VERSION 5.8 ;
BUSBITCHARS "[]" ;
DIVIDERCHAR "/" ;
UNITS
    DATABASE MICRONS 1000 ;
END UNITS

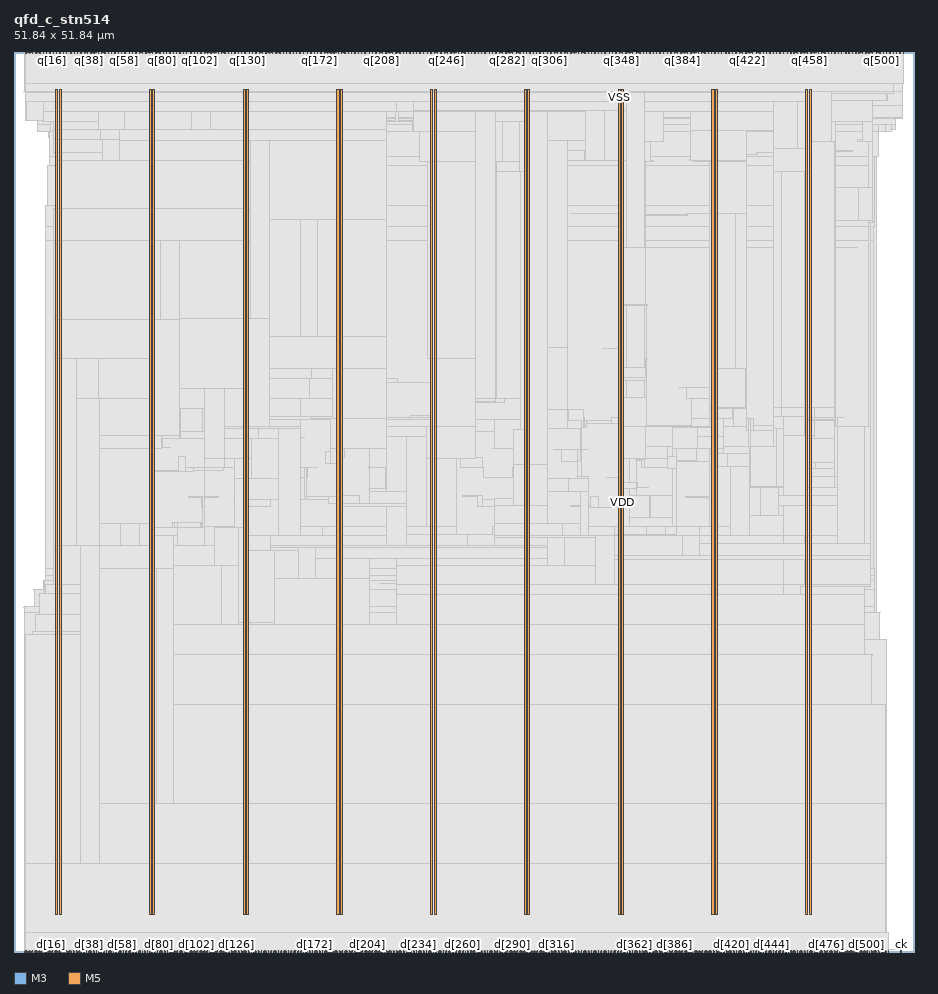
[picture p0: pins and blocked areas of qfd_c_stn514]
MACRO qfd_c_stn514
  FOREIGN qfd_c_stn514 0 0 ;
  CLASS BLOCK ;
  SIZE 51.84 BY 51.84 ;
  PIN ck
    DIRECTION INPUT ;
    USE SIGNAL ;
    PORT
      LAYER M3 ;
        RECT  51.084 0 51.102 0.038 ;
    END
    PORT
      LAYER M3 ;
        RECT  51.084 0.012 51.102 0.173 ;
    END
  END ck
  PIN d[0]
    DIRECTION INPUT ;
    USE SIGNAL ;
    PORT
      LAYER M3 ;
        RECT  0.576 0 0.594 0.038 ;
    END
  END d[0]
  PIN d[100]
    DIRECTION INPUT ;
    USE SIGNAL ;
    PORT
      LAYER M3 ;
        RECT  10.296 0 10.314 0.038 ;
    END
  END d[100]
  PIN d[101]
    DIRECTION INPUT ;
    USE SIGNAL ;
    PORT
      LAYER M5 ;
        RECT  10.368 0 10.392 0.084 ;
    END
  END d[101]
  PIN d[102]
    DIRECTION INPUT ;
    USE SIGNAL ;
    PORT
      LAYER M3 ;
        RECT  10.476 0 10.494 0.038 ;
    END
  END d[102]
  PIN d[103]
    DIRECTION INPUT ;
    USE SIGNAL ;
    PORT
      LAYER M5 ;
        RECT  10.56 0 10.584 0.084 ;
    END
  END d[103]
  PIN d[104]
    DIRECTION INPUT ;
    USE SIGNAL ;
    PORT
      LAYER M3 ;
        RECT  10.656 0 10.674 0.038 ;
    END
  END d[104]
  PIN d[105]
    DIRECTION INPUT ;
    USE SIGNAL ;
    PORT
      LAYER M5 ;
        RECT  10.752 0 10.776 0.084 ;
    END
  END d[105]
  PIN d[106]
    DIRECTION INPUT ;
    USE SIGNAL ;
    PORT
      LAYER M3 ;
        RECT  10.872 0 10.89 0.038 ;
    END
  END d[106]
  PIN d[107]
    DIRECTION INPUT ;
    USE SIGNAL ;
    PORT
      LAYER M5 ;
        RECT  10.944 0 10.968 0.084 ;
    END
  END d[107]
  PIN d[108]
    DIRECTION INPUT ;
    USE SIGNAL ;
    PORT
      LAYER M3 ;
        RECT  11.052 0 11.07 0.038 ;
    END
  END d[108]
  PIN d[109]
    DIRECTION INPUT ;
    USE SIGNAL ;
    PORT
      LAYER M5 ;
        RECT  11.136 0 11.16 0.084 ;
    END
  END d[109]
  PIN d[10]
    DIRECTION INPUT ;
    USE SIGNAL ;
    PORT
      LAYER M3 ;
        RECT  1.548 0 1.566 0.038 ;
    END
  END d[10]
  PIN d[110]
    DIRECTION INPUT ;
    USE SIGNAL ;
    PORT
      LAYER M3 ;
        RECT  11.268 0 11.286 0.038 ;
    END
  END d[110]
  PIN d[111]
    DIRECTION INPUT ;
    USE SIGNAL ;
    PORT
      LAYER M5 ;
        RECT  11.328 0 11.352 0.084 ;
    END
  END d[111]
  PIN d[112]
    DIRECTION INPUT ;
    USE SIGNAL ;
    PORT
      LAYER M3 ;
        RECT  11.448 0 11.466 0.038 ;
    END
  END d[112]
  PIN d[113]
    DIRECTION INPUT ;
    USE SIGNAL ;
    PORT
      LAYER M5 ;
        RECT  11.52 0 11.544 0.084 ;
    END
  END d[113]
  PIN d[114]
    DIRECTION INPUT ;
    USE SIGNAL ;
    PORT
      LAYER M3 ;
        RECT  11.628 0 11.646 0.038 ;
    END
  END d[114]
  PIN d[115]
    DIRECTION INPUT ;
    USE SIGNAL ;
    PORT
      LAYER M5 ;
        RECT  11.712 0 11.736 0.084 ;
    END
  END d[115]
  PIN d[116]
    DIRECTION INPUT ;
    USE SIGNAL ;
    PORT
      LAYER M3 ;
        RECT  11.844 0 11.862 0.038 ;
    END
  END d[116]
  PIN d[117]
    DIRECTION INPUT ;
    USE SIGNAL ;
    PORT
      LAYER M5 ;
        RECT  11.904 0 11.928 0.084 ;
    END
  END d[117]
  PIN d[118]
    DIRECTION INPUT ;
    USE SIGNAL ;
    PORT
      LAYER M3 ;
        RECT  12.024 0 12.042 0.038 ;
    END
  END d[118]
  PIN d[119]
    DIRECTION INPUT ;
    USE SIGNAL ;
    PORT
      LAYER M5 ;
        RECT  12.144 0 12.168 0.084 ;
    END
  END d[119]
  PIN d[11]
    DIRECTION INPUT ;
    USE SIGNAL ;
    PORT
      LAYER M5 ;
        RECT  1.632 0 1.656 0.084 ;
    END
  END d[11]
  PIN d[120]
    DIRECTION INPUT ;
    USE SIGNAL ;
    PORT
      LAYER M3 ;
        RECT  12.204 0 12.222 0.038 ;
    END
  END d[120]
  PIN d[121]
    DIRECTION INPUT ;
    USE SIGNAL ;
    PORT
      LAYER M5 ;
        RECT  12.336 0 12.36 0.084 ;
    END
  END d[121]
  PIN d[122]
    DIRECTION INPUT ;
    USE SIGNAL ;
    PORT
      LAYER M3 ;
        RECT  12.42 0 12.438 0.038 ;
    END
  END d[122]
  PIN d[123]
    DIRECTION INPUT ;
    USE SIGNAL ;
    PORT
      LAYER M5 ;
        RECT  12.528 0 12.552 0.084 ;
    END
  END d[123]
  PIN d[124]
    DIRECTION INPUT ;
    USE SIGNAL ;
    PORT
      LAYER M3 ;
        RECT  12.6 0 12.618 0.038 ;
    END
  END d[124]
  PIN d[125]
    DIRECTION INPUT ;
    USE SIGNAL ;
    PORT
      LAYER M5 ;
        RECT  12.72 0 12.744 0.084 ;
    END
  END d[125]
  PIN d[126]
    DIRECTION INPUT ;
    USE SIGNAL ;
    PORT
      LAYER M3 ;
        RECT  12.816 0 12.834 0.038 ;
    END
  END d[126]
  PIN d[127]
    DIRECTION INPUT ;
    USE SIGNAL ;
    PORT
      LAYER M5 ;
        RECT  12.912 0 12.936 0.084 ;
    END
  END d[127]
  PIN d[128]
    DIRECTION INPUT ;
    USE SIGNAL ;
    PORT
      LAYER M3 ;
        RECT  12.996 0 13.014 0.038 ;
    END
  END d[128]
  PIN d[129]
    DIRECTION INPUT ;
    USE SIGNAL ;
    PORT
      LAYER M5 ;
        RECT  13.104 0 13.128 0.084 ;
    END
  END d[129]
  PIN d[12]
    DIRECTION INPUT ;
    USE SIGNAL ;
    PORT
      LAYER M3 ;
        RECT  1.728 0 1.746 0.038 ;
    END
  END d[12]
  PIN d[130]
    DIRECTION INPUT ;
    USE SIGNAL ;
    PORT
      LAYER M3 ;
        RECT  13.176 0 13.194 0.038 ;
    END
  END d[130]
  PIN d[131]
    DIRECTION INPUT ;
    USE SIGNAL ;
    PORT
      LAYER M5 ;
        RECT  13.296 0 13.32 0.084 ;
    END
  END d[131]
  PIN d[132]
    DIRECTION INPUT ;
    USE SIGNAL ;
    PORT
      LAYER M3 ;
        RECT  13.392 0 13.41 0.038 ;
    END
  END d[132]
  PIN d[133]
    DIRECTION INPUT ;
    USE SIGNAL ;
    PORT
      LAYER M5 ;
        RECT  13.488 0 13.512 0.084 ;
    END
  END d[133]
  PIN d[134]
    DIRECTION INPUT ;
    USE SIGNAL ;
    PORT
      LAYER M3 ;
        RECT  13.572 0 13.59 0.038 ;
    END
  END d[134]
  PIN d[135]
    DIRECTION INPUT ;
    USE SIGNAL ;
    PORT
      LAYER M5 ;
        RECT  13.68 0 13.704 0.084 ;
    END
  END d[135]
  PIN d[136]
    DIRECTION INPUT ;
    USE SIGNAL ;
    PORT
      LAYER M3 ;
        RECT  13.788 0 13.806 0.038 ;
    END
  END d[136]
  PIN d[137]
    DIRECTION INPUT ;
    USE SIGNAL ;
    PORT
      LAYER M5 ;
        RECT  13.872 0 13.896 0.084 ;
    END
  END d[137]
  PIN d[138]
    DIRECTION INPUT ;
    USE SIGNAL ;
    PORT
      LAYER M3 ;
        RECT  13.968 0 13.986 0.038 ;
    END
  END d[138]
  PIN d[139]
    DIRECTION INPUT ;
    USE SIGNAL ;
    PORT
      LAYER M5 ;
        RECT  14.064 0 14.088 0.084 ;
    END
  END d[139]
  PIN d[13]
    DIRECTION INPUT ;
    USE SIGNAL ;
    PORT
      LAYER M5 ;
        RECT  1.824 0 1.848 0.084 ;
    END
  END d[13]
  PIN d[140]
    DIRECTION INPUT ;
    USE SIGNAL ;
    PORT
      LAYER M3 ;
        RECT  14.148 0 14.166 0.038 ;
    END
  END d[140]
  PIN d[141]
    DIRECTION INPUT ;
    USE SIGNAL ;
    PORT
      LAYER M5 ;
        RECT  14.256 0 14.28 0.084 ;
    END
  END d[141]
  PIN d[142]
    DIRECTION INPUT ;
    USE SIGNAL ;
    PORT
      LAYER M3 ;
        RECT  14.364 0 14.382 0.038 ;
    END
  END d[142]
  PIN d[143]
    DIRECTION INPUT ;
    USE SIGNAL ;
    PORT
      LAYER M5 ;
        RECT  14.448 0 14.472 0.084 ;
    END
  END d[143]
  PIN d[144]
    DIRECTION INPUT ;
    USE SIGNAL ;
    PORT
      LAYER M3 ;
        RECT  14.544 0 14.562 0.038 ;
    END
  END d[144]
  PIN d[145]
    DIRECTION INPUT ;
    USE SIGNAL ;
    PORT
      LAYER M5 ;
        RECT  14.64 0 14.664 0.084 ;
    END
  END d[145]
  PIN d[146]
    DIRECTION INPUT ;
    USE SIGNAL ;
    PORT
      LAYER M3 ;
        RECT  14.76 0 14.778 0.038 ;
    END
  END d[146]
  PIN d[147]
    DIRECTION INPUT ;
    USE SIGNAL ;
    PORT
      LAYER M5 ;
        RECT  14.832 0 14.856 0.084 ;
    END
  END d[147]
  PIN d[148]
    DIRECTION INPUT ;
    USE SIGNAL ;
    PORT
      LAYER M3 ;
        RECT  14.94 0 14.958 0.038 ;
    END
  END d[148]
  PIN d[149]
    DIRECTION INPUT ;
    USE SIGNAL ;
    PORT
      LAYER M5 ;
        RECT  15.024 0 15.048 0.084 ;
    END
  END d[149]
  PIN d[14]
    DIRECTION INPUT ;
    USE SIGNAL ;
    PORT
      LAYER M3 ;
        RECT  1.944 0 1.962 0.038 ;
    END
  END d[14]
  PIN d[150]
    DIRECTION INPUT ;
    USE SIGNAL ;
    PORT
      LAYER M3 ;
        RECT  15.12 0 15.138 0.038 ;
    END
  END d[150]
  PIN d[151]
    DIRECTION INPUT ;
    USE SIGNAL ;
    PORT
      LAYER M5 ;
        RECT  15.216 0 15.24 0.084 ;
    END
  END d[151]
  PIN d[152]
    DIRECTION INPUT ;
    USE SIGNAL ;
    PORT
      LAYER M3 ;
        RECT  15.336 0 15.354 0.038 ;
    END
  END d[152]
  PIN d[153]
    DIRECTION INPUT ;
    USE SIGNAL ;
    PORT
      LAYER M5 ;
        RECT  15.408 0 15.432 0.084 ;
    END
  END d[153]
  PIN d[154]
    DIRECTION INPUT ;
    USE SIGNAL ;
    PORT
      LAYER M3 ;
        RECT  15.516 0 15.534 0.038 ;
    END
  END d[154]
  PIN d[155]
    DIRECTION INPUT ;
    USE SIGNAL ;
    PORT
      LAYER M5 ;
        RECT  15.6 0 15.624 0.084 ;
    END
  END d[155]
  PIN d[156]
    DIRECTION INPUT ;
    USE SIGNAL ;
    PORT
      LAYER M3 ;
        RECT  15.696 0 15.714 0.038 ;
    END
  END d[156]
  PIN d[157]
    DIRECTION INPUT ;
    USE SIGNAL ;
    PORT
      LAYER M5 ;
        RECT  15.792 0 15.816 0.084 ;
    END
  END d[157]
  PIN d[158]
    DIRECTION INPUT ;
    USE SIGNAL ;
    PORT
      LAYER M3 ;
        RECT  15.912 0 15.93 0.038 ;
    END
  END d[158]
  PIN d[159]
    DIRECTION INPUT ;
    USE SIGNAL ;
    PORT
      LAYER M5 ;
        RECT  15.984 0 16.008 0.084 ;
    END
  END d[159]
  PIN d[15]
    DIRECTION INPUT ;
    USE SIGNAL ;
    PORT
      LAYER M5 ;
        RECT  2.016 0 2.04 0.084 ;
    END
  END d[15]
  PIN d[160]
    DIRECTION INPUT ;
    USE SIGNAL ;
    PORT
      LAYER M3 ;
        RECT  16.092 0 16.11 0.038 ;
    END
  END d[160]
  PIN d[161]
    DIRECTION INPUT ;
    USE SIGNAL ;
    PORT
      LAYER M5 ;
        RECT  16.176 0 16.2 0.084 ;
    END
  END d[161]
  PIN d[162]
    DIRECTION INPUT ;
    USE SIGNAL ;
    PORT
      LAYER M3 ;
        RECT  16.308 0 16.326 0.038 ;
    END
  END d[162]
  PIN d[163]
    DIRECTION INPUT ;
    USE SIGNAL ;
    PORT
      LAYER M5 ;
        RECT  16.368 0 16.392 0.084 ;
    END
  END d[163]
  PIN d[164]
    DIRECTION INPUT ;
    USE SIGNAL ;
    PORT
      LAYER M3 ;
        RECT  16.488 0 16.506 0.038 ;
    END
  END d[164]
  PIN d[165]
    DIRECTION INPUT ;
    USE SIGNAL ;
    PORT
      LAYER M5 ;
        RECT  16.56 0 16.584 0.084 ;
    END
  END d[165]
  PIN d[166]
    DIRECTION INPUT ;
    USE SIGNAL ;
    PORT
      LAYER M3 ;
        RECT  16.668 0 16.686 0.038 ;
    END
  END d[166]
  PIN d[167]
    DIRECTION INPUT ;
    USE SIGNAL ;
    PORT
      LAYER M5 ;
        RECT  16.8 0 16.824 0.084 ;
    END
  END d[167]
  PIN d[168]
    DIRECTION INPUT ;
    USE SIGNAL ;
    PORT
      LAYER M3 ;
        RECT  16.884 0 16.902 0.038 ;
    END
  END d[168]
  PIN d[169]
    DIRECTION INPUT ;
    USE SIGNAL ;
    PORT
      LAYER M5 ;
        RECT  16.992 0 17.016 0.084 ;
    END
  END d[169]
  PIN d[16]
    DIRECTION INPUT ;
    USE SIGNAL ;
    PORT
      LAYER M3 ;
        RECT  2.124 0 2.142 0.038 ;
    END
  END d[16]
  PIN d[170]
    DIRECTION INPUT ;
    USE SIGNAL ;
    PORT
      LAYER M3 ;
        RECT  17.064 0 17.082 0.038 ;
    END
  END d[170]
  PIN d[171]
    DIRECTION INPUT ;
    USE SIGNAL ;
    PORT
      LAYER M5 ;
        RECT  17.184 0 17.208 0.084 ;
    END
  END d[171]
  PIN d[172]
    DIRECTION INPUT ;
    USE SIGNAL ;
    PORT
      LAYER M3 ;
        RECT  17.28 0 17.298 0.038 ;
    END
  END d[172]
  PIN d[173]
    DIRECTION INPUT ;
    USE SIGNAL ;
    PORT
      LAYER M5 ;
        RECT  17.376 0 17.4 0.084 ;
    END
  END d[173]
  PIN d[174]
    DIRECTION INPUT ;
    USE SIGNAL ;
    PORT
      LAYER M3 ;
        RECT  17.46 0 17.478 0.038 ;
    END
  END d[174]
  PIN d[175]
    DIRECTION INPUT ;
    USE SIGNAL ;
    PORT
      LAYER M5 ;
        RECT  17.568 0 17.592 0.084 ;
    END
  END d[175]
  PIN d[176]
    DIRECTION INPUT ;
    USE SIGNAL ;
    PORT
      LAYER M3 ;
        RECT  17.64 0 17.658 0.038 ;
    END
  END d[176]
  PIN d[177]
    DIRECTION INPUT ;
    USE SIGNAL ;
    PORT
      LAYER M5 ;
        RECT  17.76 0 17.784 0.084 ;
    END
  END d[177]
  PIN d[178]
    DIRECTION INPUT ;
    USE SIGNAL ;
    PORT
      LAYER M3 ;
        RECT  17.856 0 17.874 0.038 ;
    END
  END d[178]
  PIN d[179]
    DIRECTION INPUT ;
    USE SIGNAL ;
    PORT
      LAYER M5 ;
        RECT  17.952 0 17.976 0.084 ;
    END
  END d[179]
  PIN d[17]
    DIRECTION INPUT ;
    USE SIGNAL ;
    PORT
      LAYER M5 ;
        RECT  2.208 0 2.232 0.084 ;
    END
  END d[17]
  PIN d[180]
    DIRECTION INPUT ;
    USE SIGNAL ;
    PORT
      LAYER M3 ;
        RECT  18.036 0 18.054 0.038 ;
    END
  END d[180]
  PIN d[181]
    DIRECTION INPUT ;
    USE SIGNAL ;
    PORT
      LAYER M5 ;
        RECT  18.144 0 18.168 0.084 ;
    END
  END d[181]
  PIN d[182]
    DIRECTION INPUT ;
    USE SIGNAL ;
    PORT
      LAYER M3 ;
        RECT  18.252 0 18.27 0.038 ;
    END
  END d[182]
  PIN d[183]
    DIRECTION INPUT ;
    USE SIGNAL ;
    PORT
      LAYER M5 ;
        RECT  18.336 0 18.36 0.084 ;
    END
  END d[183]
  PIN d[184]
    DIRECTION INPUT ;
    USE SIGNAL ;
    PORT
      LAYER M3 ;
        RECT  18.432 0 18.45 0.038 ;
    END
  END d[184]
  PIN d[185]
    DIRECTION INPUT ;
    USE SIGNAL ;
    PORT
      LAYER M5 ;
        RECT  18.528 0 18.552 0.084 ;
    END
  END d[185]
  PIN d[186]
    DIRECTION INPUT ;
    USE SIGNAL ;
    PORT
      LAYER M3 ;
        RECT  18.612 0 18.63 0.038 ;
    END
  END d[186]
  PIN d[187]
    DIRECTION INPUT ;
    USE SIGNAL ;
    PORT
      LAYER M5 ;
        RECT  18.72 0 18.744 0.084 ;
    END
  END d[187]
  PIN d[188]
    DIRECTION INPUT ;
    USE SIGNAL ;
    PORT
      LAYER M3 ;
        RECT  18.828 0 18.846 0.038 ;
    END
  END d[188]
  PIN d[189]
    DIRECTION INPUT ;
    USE SIGNAL ;
    PORT
      LAYER M5 ;
        RECT  18.912 0 18.936 0.084 ;
    END
  END d[189]
  PIN d[18]
    DIRECTION INPUT ;
    USE SIGNAL ;
    PORT
      LAYER M3 ;
        RECT  2.34 0 2.358 0.038 ;
    END
  END d[18]
  PIN d[190]
    DIRECTION INPUT ;
    USE SIGNAL ;
    PORT
      LAYER M3 ;
        RECT  19.008 0 19.026 0.038 ;
    END
  END d[190]
  PIN d[191]
    DIRECTION INPUT ;
    USE SIGNAL ;
    PORT
      LAYER M5 ;
        RECT  19.104 0 19.128 0.084 ;
    END
  END d[191]
  PIN d[192]
    DIRECTION INPUT ;
    USE SIGNAL ;
    PORT
      LAYER M3 ;
        RECT  19.188 0 19.206 0.038 ;
    END
  END d[192]
  PIN d[193]
    DIRECTION INPUT ;
    USE SIGNAL ;
    PORT
      LAYER M5 ;
        RECT  19.296 0 19.32 0.084 ;
    END
  END d[193]
  PIN d[194]
    DIRECTION INPUT ;
    USE SIGNAL ;
    PORT
      LAYER M3 ;
        RECT  19.404 0 19.422 0.038 ;
    END
  END d[194]
  PIN d[195]
    DIRECTION INPUT ;
    USE SIGNAL ;
    PORT
      LAYER M5 ;
        RECT  19.488 0 19.512 0.084 ;
    END
  END d[195]
  PIN d[196]
    DIRECTION INPUT ;
    USE SIGNAL ;
    PORT
      LAYER M3 ;
        RECT  19.584 0 19.602 0.038 ;
    END
  END d[196]
  PIN d[197]
    DIRECTION INPUT ;
    USE SIGNAL ;
    PORT
      LAYER M5 ;
        RECT  19.68 0 19.704 0.084 ;
    END
  END d[197]
  PIN d[198]
    DIRECTION INPUT ;
    USE SIGNAL ;
    PORT
      LAYER M3 ;
        RECT  19.8 0 19.818 0.038 ;
    END
  END d[198]
  PIN d[199]
    DIRECTION INPUT ;
    USE SIGNAL ;
    PORT
      LAYER M5 ;
        RECT  19.872 0 19.896 0.084 ;
    END
  END d[199]
  PIN d[19]
    DIRECTION INPUT ;
    USE SIGNAL ;
    PORT
      LAYER M5 ;
        RECT  2.4 0 2.424 0.084 ;
    END
  END d[19]
  PIN d[1]
    DIRECTION INPUT ;
    USE SIGNAL ;
    PORT
      LAYER M5 ;
        RECT  0.672 0 0.696 0.084 ;
    END
  END d[1]
  PIN d[200]
    DIRECTION INPUT ;
    USE SIGNAL ;
    PORT
      LAYER M3 ;
        RECT  19.98 0 19.998 0.038 ;
    END
  END d[200]
  PIN d[201]
    DIRECTION INPUT ;
    USE SIGNAL ;
    PORT
      LAYER M5 ;
        RECT  20.064 0 20.088 0.084 ;
    END
  END d[201]
  PIN d[202]
    DIRECTION INPUT ;
    USE SIGNAL ;
    PORT
      LAYER M3 ;
        RECT  20.16 0 20.178 0.038 ;
    END
  END d[202]
  PIN d[203]
    DIRECTION INPUT ;
    USE SIGNAL ;
    PORT
      LAYER M5 ;
        RECT  20.256 0 20.28 0.084 ;
    END
  END d[203]
  PIN d[204]
    DIRECTION INPUT ;
    USE SIGNAL ;
    PORT
      LAYER M3 ;
        RECT  20.376 0 20.394 0.038 ;
    END
  END d[204]
  PIN d[205]
    DIRECTION INPUT ;
    USE SIGNAL ;
    PORT
      LAYER M5 ;
        RECT  20.448 0 20.472 0.084 ;
    END
  END d[205]
  PIN d[206]
    DIRECTION INPUT ;
    USE SIGNAL ;
    PORT
      LAYER M3 ;
        RECT  20.556 0 20.574 0.038 ;
    END
  END d[206]
  PIN d[207]
    DIRECTION INPUT ;
    USE SIGNAL ;
    PORT
      LAYER M5 ;
        RECT  20.64 0 20.664 0.084 ;
    END
  END d[207]
  PIN d[208]
    DIRECTION INPUT ;
    USE SIGNAL ;
    PORT
      LAYER M3 ;
        RECT  20.772 0 20.79 0.038 ;
    END
  END d[208]
  PIN d[209]
    DIRECTION INPUT ;
    USE SIGNAL ;
    PORT
      LAYER M5 ;
        RECT  20.832 0 20.856 0.084 ;
    END
  END d[209]
  PIN d[20]
    DIRECTION INPUT ;
    USE SIGNAL ;
    PORT
      LAYER M3 ;
        RECT  2.52 0 2.538 0.038 ;
    END
  END d[20]
  PIN d[210]
    DIRECTION INPUT ;
    USE SIGNAL ;
    PORT
      LAYER M3 ;
        RECT  20.952 0 20.97 0.038 ;
    END
  END d[210]
  PIN d[211]
    DIRECTION INPUT ;
    USE SIGNAL ;
    PORT
      LAYER M5 ;
        RECT  21.024 0 21.048 0.084 ;
    END
  END d[211]
  PIN d[212]
    DIRECTION INPUT ;
    USE SIGNAL ;
    PORT
      LAYER M3 ;
        RECT  21.132 0 21.15 0.038 ;
    END
  END d[212]
  PIN d[213]
    DIRECTION INPUT ;
    USE SIGNAL ;
    PORT
      LAYER M5 ;
        RECT  21.216 0 21.24 0.084 ;
    END
  END d[213]
  PIN d[214]
    DIRECTION INPUT ;
    USE SIGNAL ;
    PORT
      LAYER M3 ;
        RECT  21.348 0 21.366 0.038 ;
    END
  END d[214]
  PIN d[215]
    DIRECTION INPUT ;
    USE SIGNAL ;
    PORT
      LAYER M5 ;
        RECT  21.456 0 21.48 0.084 ;
    END
  END d[215]
  PIN d[216]
    DIRECTION INPUT ;
    USE SIGNAL ;
    PORT
      LAYER M3 ;
        RECT  21.528 0 21.546 0.038 ;
    END
  END d[216]
  PIN d[217]
    DIRECTION INPUT ;
    USE SIGNAL ;
    PORT
      LAYER M5 ;
        RECT  21.648 0 21.672 0.084 ;
    END
  END d[217]
  PIN d[218]
    DIRECTION INPUT ;
    USE SIGNAL ;
    PORT
      LAYER M3 ;
        RECT  21.744 0 21.762 0.038 ;
    END
  END d[218]
  PIN d[219]
    DIRECTION INPUT ;
    USE SIGNAL ;
    PORT
      LAYER M5 ;
        RECT  21.84 0 21.864 0.084 ;
    END
  END d[219]
  PIN d[21]
    DIRECTION INPUT ;
    USE SIGNAL ;
    PORT
      LAYER M5 ;
        RECT  2.592 0 2.616 0.084 ;
    END
  END d[21]
  PIN d[220]
    DIRECTION INPUT ;
    USE SIGNAL ;
    PORT
      LAYER M3 ;
        RECT  21.924 0 21.942 0.038 ;
    END
  END d[220]
  PIN d[221]
    DIRECTION INPUT ;
    USE SIGNAL ;
    PORT
      LAYER M5 ;
        RECT  22.032 0 22.056 0.084 ;
    END
  END d[221]
  PIN d[222]
    DIRECTION INPUT ;
    USE SIGNAL ;
    PORT
      LAYER M3 ;
        RECT  22.104 0 22.122 0.038 ;
    END
  END d[222]
  PIN d[223]
    DIRECTION INPUT ;
    USE SIGNAL ;
    PORT
      LAYER M5 ;
        RECT  22.224 0 22.248 0.084 ;
    END
  END d[223]
  PIN d[224]
    DIRECTION INPUT ;
    USE SIGNAL ;
    PORT
      LAYER M3 ;
        RECT  22.32 0 22.338 0.038 ;
    END
  END d[224]
  PIN d[225]
    DIRECTION INPUT ;
    USE SIGNAL ;
    PORT
      LAYER M5 ;
        RECT  22.416 0 22.44 0.084 ;
    END
  END d[225]
  PIN d[226]
    DIRECTION INPUT ;
    USE SIGNAL ;
    PORT
      LAYER M3 ;
        RECT  22.5 0 22.518 0.038 ;
    END
  END d[226]
  PIN d[227]
    DIRECTION INPUT ;
    USE SIGNAL ;
    PORT
      LAYER M5 ;
        RECT  22.608 0 22.632 0.084 ;
    END
  END d[227]
  PIN d[228]
    DIRECTION INPUT ;
    USE SIGNAL ;
    PORT
      LAYER M3 ;
        RECT  22.68 0 22.698 0.038 ;
    END
  END d[228]
  PIN d[229]
    DIRECTION INPUT ;
    USE SIGNAL ;
    PORT
      LAYER M5 ;
        RECT  22.8 0 22.824 0.084 ;
    END
  END d[229]
  PIN d[22]
    DIRECTION INPUT ;
    USE SIGNAL ;
    PORT
      LAYER M3 ;
        RECT  2.7 0 2.718 0.038 ;
    END
  END d[22]
  PIN d[230]
    DIRECTION INPUT ;
    USE SIGNAL ;
    PORT
      LAYER M3 ;
        RECT  22.896 0 22.914 0.038 ;
    END
  END d[230]
  PIN d[231]
    DIRECTION INPUT ;
    USE SIGNAL ;
    PORT
      LAYER M5 ;
        RECT  22.992 0 23.016 0.084 ;
    END
  END d[231]
  PIN d[232]
    DIRECTION INPUT ;
    USE SIGNAL ;
    PORT
      LAYER M3 ;
        RECT  23.076 0 23.094 0.038 ;
    END
  END d[232]
  PIN d[233]
    DIRECTION INPUT ;
    USE SIGNAL ;
    PORT
      LAYER M5 ;
        RECT  23.184 0 23.208 0.084 ;
    END
  END d[233]
  PIN d[234]
    DIRECTION INPUT ;
    USE SIGNAL ;
    PORT
      LAYER M3 ;
        RECT  23.292 0 23.31 0.038 ;
    END
  END d[234]
  PIN d[235]
    DIRECTION INPUT ;
    USE SIGNAL ;
    PORT
      LAYER M5 ;
        RECT  23.376 0 23.4 0.084 ;
    END
  END d[235]
  PIN d[236]
    DIRECTION INPUT ;
    USE SIGNAL ;
    PORT
      LAYER M3 ;
        RECT  23.472 0 23.49 0.038 ;
    END
  END d[236]
  PIN d[237]
    DIRECTION INPUT ;
    USE SIGNAL ;
    PORT
      LAYER M5 ;
        RECT  23.568 0 23.592 0.084 ;
    END
  END d[237]
  PIN d[238]
    DIRECTION INPUT ;
    USE SIGNAL ;
    PORT
      LAYER M3 ;
        RECT  23.652 0 23.67 0.038 ;
    END
  END d[238]
  PIN d[239]
    DIRECTION INPUT ;
    USE SIGNAL ;
    PORT
      LAYER M5 ;
        RECT  23.76 0 23.784 0.084 ;
    END
  END d[239]
  PIN d[23]
    DIRECTION INPUT ;
    USE SIGNAL ;
    PORT
      LAYER M5 ;
        RECT  2.832 0 2.856 0.084 ;
    END
  END d[23]
  PIN d[240]
    DIRECTION INPUT ;
    USE SIGNAL ;
    PORT
      LAYER M3 ;
        RECT  23.868 0 23.886 0.038 ;
    END
  END d[240]
  PIN d[241]
    DIRECTION INPUT ;
    USE SIGNAL ;
    PORT
      LAYER M5 ;
        RECT  23.952 0 23.976 0.084 ;
    END
  END d[241]
  PIN d[242]
    DIRECTION INPUT ;
    USE SIGNAL ;
    PORT
      LAYER M3 ;
        RECT  24.048 0 24.066 0.038 ;
    END
  END d[242]
  PIN d[243]
    DIRECTION INPUT ;
    USE SIGNAL ;
    PORT
      LAYER M5 ;
        RECT  24.144 0 24.168 0.084 ;
    END
  END d[243]
  PIN d[244]
    DIRECTION INPUT ;
    USE SIGNAL ;
    PORT
      LAYER M3 ;
        RECT  24.264 0 24.282 0.038 ;
    END
  END d[244]
  PIN d[245]
    DIRECTION INPUT ;
    USE SIGNAL ;
    PORT
      LAYER M5 ;
        RECT  24.336 0 24.36 0.084 ;
    END
  END d[245]
  PIN d[246]
    DIRECTION INPUT ;
    USE SIGNAL ;
    PORT
      LAYER M3 ;
        RECT  24.444 0 24.462 0.038 ;
    END
  END d[246]
  PIN d[247]
    DIRECTION INPUT ;
    USE SIGNAL ;
    PORT
      LAYER M5 ;
        RECT  24.528 0 24.552 0.084 ;
    END
  END d[247]
  PIN d[248]
    DIRECTION INPUT ;
    USE SIGNAL ;
    PORT
      LAYER M3 ;
        RECT  24.624 0 24.642 0.038 ;
    END
  END d[248]
  PIN d[249]
    DIRECTION INPUT ;
    USE SIGNAL ;
    PORT
      LAYER M5 ;
        RECT  24.72 0 24.744 0.084 ;
    END
  END d[249]
  PIN d[24]
    DIRECTION INPUT ;
    USE SIGNAL ;
    PORT
      LAYER M3 ;
        RECT  2.916 0 2.934 0.038 ;
    END
  END d[24]
  PIN d[250]
    DIRECTION INPUT ;
    USE SIGNAL ;
    PORT
      LAYER M3 ;
        RECT  24.84 0 24.858 0.038 ;
    END
  END d[250]
  PIN d[251]
    DIRECTION INPUT ;
    USE SIGNAL ;
    PORT
      LAYER M5 ;
        RECT  24.912 0 24.936 0.084 ;
    END
  END d[251]
  PIN d[252]
    DIRECTION INPUT ;
    USE SIGNAL ;
    PORT
      LAYER M3 ;
        RECT  25.02 0 25.038 0.038 ;
    END
  END d[252]
  PIN d[253]
    DIRECTION INPUT ;
    USE SIGNAL ;
    PORT
      LAYER M5 ;
        RECT  25.104 0 25.128 0.084 ;
    END
  END d[253]
  PIN d[254]
    DIRECTION INPUT ;
    USE SIGNAL ;
    PORT
      LAYER M3 ;
        RECT  25.236 0 25.254 0.038 ;
    END
  END d[254]
  PIN d[255]
    DIRECTION INPUT ;
    USE SIGNAL ;
    PORT
      LAYER M5 ;
        RECT  25.296 0 25.32 0.084 ;
    END
  END d[255]
  PIN d[256]
    DIRECTION INPUT ;
    USE SIGNAL ;
    PORT
      LAYER M3 ;
        RECT  25.416 0 25.434 0.038 ;
    END
  END d[256]
  PIN d[257]
    DIRECTION INPUT ;
    USE SIGNAL ;
    PORT
      LAYER M5 ;
        RECT  25.488 0 25.512 0.084 ;
    END
  END d[257]
  PIN d[258]
    DIRECTION INPUT ;
    USE SIGNAL ;
    PORT
      LAYER M3 ;
        RECT  25.596 0 25.614 0.038 ;
    END
  END d[258]
  PIN d[259]
    DIRECTION INPUT ;
    USE SIGNAL ;
    PORT
      LAYER M5 ;
        RECT  25.68 0 25.704 0.084 ;
    END
  END d[259]
  PIN d[25]
    DIRECTION INPUT ;
    USE SIGNAL ;
    PORT
      LAYER M5 ;
        RECT  3.024 0 3.048 0.084 ;
    END
  END d[25]
  PIN d[260]
    DIRECTION INPUT ;
    USE SIGNAL ;
    PORT
      LAYER M3 ;
        RECT  25.812 0 25.83 0.038 ;
    END
  END d[260]
  PIN d[261]
    DIRECTION INPUT ;
    USE SIGNAL ;
    PORT
      LAYER M5 ;
        RECT  25.872 0 25.896 0.084 ;
    END
  END d[261]
  PIN d[262]
    DIRECTION INPUT ;
    USE SIGNAL ;
    PORT
      LAYER M3 ;
        RECT  25.992 0 26.01 0.038 ;
    END
  END d[262]
  PIN d[263]
    DIRECTION INPUT ;
    USE SIGNAL ;
    PORT
      LAYER M5 ;
        RECT  26.112 0 26.136 0.084 ;
    END
  END d[263]
  PIN d[264]
    DIRECTION INPUT ;
    USE SIGNAL ;
    PORT
      LAYER M3 ;
        RECT  26.172 0 26.19 0.038 ;
    END
  END d[264]
  PIN d[265]
    DIRECTION INPUT ;
    USE SIGNAL ;
    PORT
      LAYER M5 ;
        RECT  26.304 0 26.328 0.084 ;
    END
  END d[265]
  PIN d[266]
    DIRECTION INPUT ;
    USE SIGNAL ;
    PORT
      LAYER M3 ;
        RECT  26.388 0 26.406 0.038 ;
    END
  END d[266]
  PIN d[267]
    DIRECTION INPUT ;
    USE SIGNAL ;
    PORT
      LAYER M5 ;
        RECT  26.496 0 26.52 0.084 ;
    END
  END d[267]
  PIN d[268]
    DIRECTION INPUT ;
    USE SIGNAL ;
    PORT
      LAYER M3 ;
        RECT  26.568 0 26.586 0.038 ;
    END
  END d[268]
  PIN d[269]
    DIRECTION INPUT ;
    USE SIGNAL ;
    PORT
      LAYER M5 ;
        RECT  26.688 0 26.712 0.084 ;
    END
  END d[269]
  PIN d[26]
    DIRECTION INPUT ;
    USE SIGNAL ;
    PORT
      LAYER M3 ;
        RECT  3.096 0 3.114 0.038 ;
    END
  END d[26]
  PIN d[270]
    DIRECTION INPUT ;
    USE SIGNAL ;
    PORT
      LAYER M3 ;
        RECT  26.784 0 26.802 0.038 ;
    END
  END d[270]
  PIN d[271]
    DIRECTION INPUT ;
    USE SIGNAL ;
    PORT
      LAYER M5 ;
        RECT  26.88 0 26.904 0.084 ;
    END
  END d[271]
  PIN d[272]
    DIRECTION INPUT ;
    USE SIGNAL ;
    PORT
      LAYER M3 ;
        RECT  26.964 0 26.982 0.038 ;
    END
  END d[272]
  PIN d[273]
    DIRECTION INPUT ;
    USE SIGNAL ;
    PORT
      LAYER M5 ;
        RECT  27.072 0 27.096 0.084 ;
    END
  END d[273]
  PIN d[274]
    DIRECTION INPUT ;
    USE SIGNAL ;
    PORT
      LAYER M3 ;
        RECT  27.144 0 27.162 0.038 ;
    END
  END d[274]
  PIN d[275]
    DIRECTION INPUT ;
    USE SIGNAL ;
    PORT
      LAYER M5 ;
        RECT  27.264 0 27.288 0.084 ;
    END
  END d[275]
  PIN d[276]
    DIRECTION INPUT ;
    USE SIGNAL ;
    PORT
      LAYER M3 ;
        RECT  27.36 0 27.378 0.038 ;
    END
  END d[276]
  PIN d[277]
    DIRECTION INPUT ;
    USE SIGNAL ;
    PORT
      LAYER M5 ;
        RECT  27.456 0 27.48 0.084 ;
    END
  END d[277]
  PIN d[278]
    DIRECTION INPUT ;
    USE SIGNAL ;
    PORT
      LAYER M3 ;
        RECT  27.54 0 27.558 0.038 ;
    END
  END d[278]
  PIN d[279]
    DIRECTION INPUT ;
    USE SIGNAL ;
    PORT
      LAYER M5 ;
        RECT  27.648 0 27.672 0.084 ;
    END
  END d[279]
  PIN d[27]
    DIRECTION INPUT ;
    USE SIGNAL ;
    PORT
      LAYER M5 ;
        RECT  3.216 0 3.24 0.084 ;
    END
  END d[27]
  PIN d[280]
    DIRECTION INPUT ;
    USE SIGNAL ;
    PORT
      LAYER M3 ;
        RECT  27.756 0 27.774 0.038 ;
    END
  END d[280]
  PIN d[281]
    DIRECTION INPUT ;
    USE SIGNAL ;
    PORT
      LAYER M5 ;
        RECT  27.84 0 27.864 0.084 ;
    END
  END d[281]
  PIN d[282]
    DIRECTION INPUT ;
    USE SIGNAL ;
    PORT
      LAYER M3 ;
        RECT  27.936 0 27.954 0.038 ;
    END
  END d[282]
  PIN d[283]
    DIRECTION INPUT ;
    USE SIGNAL ;
    PORT
      LAYER M5 ;
        RECT  28.032 0 28.056 0.084 ;
    END
  END d[283]
  PIN d[284]
    DIRECTION INPUT ;
    USE SIGNAL ;
    PORT
      LAYER M3 ;
        RECT  28.116 0 28.134 0.038 ;
    END
  END d[284]
  PIN d[285]
    DIRECTION INPUT ;
    USE SIGNAL ;
    PORT
      LAYER M5 ;
        RECT  28.224 0 28.248 0.084 ;
    END
  END d[285]
  PIN d[286]
    DIRECTION INPUT ;
    USE SIGNAL ;
    PORT
      LAYER M3 ;
        RECT  28.332 0 28.35 0.038 ;
    END
  END d[286]
  PIN d[287]
    DIRECTION INPUT ;
    USE SIGNAL ;
    PORT
      LAYER M5 ;
        RECT  28.416 0 28.44 0.084 ;
    END
  END d[287]
  PIN d[288]
    DIRECTION INPUT ;
    USE SIGNAL ;
    PORT
      LAYER M3 ;
        RECT  28.512 0 28.53 0.038 ;
    END
  END d[288]
  PIN d[289]
    DIRECTION INPUT ;
    USE SIGNAL ;
    PORT
      LAYER M5 ;
        RECT  28.608 0 28.632 0.084 ;
    END
  END d[289]
  PIN d[28]
    DIRECTION INPUT ;
    USE SIGNAL ;
    PORT
      LAYER M3 ;
        RECT  3.312 0 3.33 0.038 ;
    END
  END d[28]
  PIN d[290]
    DIRECTION INPUT ;
    USE SIGNAL ;
    PORT
      LAYER M3 ;
        RECT  28.728 0 28.746 0.038 ;
    END
  END d[290]
  PIN d[291]
    DIRECTION INPUT ;
    USE SIGNAL ;
    PORT
      LAYER M5 ;
        RECT  28.8 0 28.824 0.084 ;
    END
  END d[291]
  PIN d[292]
    DIRECTION INPUT ;
    USE SIGNAL ;
    PORT
      LAYER M3 ;
        RECT  28.908 0 28.926 0.038 ;
    END
  END d[292]
  PIN d[293]
    DIRECTION INPUT ;
    USE SIGNAL ;
    PORT
      LAYER M5 ;
        RECT  28.992 0 29.016 0.084 ;
    END
  END d[293]
  PIN d[294]
    DIRECTION INPUT ;
    USE SIGNAL ;
    PORT
      LAYER M3 ;
        RECT  29.088 0 29.106 0.038 ;
    END
  END d[294]
  PIN d[295]
    DIRECTION INPUT ;
    USE SIGNAL ;
    PORT
      LAYER M5 ;
        RECT  29.184 0 29.208 0.084 ;
    END
  END d[295]
  PIN d[296]
    DIRECTION INPUT ;
    USE SIGNAL ;
    PORT
      LAYER M3 ;
        RECT  29.304 0 29.322 0.038 ;
    END
  END d[296]
  PIN d[297]
    DIRECTION INPUT ;
    USE SIGNAL ;
    PORT
      LAYER M5 ;
        RECT  29.376 0 29.4 0.084 ;
    END
  END d[297]
  PIN d[298]
    DIRECTION INPUT ;
    USE SIGNAL ;
    PORT
      LAYER M3 ;
        RECT  29.484 0 29.502 0.038 ;
    END
  END d[298]
  PIN d[299]
    DIRECTION INPUT ;
    USE SIGNAL ;
    PORT
      LAYER M5 ;
        RECT  29.568 0 29.592 0.084 ;
    END
  END d[299]
  PIN d[29]
    DIRECTION INPUT ;
    USE SIGNAL ;
    PORT
      LAYER M5 ;
        RECT  3.408 0 3.432 0.084 ;
    END
  END d[29]
  PIN d[2]
    DIRECTION INPUT ;
    USE SIGNAL ;
    PORT
      LAYER M3 ;
        RECT  0.792 0 0.81 0.038 ;
    END
  END d[2]
  PIN d[300]
    DIRECTION INPUT ;
    USE SIGNAL ;
    PORT
      LAYER M3 ;
        RECT  29.664 0 29.682 0.038 ;
    END
  END d[300]
  PIN d[301]
    DIRECTION INPUT ;
    USE SIGNAL ;
    PORT
      LAYER M5 ;
        RECT  29.76 0 29.784 0.084 ;
    END
  END d[301]
  PIN d[302]
    DIRECTION INPUT ;
    USE SIGNAL ;
    PORT
      LAYER M3 ;
        RECT  29.88 0 29.898 0.038 ;
    END
  END d[302]
  PIN d[303]
    DIRECTION INPUT ;
    USE SIGNAL ;
    PORT
      LAYER M5 ;
        RECT  29.952 0 29.976 0.084 ;
    END
  END d[303]
  PIN d[304]
    DIRECTION INPUT ;
    USE SIGNAL ;
    PORT
      LAYER M3 ;
        RECT  30.06 0 30.078 0.038 ;
    END
  END d[304]
  PIN d[305]
    DIRECTION INPUT ;
    USE SIGNAL ;
    PORT
      LAYER M5 ;
        RECT  30.144 0 30.168 0.084 ;
    END
  END d[305]
  PIN d[306]
    DIRECTION INPUT ;
    USE SIGNAL ;
    PORT
      LAYER M3 ;
        RECT  30.276 0 30.294 0.038 ;
    END
  END d[306]
  PIN d[307]
    DIRECTION INPUT ;
    USE SIGNAL ;
    PORT
      LAYER M5 ;
        RECT  30.336 0 30.36 0.084 ;
    END
  END d[307]
  PIN d[308]
    DIRECTION INPUT ;
    USE SIGNAL ;
    PORT
      LAYER M3 ;
        RECT  30.456 0 30.474 0.038 ;
    END
  END d[308]
  PIN d[309]
    DIRECTION INPUT ;
    USE SIGNAL ;
    PORT
      LAYER M5 ;
        RECT  30.528 0 30.552 0.084 ;
    END
  END d[309]
  PIN d[30]
    DIRECTION INPUT ;
    USE SIGNAL ;
    PORT
      LAYER M3 ;
        RECT  3.492 0 3.51 0.038 ;
    END
  END d[30]
  PIN d[310]
    DIRECTION INPUT ;
    USE SIGNAL ;
    PORT
      LAYER M3 ;
        RECT  30.636 0 30.654 0.038 ;
    END
  END d[310]
  PIN d[311]
    DIRECTION INPUT ;
    USE SIGNAL ;
    PORT
      LAYER M5 ;
        RECT  30.768 0 30.792 0.084 ;
    END
  END d[311]
  PIN d[312]
    DIRECTION INPUT ;
    USE SIGNAL ;
    PORT
      LAYER M3 ;
        RECT  30.852 0 30.87 0.038 ;
    END
  END d[312]
  PIN d[313]
    DIRECTION INPUT ;
    USE SIGNAL ;
    PORT
      LAYER M5 ;
        RECT  30.96 0 30.984 0.084 ;
    END
  END d[313]
  PIN d[314]
    DIRECTION INPUT ;
    USE SIGNAL ;
    PORT
      LAYER M3 ;
        RECT  31.032 0 31.05 0.038 ;
    END
  END d[314]
  PIN d[315]
    DIRECTION INPUT ;
    USE SIGNAL ;
    PORT
      LAYER M5 ;
        RECT  31.152 0 31.176 0.084 ;
    END
  END d[315]
  PIN d[316]
    DIRECTION INPUT ;
    USE SIGNAL ;
    PORT
      LAYER M3 ;
        RECT  31.248 0 31.266 0.038 ;
    END
  END d[316]
  PIN d[317]
    DIRECTION INPUT ;
    USE SIGNAL ;
    PORT
      LAYER M5 ;
        RECT  31.344 0 31.368 0.084 ;
    END
  END d[317]
  PIN d[318]
    DIRECTION INPUT ;
    USE SIGNAL ;
    PORT
      LAYER M3 ;
        RECT  31.428 0 31.446 0.038 ;
    END
  END d[318]
  PIN d[319]
    DIRECTION INPUT ;
    USE SIGNAL ;
    PORT
      LAYER M5 ;
        RECT  31.536 0 31.56 0.084 ;
    END
  END d[319]
  PIN d[31]
    DIRECTION INPUT ;
    USE SIGNAL ;
    PORT
      LAYER M5 ;
        RECT  3.6 0 3.624 0.084 ;
    END
  END d[31]
  PIN d[320]
    DIRECTION INPUT ;
    USE SIGNAL ;
    PORT
      LAYER M3 ;
        RECT  31.608 0 31.626 0.038 ;
    END
  END d[320]
  PIN d[321]
    DIRECTION INPUT ;
    USE SIGNAL ;
    PORT
      LAYER M5 ;
        RECT  31.728 0 31.752 0.084 ;
    END
  END d[321]
  PIN d[322]
    DIRECTION INPUT ;
    USE SIGNAL ;
    PORT
      LAYER M3 ;
        RECT  31.824 0 31.842 0.038 ;
    END
  END d[322]
  PIN d[323]
    DIRECTION INPUT ;
    USE SIGNAL ;
    PORT
      LAYER M5 ;
        RECT  31.92 0 31.944 0.084 ;
    END
  END d[323]
  PIN d[324]
    DIRECTION INPUT ;
    USE SIGNAL ;
    PORT
      LAYER M3 ;
        RECT  32.004 0 32.022 0.038 ;
    END
  END d[324]
  PIN d[325]
    DIRECTION INPUT ;
    USE SIGNAL ;
    PORT
      LAYER M5 ;
        RECT  32.112 0 32.136 0.084 ;
    END
  END d[325]
  PIN d[326]
    DIRECTION INPUT ;
    USE SIGNAL ;
    PORT
      LAYER M3 ;
        RECT  32.22 0 32.238 0.038 ;
    END
  END d[326]
  PIN d[327]
    DIRECTION INPUT ;
    USE SIGNAL ;
    PORT
      LAYER M5 ;
        RECT  32.304 0 32.328 0.084 ;
    END
  END d[327]
  PIN d[328]
    DIRECTION INPUT ;
    USE SIGNAL ;
    PORT
      LAYER M3 ;
        RECT  32.4 0 32.418 0.038 ;
    END
  END d[328]
  PIN d[329]
    DIRECTION INPUT ;
    USE SIGNAL ;
    PORT
      LAYER M5 ;
        RECT  32.496 0 32.52 0.084 ;
    END
  END d[329]
  PIN d[32]
    DIRECTION INPUT ;
    USE SIGNAL ;
    PORT
      LAYER M3 ;
        RECT  3.672 0 3.69 0.038 ;
    END
  END d[32]
  PIN d[330]
    DIRECTION INPUT ;
    USE SIGNAL ;
    PORT
      LAYER M3 ;
        RECT  32.58 0 32.598 0.038 ;
    END
  END d[330]
  PIN d[331]
    DIRECTION INPUT ;
    USE SIGNAL ;
    PORT
      LAYER M5 ;
        RECT  32.688 0 32.712 0.084 ;
    END
  END d[331]
  PIN d[332]
    DIRECTION INPUT ;
    USE SIGNAL ;
    PORT
      LAYER M3 ;
        RECT  32.796 0 32.814 0.038 ;
    END
  END d[332]
  PIN d[333]
    DIRECTION INPUT ;
    USE SIGNAL ;
    PORT
      LAYER M5 ;
        RECT  32.88 0 32.904 0.084 ;
    END
  END d[333]
  PIN d[334]
    DIRECTION INPUT ;
    USE SIGNAL ;
    PORT
      LAYER M3 ;
        RECT  32.976 0 32.994 0.038 ;
    END
  END d[334]
  PIN d[335]
    DIRECTION INPUT ;
    USE SIGNAL ;
    PORT
      LAYER M5 ;
        RECT  33.072 0 33.096 0.084 ;
    END
  END d[335]
  PIN d[336]
    DIRECTION INPUT ;
    USE SIGNAL ;
    PORT
      LAYER M3 ;
        RECT  33.156 0 33.174 0.038 ;
    END
  END d[336]
  PIN d[337]
    DIRECTION INPUT ;
    USE SIGNAL ;
    PORT
      LAYER M5 ;
        RECT  33.264 0 33.288 0.084 ;
    END
  END d[337]
  PIN d[338]
    DIRECTION INPUT ;
    USE SIGNAL ;
    PORT
      LAYER M3 ;
        RECT  33.372 0 33.39 0.038 ;
    END
  END d[338]
  PIN d[339]
    DIRECTION INPUT ;
    USE SIGNAL ;
    PORT
      LAYER M5 ;
        RECT  33.456 0 33.48 0.084 ;
    END
  END d[339]
  PIN d[33]
    DIRECTION INPUT ;
    USE SIGNAL ;
    PORT
      LAYER M5 ;
        RECT  3.792 0 3.816 0.084 ;
    END
  END d[33]
  PIN d[340]
    DIRECTION INPUT ;
    USE SIGNAL ;
    PORT
      LAYER M3 ;
        RECT  33.552 0 33.57 0.038 ;
    END
  END d[340]
  PIN d[341]
    DIRECTION INPUT ;
    USE SIGNAL ;
    PORT
      LAYER M5 ;
        RECT  33.648 0 33.672 0.084 ;
    END
  END d[341]
  PIN d[342]
    DIRECTION INPUT ;
    USE SIGNAL ;
    PORT
      LAYER M3 ;
        RECT  33.768 0 33.786 0.038 ;
    END
  END d[342]
  PIN d[343]
    DIRECTION INPUT ;
    USE SIGNAL ;
    PORT
      LAYER M5 ;
        RECT  33.84 0 33.864 0.084 ;
    END
  END d[343]
  PIN d[344]
    DIRECTION INPUT ;
    USE SIGNAL ;
    PORT
      LAYER M3 ;
        RECT  33.948 0 33.966 0.038 ;
    END
  END d[344]
  PIN d[345]
    DIRECTION INPUT ;
    USE SIGNAL ;
    PORT
      LAYER M5 ;
        RECT  34.032 0 34.056 0.084 ;
    END
  END d[345]
  PIN d[346]
    DIRECTION INPUT ;
    USE SIGNAL ;
    PORT
      LAYER M3 ;
        RECT  34.128 0 34.146 0.038 ;
    END
  END d[346]
  PIN d[347]
    DIRECTION INPUT ;
    USE SIGNAL ;
    PORT
      LAYER M5 ;
        RECT  34.224 0 34.248 0.084 ;
    END
  END d[347]
  PIN d[348]
    DIRECTION INPUT ;
    USE SIGNAL ;
    PORT
      LAYER M3 ;
        RECT  34.344 0 34.362 0.038 ;
    END
  END d[348]
  PIN d[349]
    DIRECTION INPUT ;
    USE SIGNAL ;
    PORT
      LAYER M5 ;
        RECT  34.416 0 34.44 0.084 ;
    END
  END d[349]
  PIN d[34]
    DIRECTION INPUT ;
    USE SIGNAL ;
    PORT
      LAYER M3 ;
        RECT  3.888 0 3.906 0.038 ;
    END
  END d[34]
  PIN d[350]
    DIRECTION INPUT ;
    USE SIGNAL ;
    PORT
      LAYER M3 ;
        RECT  34.524 0 34.542 0.038 ;
    END
  END d[350]
  PIN d[351]
    DIRECTION INPUT ;
    USE SIGNAL ;
    PORT
      LAYER M5 ;
        RECT  34.608 0 34.632 0.084 ;
    END
  END d[351]
  PIN d[352]
    DIRECTION INPUT ;
    USE SIGNAL ;
    PORT
      LAYER M3 ;
        RECT  34.74 0 34.758 0.038 ;
    END
  END d[352]
  PIN d[353]
    DIRECTION INPUT ;
    USE SIGNAL ;
    PORT
      LAYER M5 ;
        RECT  34.8 0 34.824 0.084 ;
    END
  END d[353]
  PIN d[354]
    DIRECTION INPUT ;
    USE SIGNAL ;
    PORT
      LAYER M3 ;
        RECT  34.92 0 34.938 0.038 ;
    END
  END d[354]
  PIN d[355]
    DIRECTION INPUT ;
    USE SIGNAL ;
    PORT
      LAYER M5 ;
        RECT  34.992 0 35.016 0.084 ;
    END
  END d[355]
  PIN d[356]
    DIRECTION INPUT ;
    USE SIGNAL ;
    PORT
      LAYER M3 ;
        RECT  35.1 0 35.118 0.038 ;
    END
  END d[356]
  PIN d[357]
    DIRECTION INPUT ;
    USE SIGNAL ;
    PORT
      LAYER M5 ;
        RECT  35.184 0 35.208 0.084 ;
    END
  END d[357]
  PIN d[358]
    DIRECTION INPUT ;
    USE SIGNAL ;
    PORT
      LAYER M3 ;
        RECT  35.316 0 35.334 0.038 ;
    END
  END d[358]
  PIN d[359]
    DIRECTION INPUT ;
    USE SIGNAL ;
    PORT
      LAYER M5 ;
        RECT  35.424 0 35.448 0.084 ;
    END
  END d[359]
  PIN d[35]
    DIRECTION INPUT ;
    USE SIGNAL ;
    PORT
      LAYER M5 ;
        RECT  3.984 0 4.008 0.084 ;
    END
  END d[35]
  PIN d[360]
    DIRECTION INPUT ;
    USE SIGNAL ;
    PORT
      LAYER M3 ;
        RECT  35.496 0 35.514 0.038 ;
    END
  END d[360]
  PIN d[361]
    DIRECTION INPUT ;
    USE SIGNAL ;
    PORT
      LAYER M5 ;
        RECT  35.616 0 35.64 0.084 ;
    END
  END d[361]
  PIN d[362]
    DIRECTION INPUT ;
    USE SIGNAL ;
    PORT
      LAYER M3 ;
        RECT  35.712 0 35.73 0.038 ;
    END
  END d[362]
  PIN d[363]
    DIRECTION INPUT ;
    USE SIGNAL ;
    PORT
      LAYER M5 ;
        RECT  35.808 0 35.832 0.084 ;
    END
  END d[363]
  PIN d[364]
    DIRECTION INPUT ;
    USE SIGNAL ;
    PORT
      LAYER M3 ;
        RECT  35.892 0 35.91 0.038 ;
    END
  END d[364]
  PIN d[365]
    DIRECTION INPUT ;
    USE SIGNAL ;
    PORT
      LAYER M5 ;
        RECT  36 0 36.024 0.084 ;
    END
  END d[365]
  PIN d[366]
    DIRECTION INPUT ;
    USE SIGNAL ;
    PORT
      LAYER M3 ;
        RECT  36.072 0 36.09 0.038 ;
    END
  END d[366]
  PIN d[367]
    DIRECTION INPUT ;
    USE SIGNAL ;
    PORT
      LAYER M5 ;
        RECT  36.192 0 36.216 0.084 ;
    END
  END d[367]
  PIN d[368]
    DIRECTION INPUT ;
    USE SIGNAL ;
    PORT
      LAYER M3 ;
        RECT  36.288 0 36.306 0.038 ;
    END
  END d[368]
  PIN d[369]
    DIRECTION INPUT ;
    USE SIGNAL ;
    PORT
      LAYER M5 ;
        RECT  36.384 0 36.408 0.084 ;
    END
  END d[369]
  PIN d[36]
    DIRECTION INPUT ;
    USE SIGNAL ;
    PORT
      LAYER M3 ;
        RECT  4.068 0 4.086 0.038 ;
    END
  END d[36]
  PIN d[370]
    DIRECTION INPUT ;
    USE SIGNAL ;
    PORT
      LAYER M3 ;
        RECT  36.468 0 36.486 0.038 ;
    END
  END d[370]
  PIN d[371]
    DIRECTION INPUT ;
    USE SIGNAL ;
    PORT
      LAYER M5 ;
        RECT  36.576 0 36.6 0.084 ;
    END
  END d[371]
  PIN d[372]
    DIRECTION INPUT ;
    USE SIGNAL ;
    PORT
      LAYER M3 ;
        RECT  36.648 0 36.666 0.038 ;
    END
  END d[372]
  PIN d[373]
    DIRECTION INPUT ;
    USE SIGNAL ;
    PORT
      LAYER M5 ;
        RECT  36.768 0 36.792 0.084 ;
    END
  END d[373]
  PIN d[374]
    DIRECTION INPUT ;
    USE SIGNAL ;
    PORT
      LAYER M3 ;
        RECT  36.864 0 36.882 0.038 ;
    END
  END d[374]
  PIN d[375]
    DIRECTION INPUT ;
    USE SIGNAL ;
    PORT
      LAYER M5 ;
        RECT  36.96 0 36.984 0.084 ;
    END
  END d[375]
  PIN d[376]
    DIRECTION INPUT ;
    USE SIGNAL ;
    PORT
      LAYER M3 ;
        RECT  37.044 0 37.062 0.038 ;
    END
  END d[376]
  PIN d[377]
    DIRECTION INPUT ;
    USE SIGNAL ;
    PORT
      LAYER M5 ;
        RECT  37.152 0 37.176 0.084 ;
    END
  END d[377]
  PIN d[378]
    DIRECTION INPUT ;
    USE SIGNAL ;
    PORT
      LAYER M3 ;
        RECT  37.26 0 37.278 0.038 ;
    END
  END d[378]
  PIN d[379]
    DIRECTION INPUT ;
    USE SIGNAL ;
    PORT
      LAYER M5 ;
        RECT  37.344 0 37.368 0.084 ;
    END
  END d[379]
  PIN d[37]
    DIRECTION INPUT ;
    USE SIGNAL ;
    PORT
      LAYER M5 ;
        RECT  4.176 0 4.2 0.084 ;
    END
  END d[37]
  PIN d[380]
    DIRECTION INPUT ;
    USE SIGNAL ;
    PORT
      LAYER M3 ;
        RECT  37.44 0 37.458 0.038 ;
    END
  END d[380]
  PIN d[381]
    DIRECTION INPUT ;
    USE SIGNAL ;
    PORT
      LAYER M5 ;
        RECT  37.536 0 37.56 0.084 ;
    END
  END d[381]
  PIN d[382]
    DIRECTION INPUT ;
    USE SIGNAL ;
    PORT
      LAYER M3 ;
        RECT  37.62 0 37.638 0.038 ;
    END
  END d[382]
  PIN d[383]
    DIRECTION INPUT ;
    USE SIGNAL ;
    PORT
      LAYER M5 ;
        RECT  37.728 0 37.752 0.084 ;
    END
  END d[383]
  PIN d[384]
    DIRECTION INPUT ;
    USE SIGNAL ;
    PORT
      LAYER M3 ;
        RECT  37.836 0 37.854 0.038 ;
    END
  END d[384]
  PIN d[385]
    DIRECTION INPUT ;
    USE SIGNAL ;
    PORT
      LAYER M5 ;
        RECT  37.92 0 37.944 0.084 ;
    END
  END d[385]
  PIN d[386]
    DIRECTION INPUT ;
    USE SIGNAL ;
    PORT
      LAYER M3 ;
        RECT  38.016 0 38.034 0.038 ;
    END
  END d[386]
  PIN d[387]
    DIRECTION INPUT ;
    USE SIGNAL ;
    PORT
      LAYER M5 ;
        RECT  38.112 0 38.136 0.084 ;
    END
  END d[387]
  PIN d[388]
    DIRECTION INPUT ;
    USE SIGNAL ;
    PORT
      LAYER M3 ;
        RECT  38.232 0 38.25 0.038 ;
    END
  END d[388]
  PIN d[389]
    DIRECTION INPUT ;
    USE SIGNAL ;
    PORT
      LAYER M5 ;
        RECT  38.304 0 38.328 0.084 ;
    END
  END d[389]
  PIN d[38]
    DIRECTION INPUT ;
    USE SIGNAL ;
    PORT
      LAYER M3 ;
        RECT  4.284 0 4.302 0.038 ;
    END
  END d[38]
  PIN d[390]
    DIRECTION INPUT ;
    USE SIGNAL ;
    PORT
      LAYER M3 ;
        RECT  38.412 0 38.43 0.038 ;
    END
  END d[390]
  PIN d[391]
    DIRECTION INPUT ;
    USE SIGNAL ;
    PORT
      LAYER M5 ;
        RECT  38.496 0 38.52 0.084 ;
    END
  END d[391]
  PIN d[392]
    DIRECTION INPUT ;
    USE SIGNAL ;
    PORT
      LAYER M3 ;
        RECT  38.592 0 38.61 0.038 ;
    END
  END d[392]
  PIN d[393]
    DIRECTION INPUT ;
    USE SIGNAL ;
    PORT
      LAYER M5 ;
        RECT  38.688 0 38.712 0.084 ;
    END
  END d[393]
  PIN d[394]
    DIRECTION INPUT ;
    USE SIGNAL ;
    PORT
      LAYER M3 ;
        RECT  38.808 0 38.826 0.038 ;
    END
  END d[394]
  PIN d[395]
    DIRECTION INPUT ;
    USE SIGNAL ;
    PORT
      LAYER M5 ;
        RECT  38.88 0 38.904 0.084 ;
    END
  END d[395]
  PIN d[396]
    DIRECTION INPUT ;
    USE SIGNAL ;
    PORT
      LAYER M3 ;
        RECT  38.988 0 39.006 0.038 ;
    END
  END d[396]
  PIN d[397]
    DIRECTION INPUT ;
    USE SIGNAL ;
    PORT
      LAYER M5 ;
        RECT  39.072 0 39.096 0.084 ;
    END
  END d[397]
  PIN d[398]
    DIRECTION INPUT ;
    USE SIGNAL ;
    PORT
      LAYER M3 ;
        RECT  39.204 0 39.222 0.038 ;
    END
  END d[398]
  PIN d[399]
    DIRECTION INPUT ;
    USE SIGNAL ;
    PORT
      LAYER M5 ;
        RECT  39.264 0 39.288 0.084 ;
    END
  END d[399]
  PIN d[39]
    DIRECTION INPUT ;
    USE SIGNAL ;
    PORT
      LAYER M5 ;
        RECT  4.368 0 4.392 0.084 ;
    END
  END d[39]
  PIN d[3]
    DIRECTION INPUT ;
    USE SIGNAL ;
    PORT
      LAYER M5 ;
        RECT  0.864 0 0.888 0.084 ;
    END
  END d[3]
  PIN d[400]
    DIRECTION INPUT ;
    USE SIGNAL ;
    PORT
      LAYER M3 ;
        RECT  39.384 0 39.402 0.038 ;
    END
  END d[400]
  PIN d[401]
    DIRECTION INPUT ;
    USE SIGNAL ;
    PORT
      LAYER M5 ;
        RECT  39.456 0 39.48 0.084 ;
    END
  END d[401]
  PIN d[402]
    DIRECTION INPUT ;
    USE SIGNAL ;
    PORT
      LAYER M3 ;
        RECT  39.564 0 39.582 0.038 ;
    END
  END d[402]
  PIN d[403]
    DIRECTION INPUT ;
    USE SIGNAL ;
    PORT
      LAYER M5 ;
        RECT  39.648 0 39.672 0.084 ;
    END
  END d[403]
  PIN d[404]
    DIRECTION INPUT ;
    USE SIGNAL ;
    PORT
      LAYER M3 ;
        RECT  39.78 0 39.798 0.038 ;
    END
  END d[404]
  PIN d[405]
    DIRECTION INPUT ;
    USE SIGNAL ;
    PORT
      LAYER M5 ;
        RECT  39.84 0 39.864 0.084 ;
    END
  END d[405]
  PIN d[406]
    DIRECTION INPUT ;
    USE SIGNAL ;
    PORT
      LAYER M3 ;
        RECT  39.96 0 39.978 0.038 ;
    END
  END d[406]
  PIN d[407]
    DIRECTION INPUT ;
    USE SIGNAL ;
    PORT
      LAYER M5 ;
        RECT  40.08 0 40.104 0.084 ;
    END
  END d[407]
  PIN d[408]
    DIRECTION INPUT ;
    USE SIGNAL ;
    PORT
      LAYER M3 ;
        RECT  40.14 0 40.158 0.038 ;
    END
  END d[408]
  PIN d[409]
    DIRECTION INPUT ;
    USE SIGNAL ;
    PORT
      LAYER M5 ;
        RECT  40.272 0 40.296 0.084 ;
    END
  END d[409]
  PIN d[40]
    DIRECTION INPUT ;
    USE SIGNAL ;
    PORT
      LAYER M3 ;
        RECT  4.464 0 4.482 0.038 ;
    END
  END d[40]
  PIN d[410]
    DIRECTION INPUT ;
    USE SIGNAL ;
    PORT
      LAYER M3 ;
        RECT  40.356 0 40.374 0.038 ;
    END
  END d[410]
  PIN d[411]
    DIRECTION INPUT ;
    USE SIGNAL ;
    PORT
      LAYER M5 ;
        RECT  40.464 0 40.488 0.084 ;
    END
  END d[411]
  PIN d[412]
    DIRECTION INPUT ;
    USE SIGNAL ;
    PORT
      LAYER M3 ;
        RECT  40.536 0 40.554 0.038 ;
    END
  END d[412]
  PIN d[413]
    DIRECTION INPUT ;
    USE SIGNAL ;
    PORT
      LAYER M5 ;
        RECT  40.656 0 40.68 0.084 ;
    END
  END d[413]
  PIN d[414]
    DIRECTION INPUT ;
    USE SIGNAL ;
    PORT
      LAYER M3 ;
        RECT  40.752 0 40.77 0.038 ;
    END
  END d[414]
  PIN d[415]
    DIRECTION INPUT ;
    USE SIGNAL ;
    PORT
      LAYER M5 ;
        RECT  40.848 0 40.872 0.084 ;
    END
  END d[415]
  PIN d[416]
    DIRECTION INPUT ;
    USE SIGNAL ;
    PORT
      LAYER M3 ;
        RECT  40.932 0 40.95 0.038 ;
    END
  END d[416]
  PIN d[417]
    DIRECTION INPUT ;
    USE SIGNAL ;
    PORT
      LAYER M5 ;
        RECT  41.04 0 41.064 0.084 ;
    END
  END d[417]
  PIN d[418]
    DIRECTION INPUT ;
    USE SIGNAL ;
    PORT
      LAYER M3 ;
        RECT  41.112 0 41.13 0.038 ;
    END
  END d[418]
  PIN d[419]
    DIRECTION INPUT ;
    USE SIGNAL ;
    PORT
      LAYER M5 ;
        RECT  41.232 0 41.256 0.084 ;
    END
  END d[419]
  PIN d[41]
    DIRECTION INPUT ;
    USE SIGNAL ;
    PORT
      LAYER M5 ;
        RECT  4.56 0 4.584 0.084 ;
    END
  END d[41]
  PIN d[420]
    DIRECTION INPUT ;
    USE SIGNAL ;
    PORT
      LAYER M3 ;
        RECT  41.328 0 41.346 0.038 ;
    END
  END d[420]
  PIN d[421]
    DIRECTION INPUT ;
    USE SIGNAL ;
    PORT
      LAYER M5 ;
        RECT  41.424 0 41.448 0.084 ;
    END
  END d[421]
  PIN d[422]
    DIRECTION INPUT ;
    USE SIGNAL ;
    PORT
      LAYER M3 ;
        RECT  41.508 0 41.526 0.038 ;
    END
  END d[422]
  PIN d[423]
    DIRECTION INPUT ;
    USE SIGNAL ;
    PORT
      LAYER M5 ;
        RECT  41.616 0 41.64 0.084 ;
    END
  END d[423]
  PIN d[424]
    DIRECTION INPUT ;
    USE SIGNAL ;
    PORT
      LAYER M3 ;
        RECT  41.724 0 41.742 0.038 ;
    END
  END d[424]
  PIN d[425]
    DIRECTION INPUT ;
    USE SIGNAL ;
    PORT
      LAYER M5 ;
        RECT  41.808 0 41.832 0.084 ;
    END
  END d[425]
  PIN d[426]
    DIRECTION INPUT ;
    USE SIGNAL ;
    PORT
      LAYER M3 ;
        RECT  41.904 0 41.922 0.038 ;
    END
  END d[426]
  PIN d[427]
    DIRECTION INPUT ;
    USE SIGNAL ;
    PORT
      LAYER M5 ;
        RECT  42 0 42.024 0.084 ;
    END
  END d[427]
  PIN d[428]
    DIRECTION INPUT ;
    USE SIGNAL ;
    PORT
      LAYER M3 ;
        RECT  42.084 0 42.102 0.038 ;
    END
  END d[428]
  PIN d[429]
    DIRECTION INPUT ;
    USE SIGNAL ;
    PORT
      LAYER M5 ;
        RECT  42.192 0 42.216 0.084 ;
    END
  END d[429]
  PIN d[42]
    DIRECTION INPUT ;
    USE SIGNAL ;
    PORT
      LAYER M3 ;
        RECT  4.644 0 4.662 0.038 ;
    END
  END d[42]
  PIN d[430]
    DIRECTION INPUT ;
    USE SIGNAL ;
    PORT
      LAYER M3 ;
        RECT  42.3 0 42.318 0.038 ;
    END
  END d[430]
  PIN d[431]
    DIRECTION INPUT ;
    USE SIGNAL ;
    PORT
      LAYER M5 ;
        RECT  42.384 0 42.408 0.084 ;
    END
  END d[431]
  PIN d[432]
    DIRECTION INPUT ;
    USE SIGNAL ;
    PORT
      LAYER M3 ;
        RECT  42.48 0 42.498 0.038 ;
    END
  END d[432]
  PIN d[433]
    DIRECTION INPUT ;
    USE SIGNAL ;
    PORT
      LAYER M5 ;
        RECT  42.576 0 42.6 0.084 ;
    END
  END d[433]
  PIN d[434]
    DIRECTION INPUT ;
    USE SIGNAL ;
    PORT
      LAYER M3 ;
        RECT  42.696 0 42.714 0.038 ;
    END
  END d[434]
  PIN d[435]
    DIRECTION INPUT ;
    USE SIGNAL ;
    PORT
      LAYER M5 ;
        RECT  42.768 0 42.792 0.084 ;
    END
  END d[435]
  PIN d[436]
    DIRECTION INPUT ;
    USE SIGNAL ;
    PORT
      LAYER M3 ;
        RECT  42.876 0 42.894 0.038 ;
    END
  END d[436]
  PIN d[437]
    DIRECTION INPUT ;
    USE SIGNAL ;
    PORT
      LAYER M5 ;
        RECT  42.96 0 42.984 0.084 ;
    END
  END d[437]
  PIN d[438]
    DIRECTION INPUT ;
    USE SIGNAL ;
    PORT
      LAYER M3 ;
        RECT  43.056 0 43.074 0.038 ;
    END
  END d[438]
  PIN d[439]
    DIRECTION INPUT ;
    USE SIGNAL ;
    PORT
      LAYER M5 ;
        RECT  43.152 0 43.176 0.084 ;
    END
  END d[439]
  PIN d[43]
    DIRECTION INPUT ;
    USE SIGNAL ;
    PORT
      LAYER M5 ;
        RECT  4.752 0 4.776 0.084 ;
    END
  END d[43]
  PIN d[440]
    DIRECTION INPUT ;
    USE SIGNAL ;
    PORT
      LAYER M3 ;
        RECT  43.272 0 43.29 0.038 ;
    END
  END d[440]
  PIN d[441]
    DIRECTION INPUT ;
    USE SIGNAL ;
    PORT
      LAYER M5 ;
        RECT  43.344 0 43.368 0.084 ;
    END
  END d[441]
  PIN d[442]
    DIRECTION INPUT ;
    USE SIGNAL ;
    PORT
      LAYER M3 ;
        RECT  43.452 0 43.47 0.038 ;
    END
  END d[442]
  PIN d[443]
    DIRECTION INPUT ;
    USE SIGNAL ;
    PORT
      LAYER M5 ;
        RECT  43.536 0 43.56 0.084 ;
    END
  END d[443]
  PIN d[444]
    DIRECTION INPUT ;
    USE SIGNAL ;
    PORT
      LAYER M3 ;
        RECT  43.632 0 43.65 0.038 ;
    END
  END d[444]
  PIN d[445]
    DIRECTION INPUT ;
    USE SIGNAL ;
    PORT
      LAYER M5 ;
        RECT  43.728 0 43.752 0.084 ;
    END
  END d[445]
  PIN d[446]
    DIRECTION INPUT ;
    USE SIGNAL ;
    PORT
      LAYER M3 ;
        RECT  43.848 0 43.866 0.038 ;
    END
  END d[446]
  PIN d[447]
    DIRECTION INPUT ;
    USE SIGNAL ;
    PORT
      LAYER M5 ;
        RECT  43.92 0 43.944 0.084 ;
    END
  END d[447]
  PIN d[448]
    DIRECTION INPUT ;
    USE SIGNAL ;
    PORT
      LAYER M3 ;
        RECT  44.028 0 44.046 0.038 ;
    END
  END d[448]
  PIN d[449]
    DIRECTION INPUT ;
    USE SIGNAL ;
    PORT
      LAYER M5 ;
        RECT  44.112 0 44.136 0.084 ;
    END
  END d[449]
  PIN d[44]
    DIRECTION INPUT ;
    USE SIGNAL ;
    PORT
      LAYER M3 ;
        RECT  4.86 0 4.878 0.038 ;
    END
  END d[44]
  PIN d[450]
    DIRECTION INPUT ;
    USE SIGNAL ;
    PORT
      LAYER M3 ;
        RECT  44.244 0 44.262 0.038 ;
    END
  END d[450]
  PIN d[451]
    DIRECTION INPUT ;
    USE SIGNAL ;
    PORT
      LAYER M5 ;
        RECT  44.304 0 44.328 0.084 ;
    END
  END d[451]
  PIN d[452]
    DIRECTION INPUT ;
    USE SIGNAL ;
    PORT
      LAYER M3 ;
        RECT  44.424 0 44.442 0.038 ;
    END
  END d[452]
  PIN d[453]
    DIRECTION INPUT ;
    USE SIGNAL ;
    PORT
      LAYER M5 ;
        RECT  44.496 0 44.52 0.084 ;
    END
  END d[453]
  PIN d[454]
    DIRECTION INPUT ;
    USE SIGNAL ;
    PORT
      LAYER M3 ;
        RECT  44.604 0 44.622 0.038 ;
    END
  END d[454]
  PIN d[455]
    DIRECTION INPUT ;
    USE SIGNAL ;
    PORT
      LAYER M5 ;
        RECT  44.736 0 44.76 0.084 ;
    END
  END d[455]
  PIN d[456]
    DIRECTION INPUT ;
    USE SIGNAL ;
    PORT
      LAYER M3 ;
        RECT  44.82 0 44.838 0.038 ;
    END
  END d[456]
  PIN d[457]
    DIRECTION INPUT ;
    USE SIGNAL ;
    PORT
      LAYER M5 ;
        RECT  44.928 0 44.952 0.084 ;
    END
  END d[457]
  PIN d[458]
    DIRECTION INPUT ;
    USE SIGNAL ;
    PORT
      LAYER M3 ;
        RECT  45 0 45.018 0.038 ;
    END
  END d[458]
  PIN d[459]
    DIRECTION INPUT ;
    USE SIGNAL ;
    PORT
      LAYER M5 ;
        RECT  45.12 0 45.144 0.084 ;
    END
  END d[459]
  PIN d[45]
    DIRECTION INPUT ;
    USE SIGNAL ;
    PORT
      LAYER M5 ;
        RECT  4.944 0 4.968 0.084 ;
    END
  END d[45]
  PIN d[460]
    DIRECTION INPUT ;
    USE SIGNAL ;
    PORT
      LAYER M3 ;
        RECT  45.216 0 45.234 0.038 ;
    END
  END d[460]
  PIN d[461]
    DIRECTION INPUT ;
    USE SIGNAL ;
    PORT
      LAYER M5 ;
        RECT  45.312 0 45.336 0.084 ;
    END
  END d[461]
  PIN d[462]
    DIRECTION INPUT ;
    USE SIGNAL ;
    PORT
      LAYER M3 ;
        RECT  45.396 0 45.414 0.038 ;
    END
  END d[462]
  PIN d[463]
    DIRECTION INPUT ;
    USE SIGNAL ;
    PORT
      LAYER M5 ;
        RECT  45.504 0 45.528 0.084 ;
    END
  END d[463]
  PIN d[464]
    DIRECTION INPUT ;
    USE SIGNAL ;
    PORT
      LAYER M3 ;
        RECT  45.576 0 45.594 0.038 ;
    END
  END d[464]
  PIN d[465]
    DIRECTION INPUT ;
    USE SIGNAL ;
    PORT
      LAYER M5 ;
        RECT  45.696 0 45.72 0.084 ;
    END
  END d[465]
  PIN d[466]
    DIRECTION INPUT ;
    USE SIGNAL ;
    PORT
      LAYER M3 ;
        RECT  45.792 0 45.81 0.038 ;
    END
  END d[466]
  PIN d[467]
    DIRECTION INPUT ;
    USE SIGNAL ;
    PORT
      LAYER M5 ;
        RECT  45.888 0 45.912 0.084 ;
    END
  END d[467]
  PIN d[468]
    DIRECTION INPUT ;
    USE SIGNAL ;
    PORT
      LAYER M3 ;
        RECT  45.972 0 45.99 0.038 ;
    END
  END d[468]
  PIN d[469]
    DIRECTION INPUT ;
    USE SIGNAL ;
    PORT
      LAYER M5 ;
        RECT  46.08 0 46.104 0.084 ;
    END
  END d[469]
  PIN d[46]
    DIRECTION INPUT ;
    USE SIGNAL ;
    PORT
      LAYER M3 ;
        RECT  5.04 0 5.058 0.038 ;
    END
  END d[46]
  PIN d[470]
    DIRECTION INPUT ;
    USE SIGNAL ;
    PORT
      LAYER M3 ;
        RECT  46.188 0 46.206 0.038 ;
    END
  END d[470]
  PIN d[471]
    DIRECTION INPUT ;
    USE SIGNAL ;
    PORT
      LAYER M5 ;
        RECT  46.272 0 46.296 0.084 ;
    END
  END d[471]
  PIN d[472]
    DIRECTION INPUT ;
    USE SIGNAL ;
    PORT
      LAYER M3 ;
        RECT  46.368 0 46.386 0.038 ;
    END
  END d[472]
  PIN d[473]
    DIRECTION INPUT ;
    USE SIGNAL ;
    PORT
      LAYER M5 ;
        RECT  46.464 0 46.488 0.084 ;
    END
  END d[473]
  PIN d[474]
    DIRECTION INPUT ;
    USE SIGNAL ;
    PORT
      LAYER M3 ;
        RECT  46.548 0 46.566 0.038 ;
    END
  END d[474]
  PIN d[475]
    DIRECTION INPUT ;
    USE SIGNAL ;
    PORT
      LAYER M5 ;
        RECT  46.656 0 46.68 0.084 ;
    END
  END d[475]
  PIN d[476]
    DIRECTION INPUT ;
    USE SIGNAL ;
    PORT
      LAYER M3 ;
        RECT  46.764 0 46.782 0.038 ;
    END
  END d[476]
  PIN d[477]
    DIRECTION INPUT ;
    USE SIGNAL ;
    PORT
      LAYER M5 ;
        RECT  46.848 0 46.872 0.084 ;
    END
  END d[477]
  PIN d[478]
    DIRECTION INPUT ;
    USE SIGNAL ;
    PORT
      LAYER M3 ;
        RECT  46.944 0 46.962 0.038 ;
    END
  END d[478]
  PIN d[479]
    DIRECTION INPUT ;
    USE SIGNAL ;
    PORT
      LAYER M5 ;
        RECT  47.04 0 47.064 0.084 ;
    END
  END d[479]
  PIN d[47]
    DIRECTION INPUT ;
    USE SIGNAL ;
    PORT
      LAYER M5 ;
        RECT  5.136 0 5.16 0.084 ;
    END
  END d[47]
  PIN d[480]
    DIRECTION INPUT ;
    USE SIGNAL ;
    PORT
      LAYER M3 ;
        RECT  47.124 0 47.142 0.038 ;
    END
  END d[480]
  PIN d[481]
    DIRECTION INPUT ;
    USE SIGNAL ;
    PORT
      LAYER M5 ;
        RECT  47.232 0 47.256 0.084 ;
    END
  END d[481]
  PIN d[482]
    DIRECTION INPUT ;
    USE SIGNAL ;
    PORT
      LAYER M3 ;
        RECT  47.34 0 47.358 0.038 ;
    END
  END d[482]
  PIN d[483]
    DIRECTION INPUT ;
    USE SIGNAL ;
    PORT
      LAYER M5 ;
        RECT  47.424 0 47.448 0.084 ;
    END
  END d[483]
  PIN d[484]
    DIRECTION INPUT ;
    USE SIGNAL ;
    PORT
      LAYER M3 ;
        RECT  47.52 0 47.538 0.038 ;
    END
  END d[484]
  PIN d[485]
    DIRECTION INPUT ;
    USE SIGNAL ;
    PORT
      LAYER M5 ;
        RECT  47.616 0 47.64 0.084 ;
    END
  END d[485]
  PIN d[486]
    DIRECTION INPUT ;
    USE SIGNAL ;
    PORT
      LAYER M3 ;
        RECT  47.736 0 47.754 0.038 ;
    END
  END d[486]
  PIN d[487]
    DIRECTION INPUT ;
    USE SIGNAL ;
    PORT
      LAYER M5 ;
        RECT  47.808 0 47.832 0.084 ;
    END
  END d[487]
  PIN d[488]
    DIRECTION INPUT ;
    USE SIGNAL ;
    PORT
      LAYER M3 ;
        RECT  47.916 0 47.934 0.038 ;
    END
  END d[488]
  PIN d[489]
    DIRECTION INPUT ;
    USE SIGNAL ;
    PORT
      LAYER M5 ;
        RECT  48 0 48.024 0.084 ;
    END
  END d[489]
  PIN d[48]
    DIRECTION INPUT ;
    USE SIGNAL ;
    PORT
      LAYER M3 ;
        RECT  5.22 0 5.238 0.038 ;
    END
  END d[48]
  PIN d[490]
    DIRECTION INPUT ;
    USE SIGNAL ;
    PORT
      LAYER M3 ;
        RECT  48.096 0 48.114 0.038 ;
    END
  END d[490]
  PIN d[491]
    DIRECTION INPUT ;
    USE SIGNAL ;
    PORT
      LAYER M5 ;
        RECT  48.192 0 48.216 0.084 ;
    END
  END d[491]
  PIN d[492]
    DIRECTION INPUT ;
    USE SIGNAL ;
    PORT
      LAYER M3 ;
        RECT  48.312 0 48.33 0.038 ;
    END
  END d[492]
  PIN d[493]
    DIRECTION INPUT ;
    USE SIGNAL ;
    PORT
      LAYER M5 ;
        RECT  48.384 0 48.408 0.084 ;
    END
  END d[493]
  PIN d[494]
    DIRECTION INPUT ;
    USE SIGNAL ;
    PORT
      LAYER M3 ;
        RECT  48.492 0 48.51 0.038 ;
    END
  END d[494]
  PIN d[495]
    DIRECTION INPUT ;
    USE SIGNAL ;
    PORT
      LAYER M5 ;
        RECT  48.576 0 48.6 0.084 ;
    END
  END d[495]
  PIN d[496]
    DIRECTION INPUT ;
    USE SIGNAL ;
    PORT
      LAYER M3 ;
        RECT  48.708 0 48.726 0.038 ;
    END
  END d[496]
  PIN d[497]
    DIRECTION INPUT ;
    USE SIGNAL ;
    PORT
      LAYER M5 ;
        RECT  48.768 0 48.792 0.084 ;
    END
  END d[497]
  PIN d[498]
    DIRECTION INPUT ;
    USE SIGNAL ;
    PORT
      LAYER M3 ;
        RECT  48.888 0 48.906 0.038 ;
    END
  END d[498]
  PIN d[499]
    DIRECTION INPUT ;
    USE SIGNAL ;
    PORT
      LAYER M5 ;
        RECT  48.96 0 48.984 0.084 ;
    END
  END d[499]
  PIN d[49]
    DIRECTION INPUT ;
    USE SIGNAL ;
    PORT
      LAYER M5 ;
        RECT  5.328 0 5.352 0.084 ;
    END
  END d[49]
  PIN d[4]
    DIRECTION INPUT ;
    USE SIGNAL ;
    PORT
      LAYER M3 ;
        RECT  0.972 0 0.99 0.038 ;
    END
  END d[4]
  PIN d[500]
    DIRECTION INPUT ;
    USE SIGNAL ;
    PORT
      LAYER M3 ;
        RECT  49.068 0 49.086 0.038 ;
    END
  END d[500]
  PIN d[501]
    DIRECTION INPUT ;
    USE SIGNAL ;
    PORT
      LAYER M5 ;
        RECT  49.152 0 49.176 0.084 ;
    END
  END d[501]
  PIN d[502]
    DIRECTION INPUT ;
    USE SIGNAL ;
    PORT
      LAYER M3 ;
        RECT  49.284 0 49.302 0.038 ;
    END
  END d[502]
  PIN d[503]
    DIRECTION INPUT ;
    USE SIGNAL ;
    PORT
      LAYER M5 ;
        RECT  49.392 0 49.416 0.084 ;
    END
  END d[503]
  PIN d[504]
    DIRECTION INPUT ;
    USE SIGNAL ;
    PORT
      LAYER M3 ;
        RECT  49.464 0 49.482 0.038 ;
    END
  END d[504]
  PIN d[505]
    DIRECTION INPUT ;
    USE SIGNAL ;
    PORT
      LAYER M5 ;
        RECT  49.584 0 49.608 0.084 ;
    END
  END d[505]
  PIN d[506]
    DIRECTION INPUT ;
    USE SIGNAL ;
    PORT
      LAYER M3 ;
        RECT  49.68 0 49.698 0.038 ;
    END
  END d[506]
  PIN d[507]
    DIRECTION INPUT ;
    USE SIGNAL ;
    PORT
      LAYER M5 ;
        RECT  49.776 0 49.8 0.084 ;
    END
  END d[507]
  PIN d[508]
    DIRECTION INPUT ;
    USE SIGNAL ;
    PORT
      LAYER M3 ;
        RECT  49.86 0 49.878 0.038 ;
    END
  END d[508]
  PIN d[509]
    DIRECTION INPUT ;
    USE SIGNAL ;
    PORT
      LAYER M5 ;
        RECT  49.968 0 49.992 0.084 ;
    END
  END d[509]
  PIN d[50]
    DIRECTION INPUT ;
    USE SIGNAL ;
    PORT
      LAYER M3 ;
        RECT  5.436 0 5.454 0.038 ;
    END
  END d[50]
  PIN d[510]
    DIRECTION INPUT ;
    USE SIGNAL ;
    PORT
      LAYER M3 ;
        RECT  50.04 0 50.058 0.038 ;
    END
  END d[510]
  PIN d[511]
    DIRECTION INPUT ;
    USE SIGNAL ;
    PORT
      LAYER M5 ;
        RECT  50.16 0 50.184 0.084 ;
    END
  END d[511]
  PIN d[512]
    DIRECTION INPUT ;
    USE SIGNAL ;
    PORT
      LAYER M3 ;
        RECT  50.256 0 50.274 0.038 ;
    END
  END d[512]
  PIN d[513]
    DIRECTION INPUT ;
    USE SIGNAL ;
    PORT
      LAYER M5 ;
        RECT  50.352 0 50.376 0.084 ;
    END
  END d[513]
  PIN d[51]
    DIRECTION INPUT ;
    USE SIGNAL ;
    PORT
      LAYER M5 ;
        RECT  5.52 0 5.544 0.084 ;
    END
  END d[51]
  PIN d[52]
    DIRECTION INPUT ;
    USE SIGNAL ;
    PORT
      LAYER M3 ;
        RECT  5.616 0 5.634 0.038 ;
    END
  END d[52]
  PIN d[53]
    DIRECTION INPUT ;
    USE SIGNAL ;
    PORT
      LAYER M5 ;
        RECT  5.712 0 5.736 0.084 ;
    END
  END d[53]
  PIN d[54]
    DIRECTION INPUT ;
    USE SIGNAL ;
    PORT
      LAYER M3 ;
        RECT  5.832 0 5.85 0.038 ;
    END
  END d[54]
  PIN d[55]
    DIRECTION INPUT ;
    USE SIGNAL ;
    PORT
      LAYER M5 ;
        RECT  5.904 0 5.928 0.084 ;
    END
  END d[55]
  PIN d[56]
    DIRECTION INPUT ;
    USE SIGNAL ;
    PORT
      LAYER M3 ;
        RECT  6.012 0 6.03 0.038 ;
    END
  END d[56]
  PIN d[57]
    DIRECTION INPUT ;
    USE SIGNAL ;
    PORT
      LAYER M5 ;
        RECT  6.096 0 6.12 0.084 ;
    END
  END d[57]
  PIN d[58]
    DIRECTION INPUT ;
    USE SIGNAL ;
    PORT
      LAYER M3 ;
        RECT  6.192 0 6.21 0.038 ;
    END
  END d[58]
  PIN d[59]
    DIRECTION INPUT ;
    USE SIGNAL ;
    PORT
      LAYER M5 ;
        RECT  6.288 0 6.312 0.084 ;
    END
  END d[59]
  PIN d[5]
    DIRECTION INPUT ;
    USE SIGNAL ;
    PORT
      LAYER M5 ;
        RECT  1.056 0 1.08 0.084 ;
    END
  END d[5]
  PIN d[60]
    DIRECTION INPUT ;
    USE SIGNAL ;
    PORT
      LAYER M3 ;
        RECT  6.408 0 6.426 0.038 ;
    END
  END d[60]
  PIN d[61]
    DIRECTION INPUT ;
    USE SIGNAL ;
    PORT
      LAYER M5 ;
        RECT  6.48 0 6.504 0.084 ;
    END
  END d[61]
  PIN d[62]
    DIRECTION INPUT ;
    USE SIGNAL ;
    PORT
      LAYER M3 ;
        RECT  6.588 0 6.606 0.038 ;
    END
  END d[62]
  PIN d[63]
    DIRECTION INPUT ;
    USE SIGNAL ;
    PORT
      LAYER M5 ;
        RECT  6.672 0 6.696 0.084 ;
    END
  END d[63]
  PIN d[64]
    DIRECTION INPUT ;
    USE SIGNAL ;
    PORT
      LAYER M3 ;
        RECT  6.804 0 6.822 0.038 ;
    END
  END d[64]
  PIN d[65]
    DIRECTION INPUT ;
    USE SIGNAL ;
    PORT
      LAYER M5 ;
        RECT  6.864 0 6.888 0.084 ;
    END
  END d[65]
  PIN d[66]
    DIRECTION INPUT ;
    USE SIGNAL ;
    PORT
      LAYER M3 ;
        RECT  6.984 0 7.002 0.038 ;
    END
  END d[66]
  PIN d[67]
    DIRECTION INPUT ;
    USE SIGNAL ;
    PORT
      LAYER M5 ;
        RECT  7.056 0 7.08 0.084 ;
    END
  END d[67]
  PIN d[68]
    DIRECTION INPUT ;
    USE SIGNAL ;
    PORT
      LAYER M3 ;
        RECT  7.164 0 7.182 0.038 ;
    END
  END d[68]
  PIN d[69]
    DIRECTION INPUT ;
    USE SIGNAL ;
    PORT
      LAYER M5 ;
        RECT  7.248 0 7.272 0.084 ;
    END
  END d[69]
  PIN d[6]
    DIRECTION INPUT ;
    USE SIGNAL ;
    PORT
      LAYER M3 ;
        RECT  1.152 0 1.17 0.038 ;
    END
  END d[6]
  PIN d[70]
    DIRECTION INPUT ;
    USE SIGNAL ;
    PORT
      LAYER M3 ;
        RECT  7.38 0 7.398 0.038 ;
    END
  END d[70]
  PIN d[71]
    DIRECTION INPUT ;
    USE SIGNAL ;
    PORT
      LAYER M5 ;
        RECT  7.488 0 7.512 0.084 ;
    END
  END d[71]
  PIN d[72]
    DIRECTION INPUT ;
    USE SIGNAL ;
    PORT
      LAYER M3 ;
        RECT  7.56 0 7.578 0.038 ;
    END
  END d[72]
  PIN d[73]
    DIRECTION INPUT ;
    USE SIGNAL ;
    PORT
      LAYER M5 ;
        RECT  7.68 0 7.704 0.084 ;
    END
  END d[73]
  PIN d[74]
    DIRECTION INPUT ;
    USE SIGNAL ;
    PORT
      LAYER M3 ;
        RECT  7.776 0 7.794 0.038 ;
    END
  END d[74]
  PIN d[75]
    DIRECTION INPUT ;
    USE SIGNAL ;
    PORT
      LAYER M5 ;
        RECT  7.872 0 7.896 0.084 ;
    END
  END d[75]
  PIN d[76]
    DIRECTION INPUT ;
    USE SIGNAL ;
    PORT
      LAYER M3 ;
        RECT  7.956 0 7.974 0.038 ;
    END
  END d[76]
  PIN d[77]
    DIRECTION INPUT ;
    USE SIGNAL ;
    PORT
      LAYER M5 ;
        RECT  8.064 0 8.088 0.084 ;
    END
  END d[77]
  PIN d[78]
    DIRECTION INPUT ;
    USE SIGNAL ;
    PORT
      LAYER M3 ;
        RECT  8.136 0 8.154 0.038 ;
    END
  END d[78]
  PIN d[79]
    DIRECTION INPUT ;
    USE SIGNAL ;
    PORT
      LAYER M5 ;
        RECT  8.256 0 8.28 0.084 ;
    END
  END d[79]
  PIN d[7]
    DIRECTION INPUT ;
    USE SIGNAL ;
    PORT
      LAYER M5 ;
        RECT  1.248 0 1.272 0.084 ;
    END
  END d[7]
  PIN d[80]
    DIRECTION INPUT ;
    USE SIGNAL ;
    PORT
      LAYER M3 ;
        RECT  8.352 0 8.37 0.038 ;
    END
  END d[80]
  PIN d[81]
    DIRECTION INPUT ;
    USE SIGNAL ;
    PORT
      LAYER M5 ;
        RECT  8.448 0 8.472 0.084 ;
    END
  END d[81]
  PIN d[82]
    DIRECTION INPUT ;
    USE SIGNAL ;
    PORT
      LAYER M3 ;
        RECT  8.532 0 8.55 0.038 ;
    END
  END d[82]
  PIN d[83]
    DIRECTION INPUT ;
    USE SIGNAL ;
    PORT
      LAYER M5 ;
        RECT  8.64 0 8.664 0.084 ;
    END
  END d[83]
  PIN d[84]
    DIRECTION INPUT ;
    USE SIGNAL ;
    PORT
      LAYER M3 ;
        RECT  8.712 0 8.73 0.038 ;
    END
  END d[84]
  PIN d[85]
    DIRECTION INPUT ;
    USE SIGNAL ;
    PORT
      LAYER M5 ;
        RECT  8.832 0 8.856 0.084 ;
    END
  END d[85]
  PIN d[86]
    DIRECTION INPUT ;
    USE SIGNAL ;
    PORT
      LAYER M3 ;
        RECT  8.928 0 8.946 0.038 ;
    END
  END d[86]
  PIN d[87]
    DIRECTION INPUT ;
    USE SIGNAL ;
    PORT
      LAYER M5 ;
        RECT  9.024 0 9.048 0.084 ;
    END
  END d[87]
  PIN d[88]
    DIRECTION INPUT ;
    USE SIGNAL ;
    PORT
      LAYER M3 ;
        RECT  9.108 0 9.126 0.038 ;
    END
  END d[88]
  PIN d[89]
    DIRECTION INPUT ;
    USE SIGNAL ;
    PORT
      LAYER M5 ;
        RECT  9.216 0 9.24 0.084 ;
    END
  END d[89]
  PIN d[8]
    DIRECTION INPUT ;
    USE SIGNAL ;
    PORT
      LAYER M3 ;
        RECT  1.368 0 1.386 0.038 ;
    END
  END d[8]
  PIN d[90]
    DIRECTION INPUT ;
    USE SIGNAL ;
    PORT
      LAYER M3 ;
        RECT  9.324 0 9.342 0.038 ;
    END
  END d[90]
  PIN d[91]
    DIRECTION INPUT ;
    USE SIGNAL ;
    PORT
      LAYER M5 ;
        RECT  9.408 0 9.432 0.084 ;
    END
  END d[91]
  PIN d[92]
    DIRECTION INPUT ;
    USE SIGNAL ;
    PORT
      LAYER M3 ;
        RECT  9.504 0 9.522 0.038 ;
    END
  END d[92]
  PIN d[93]
    DIRECTION INPUT ;
    USE SIGNAL ;
    PORT
      LAYER M5 ;
        RECT  9.6 0 9.624 0.084 ;
    END
  END d[93]
  PIN d[94]
    DIRECTION INPUT ;
    USE SIGNAL ;
    PORT
      LAYER M3 ;
        RECT  9.684 0 9.702 0.038 ;
    END
  END d[94]
  PIN d[95]
    DIRECTION INPUT ;
    USE SIGNAL ;
    PORT
      LAYER M5 ;
        RECT  9.792 0 9.816 0.084 ;
    END
  END d[95]
  PIN d[96]
    DIRECTION INPUT ;
    USE SIGNAL ;
    PORT
      LAYER M3 ;
        RECT  9.9 0 9.918 0.038 ;
    END
  END d[96]
  PIN d[97]
    DIRECTION INPUT ;
    USE SIGNAL ;
    PORT
      LAYER M5 ;
        RECT  9.984 0 10.008 0.084 ;
    END
  END d[97]
  PIN d[98]
    DIRECTION INPUT ;
    USE SIGNAL ;
    PORT
      LAYER M3 ;
        RECT  10.08 0 10.098 0.038 ;
    END
  END d[98]
  PIN d[99]
    DIRECTION INPUT ;
    USE SIGNAL ;
    PORT
      LAYER M5 ;
        RECT  10.176 0 10.2 0.084 ;
    END
  END d[99]
  PIN d[9]
    DIRECTION INPUT ;
    USE SIGNAL ;
    PORT
      LAYER M5 ;
        RECT  1.44 0 1.464 0.084 ;
    END
  END d[9]
  PIN q[0]
    DIRECTION OUTPUT ;
    USE SIGNAL ;
    PORT
      LAYER M3 ;
        RECT  0.576 51.802 0.594 51.84 ;
    END
  END q[0]
  PIN q[100]
    DIRECTION OUTPUT ;
    USE SIGNAL ;
    PORT
      LAYER M3 ;
        RECT  10.44 51.802 10.458 51.84 ;
    END
  END q[100]
  PIN q[101]
    DIRECTION OUTPUT ;
    USE SIGNAL ;
    PORT
      LAYER M5 ;
        RECT  10.56 51.756 10.584 51.84 ;
    END
  END q[101]
  PIN q[102]
    DIRECTION OUTPUT ;
    USE SIGNAL ;
    PORT
      LAYER M3 ;
        RECT  10.656 51.802 10.674 51.84 ;
    END
  END q[102]
  PIN q[103]
    DIRECTION OUTPUT ;
    USE SIGNAL ;
    PORT
      LAYER M5 ;
        RECT  10.752 51.756 10.776 51.84 ;
    END
  END q[103]
  PIN q[104]
    DIRECTION OUTPUT ;
    USE SIGNAL ;
    PORT
      LAYER M3 ;
        RECT  10.836 51.802 10.854 51.84 ;
    END
  END q[104]
  PIN q[105]
    DIRECTION OUTPUT ;
    USE SIGNAL ;
    PORT
      LAYER M5 ;
        RECT  10.944 51.756 10.968 51.84 ;
    END
  END q[105]
  PIN q[106]
    DIRECTION OUTPUT ;
    USE SIGNAL ;
    PORT
      LAYER M3 ;
        RECT  11.052 51.802 11.07 51.84 ;
    END
  END q[106]
  PIN q[107]
    DIRECTION OUTPUT ;
    USE SIGNAL ;
    PORT
      LAYER M5 ;
        RECT  11.136 51.756 11.16 51.84 ;
    END
  END q[107]
  PIN q[108]
    DIRECTION OUTPUT ;
    USE SIGNAL ;
    PORT
      LAYER M3 ;
        RECT  11.232 51.802 11.25 51.84 ;
    END
  END q[108]
  PIN q[109]
    DIRECTION OUTPUT ;
    USE SIGNAL ;
    PORT
      LAYER M5 ;
        RECT  11.328 51.756 11.352 51.84 ;
    END
  END q[109]
  PIN q[10]
    DIRECTION OUTPUT ;
    USE SIGNAL ;
    PORT
      LAYER M3 ;
        RECT  1.584 51.802 1.602 51.84 ;
    END
  END q[10]
  PIN q[110]
    DIRECTION OUTPUT ;
    USE SIGNAL ;
    PORT
      LAYER M3 ;
        RECT  11.448 51.802 11.466 51.84 ;
    END
  END q[110]
  PIN q[111]
    DIRECTION OUTPUT ;
    USE SIGNAL ;
    PORT
      LAYER M5 ;
        RECT  11.52 51.756 11.544 51.84 ;
    END
  END q[111]
  PIN q[112]
    DIRECTION OUTPUT ;
    USE SIGNAL ;
    PORT
      LAYER M3 ;
        RECT  11.628 51.802 11.646 51.84 ;
    END
  END q[112]
  PIN q[113]
    DIRECTION OUTPUT ;
    USE SIGNAL ;
    PORT
      LAYER M5 ;
        RECT  11.76 51.756 11.784 51.84 ;
    END
  END q[113]
  PIN q[114]
    DIRECTION OUTPUT ;
    USE SIGNAL ;
    PORT
      LAYER M3 ;
        RECT  11.844 51.802 11.862 51.84 ;
    END
  END q[114]
  PIN q[115]
    DIRECTION OUTPUT ;
    USE SIGNAL ;
    PORT
      LAYER M5 ;
        RECT  11.952 51.756 11.976 51.84 ;
    END
  END q[115]
  PIN q[116]
    DIRECTION OUTPUT ;
    USE SIGNAL ;
    PORT
      LAYER M3 ;
        RECT  12.024 51.802 12.042 51.84 ;
    END
  END q[116]
  PIN q[117]
    DIRECTION OUTPUT ;
    USE SIGNAL ;
    PORT
      LAYER M5 ;
        RECT  12.144 51.756 12.168 51.84 ;
    END
  END q[117]
  PIN q[118]
    DIRECTION OUTPUT ;
    USE SIGNAL ;
    PORT
      LAYER M3 ;
        RECT  12.24 51.802 12.258 51.84 ;
    END
  END q[118]
  PIN q[119]
    DIRECTION OUTPUT ;
    USE SIGNAL ;
    PORT
      LAYER M5 ;
        RECT  12.336 51.756 12.36 51.84 ;
    END
  END q[119]
  PIN q[11]
    DIRECTION OUTPUT ;
    USE SIGNAL ;
    PORT
      LAYER M5 ;
        RECT  1.68 51.756 1.704 51.84 ;
    END
  END q[11]
  PIN q[120]
    DIRECTION OUTPUT ;
    USE SIGNAL ;
    PORT
      LAYER M3 ;
        RECT  12.42 51.802 12.438 51.84 ;
    END
  END q[120]
  PIN q[121]
    DIRECTION OUTPUT ;
    USE SIGNAL ;
    PORT
      LAYER M5 ;
        RECT  12.528 51.756 12.552 51.84 ;
    END
  END q[121]
  PIN q[122]
    DIRECTION OUTPUT ;
    USE SIGNAL ;
    PORT
      LAYER M3 ;
        RECT  12.636 51.802 12.654 51.84 ;
    END
  END q[122]
  PIN q[123]
    DIRECTION OUTPUT ;
    USE SIGNAL ;
    PORT
      LAYER M5 ;
        RECT  12.72 51.756 12.744 51.84 ;
    END
  END q[123]
  PIN q[124]
    DIRECTION OUTPUT ;
    USE SIGNAL ;
    PORT
      LAYER M3 ;
        RECT  12.816 51.802 12.834 51.84 ;
    END
  END q[124]
  PIN q[125]
    DIRECTION OUTPUT ;
    USE SIGNAL ;
    PORT
      LAYER M5 ;
        RECT  12.912 51.756 12.936 51.84 ;
    END
  END q[125]
  PIN q[126]
    DIRECTION OUTPUT ;
    USE SIGNAL ;
    PORT
      LAYER M3 ;
        RECT  13.032 51.802 13.05 51.84 ;
    END
  END q[126]
  PIN q[127]
    DIRECTION OUTPUT ;
    USE SIGNAL ;
    PORT
      LAYER M5 ;
        RECT  13.104 51.756 13.128 51.84 ;
    END
  END q[127]
  PIN q[128]
    DIRECTION OUTPUT ;
    USE SIGNAL ;
    PORT
      LAYER M3 ;
        RECT  13.212 51.802 13.23 51.84 ;
    END
  END q[128]
  PIN q[129]
    DIRECTION OUTPUT ;
    USE SIGNAL ;
    PORT
      LAYER M5 ;
        RECT  13.296 51.756 13.32 51.84 ;
    END
  END q[129]
  PIN q[12]
    DIRECTION OUTPUT ;
    USE SIGNAL ;
    PORT
      LAYER M3 ;
        RECT  1.764 51.802 1.782 51.84 ;
    END
  END q[12]
  PIN q[130]
    DIRECTION OUTPUT ;
    USE SIGNAL ;
    PORT
      LAYER M3 ;
        RECT  13.428 51.802 13.446 51.84 ;
    END
  END q[130]
  PIN q[131]
    DIRECTION OUTPUT ;
    USE SIGNAL ;
    PORT
      LAYER M5 ;
        RECT  13.536 51.756 13.56 51.84 ;
    END
  END q[131]
  PIN q[132]
    DIRECTION OUTPUT ;
    USE SIGNAL ;
    PORT
      LAYER M3 ;
        RECT  13.608 51.802 13.626 51.84 ;
    END
  END q[132]
  PIN q[133]
    DIRECTION OUTPUT ;
    USE SIGNAL ;
    PORT
      LAYER M5 ;
        RECT  13.728 51.756 13.752 51.84 ;
    END
  END q[133]
  PIN q[134]
    DIRECTION OUTPUT ;
    USE SIGNAL ;
    PORT
      LAYER M3 ;
        RECT  13.824 51.802 13.842 51.84 ;
    END
  END q[134]
  PIN q[135]
    DIRECTION OUTPUT ;
    USE SIGNAL ;
    PORT
      LAYER M5 ;
        RECT  13.92 51.756 13.944 51.84 ;
    END
  END q[135]
  PIN q[136]
    DIRECTION OUTPUT ;
    USE SIGNAL ;
    PORT
      LAYER M3 ;
        RECT  14.004 51.802 14.022 51.84 ;
    END
  END q[136]
  PIN q[137]
    DIRECTION OUTPUT ;
    USE SIGNAL ;
    PORT
      LAYER M5 ;
        RECT  14.112 51.756 14.136 51.84 ;
    END
  END q[137]
  PIN q[138]
    DIRECTION OUTPUT ;
    USE SIGNAL ;
    PORT
      LAYER M3 ;
        RECT  14.22 51.802 14.238 51.84 ;
    END
  END q[138]
  PIN q[139]
    DIRECTION OUTPUT ;
    USE SIGNAL ;
    PORT
      LAYER M5 ;
        RECT  14.304 51.756 14.328 51.84 ;
    END
  END q[139]
  PIN q[13]
    DIRECTION OUTPUT ;
    USE SIGNAL ;
    PORT
      LAYER M5 ;
        RECT  1.872 51.756 1.896 51.84 ;
    END
  END q[13]
  PIN q[140]
    DIRECTION OUTPUT ;
    USE SIGNAL ;
    PORT
      LAYER M3 ;
        RECT  14.4 51.802 14.418 51.84 ;
    END
  END q[140]
  PIN q[141]
    DIRECTION OUTPUT ;
    USE SIGNAL ;
    PORT
      LAYER M5 ;
        RECT  14.496 51.756 14.52 51.84 ;
    END
  END q[141]
  PIN q[142]
    DIRECTION OUTPUT ;
    USE SIGNAL ;
    PORT
      LAYER M3 ;
        RECT  14.616 51.802 14.634 51.84 ;
    END
  END q[142]
  PIN q[143]
    DIRECTION OUTPUT ;
    USE SIGNAL ;
    PORT
      LAYER M5 ;
        RECT  14.688 51.756 14.712 51.84 ;
    END
  END q[143]
  PIN q[144]
    DIRECTION OUTPUT ;
    USE SIGNAL ;
    PORT
      LAYER M3 ;
        RECT  14.796 51.802 14.814 51.84 ;
    END
  END q[144]
  PIN q[145]
    DIRECTION OUTPUT ;
    USE SIGNAL ;
    PORT
      LAYER M5 ;
        RECT  14.88 51.756 14.904 51.84 ;
    END
  END q[145]
  PIN q[146]
    DIRECTION OUTPUT ;
    USE SIGNAL ;
    PORT
      LAYER M3 ;
        RECT  15.012 51.802 15.03 51.84 ;
    END
  END q[146]
  PIN q[147]
    DIRECTION OUTPUT ;
    USE SIGNAL ;
    PORT
      LAYER M5 ;
        RECT  15.072 51.756 15.096 51.84 ;
    END
  END q[147]
  PIN q[148]
    DIRECTION OUTPUT ;
    USE SIGNAL ;
    PORT
      LAYER M3 ;
        RECT  15.192 51.802 15.21 51.84 ;
    END
  END q[148]
  PIN q[149]
    DIRECTION OUTPUT ;
    USE SIGNAL ;
    PORT
      LAYER M5 ;
        RECT  15.312 51.756 15.336 51.84 ;
    END
  END q[149]
  PIN q[14]
    DIRECTION OUTPUT ;
    USE SIGNAL ;
    PORT
      LAYER M3 ;
        RECT  1.98 51.802 1.998 51.84 ;
    END
  END q[14]
  PIN q[150]
    DIRECTION OUTPUT ;
    USE SIGNAL ;
    PORT
      LAYER M3 ;
        RECT  15.408 51.802 15.426 51.84 ;
    END
  END q[150]
  PIN q[151]
    DIRECTION OUTPUT ;
    USE SIGNAL ;
    PORT
      LAYER M5 ;
        RECT  15.504 51.756 15.528 51.84 ;
    END
  END q[151]
  PIN q[152]
    DIRECTION OUTPUT ;
    USE SIGNAL ;
    PORT
      LAYER M3 ;
        RECT  15.588 51.802 15.606 51.84 ;
    END
  END q[152]
  PIN q[153]
    DIRECTION OUTPUT ;
    USE SIGNAL ;
    PORT
      LAYER M5 ;
        RECT  15.696 51.756 15.72 51.84 ;
    END
  END q[153]
  PIN q[154]
    DIRECTION OUTPUT ;
    USE SIGNAL ;
    PORT
      LAYER M3 ;
        RECT  15.804 51.802 15.822 51.84 ;
    END
  END q[154]
  PIN q[155]
    DIRECTION OUTPUT ;
    USE SIGNAL ;
    PORT
      LAYER M5 ;
        RECT  15.888 51.756 15.912 51.84 ;
    END
  END q[155]
  PIN q[156]
    DIRECTION OUTPUT ;
    USE SIGNAL ;
    PORT
      LAYER M3 ;
        RECT  15.984 51.802 16.002 51.84 ;
    END
  END q[156]
  PIN q[157]
    DIRECTION OUTPUT ;
    USE SIGNAL ;
    PORT
      LAYER M5 ;
        RECT  16.08 51.756 16.104 51.84 ;
    END
  END q[157]
  PIN q[158]
    DIRECTION OUTPUT ;
    USE SIGNAL ;
    PORT
      LAYER M3 ;
        RECT  16.2 51.802 16.218 51.84 ;
    END
  END q[158]
  PIN q[159]
    DIRECTION OUTPUT ;
    USE SIGNAL ;
    PORT
      LAYER M5 ;
        RECT  16.272 51.756 16.296 51.84 ;
    END
  END q[159]
  PIN q[15]
    DIRECTION OUTPUT ;
    USE SIGNAL ;
    PORT
      LAYER M5 ;
        RECT  2.064 51.756 2.088 51.84 ;
    END
  END q[15]
  PIN q[160]
    DIRECTION OUTPUT ;
    USE SIGNAL ;
    PORT
      LAYER M3 ;
        RECT  16.38 51.802 16.398 51.84 ;
    END
  END q[160]
  PIN q[161]
    DIRECTION OUTPUT ;
    USE SIGNAL ;
    PORT
      LAYER M5 ;
        RECT  16.464 51.756 16.488 51.84 ;
    END
  END q[161]
  PIN q[162]
    DIRECTION OUTPUT ;
    USE SIGNAL ;
    PORT
      LAYER M3 ;
        RECT  16.596 51.802 16.614 51.84 ;
    END
  END q[162]
  PIN q[163]
    DIRECTION OUTPUT ;
    USE SIGNAL ;
    PORT
      LAYER M5 ;
        RECT  16.656 51.756 16.68 51.84 ;
    END
  END q[163]
  PIN q[164]
    DIRECTION OUTPUT ;
    USE SIGNAL ;
    PORT
      LAYER M3 ;
        RECT  16.776 51.802 16.794 51.84 ;
    END
  END q[164]
  PIN q[165]
    DIRECTION OUTPUT ;
    USE SIGNAL ;
    PORT
      LAYER M5 ;
        RECT  16.896 51.756 16.92 51.84 ;
    END
  END q[165]
  PIN q[166]
    DIRECTION OUTPUT ;
    USE SIGNAL ;
    PORT
      LAYER M3 ;
        RECT  16.992 51.802 17.01 51.84 ;
    END
  END q[166]
  PIN q[167]
    DIRECTION OUTPUT ;
    USE SIGNAL ;
    PORT
      LAYER M5 ;
        RECT  17.088 51.756 17.112 51.84 ;
    END
  END q[167]
  PIN q[168]
    DIRECTION OUTPUT ;
    USE SIGNAL ;
    PORT
      LAYER M3 ;
        RECT  17.172 51.802 17.19 51.84 ;
    END
  END q[168]
  PIN q[169]
    DIRECTION OUTPUT ;
    USE SIGNAL ;
    PORT
      LAYER M5 ;
        RECT  17.28 51.756 17.304 51.84 ;
    END
  END q[169]
  PIN q[16]
    DIRECTION OUTPUT ;
    USE SIGNAL ;
    PORT
      LAYER M3 ;
        RECT  2.16 51.802 2.178 51.84 ;
    END
  END q[16]
  PIN q[170]
    DIRECTION OUTPUT ;
    USE SIGNAL ;
    PORT
      LAYER M3 ;
        RECT  17.352 51.802 17.37 51.84 ;
    END
  END q[170]
  PIN q[171]
    DIRECTION OUTPUT ;
    USE SIGNAL ;
    PORT
      LAYER M5 ;
        RECT  17.472 51.756 17.496 51.84 ;
    END
  END q[171]
  PIN q[172]
    DIRECTION OUTPUT ;
    USE SIGNAL ;
    PORT
      LAYER M3 ;
        RECT  17.568 51.802 17.586 51.84 ;
    END
  END q[172]
  PIN q[173]
    DIRECTION OUTPUT ;
    USE SIGNAL ;
    PORT
      LAYER M5 ;
        RECT  17.664 51.756 17.688 51.84 ;
    END
  END q[173]
  PIN q[174]
    DIRECTION OUTPUT ;
    USE SIGNAL ;
    PORT
      LAYER M3 ;
        RECT  17.748 51.802 17.766 51.84 ;
    END
  END q[174]
  PIN q[175]
    DIRECTION OUTPUT ;
    USE SIGNAL ;
    PORT
      LAYER M5 ;
        RECT  17.856 51.756 17.88 51.84 ;
    END
  END q[175]
  PIN q[176]
    DIRECTION OUTPUT ;
    USE SIGNAL ;
    PORT
      LAYER M3 ;
        RECT  17.964 51.802 17.982 51.84 ;
    END
  END q[176]
  PIN q[177]
    DIRECTION OUTPUT ;
    USE SIGNAL ;
    PORT
      LAYER M5 ;
        RECT  18.048 51.756 18.072 51.84 ;
    END
  END q[177]
  PIN q[178]
    DIRECTION OUTPUT ;
    USE SIGNAL ;
    PORT
      LAYER M3 ;
        RECT  18.144 51.802 18.162 51.84 ;
    END
  END q[178]
  PIN q[179]
    DIRECTION OUTPUT ;
    USE SIGNAL ;
    PORT
      LAYER M5 ;
        RECT  18.24 51.756 18.264 51.84 ;
    END
  END q[179]
  PIN q[17]
    DIRECTION OUTPUT ;
    USE SIGNAL ;
    PORT
      LAYER M5 ;
        RECT  2.256 51.756 2.28 51.84 ;
    END
  END q[17]
  PIN q[180]
    DIRECTION OUTPUT ;
    USE SIGNAL ;
    PORT
      LAYER M3 ;
        RECT  18.36 51.802 18.378 51.84 ;
    END
  END q[180]
  PIN q[181]
    DIRECTION OUTPUT ;
    USE SIGNAL ;
    PORT
      LAYER M5 ;
        RECT  18.432 51.756 18.456 51.84 ;
    END
  END q[181]
  PIN q[182]
    DIRECTION OUTPUT ;
    USE SIGNAL ;
    PORT
      LAYER M3 ;
        RECT  18.54 51.802 18.558 51.84 ;
    END
  END q[182]
  PIN q[183]
    DIRECTION OUTPUT ;
    USE SIGNAL ;
    PORT
      LAYER M5 ;
        RECT  18.672 51.756 18.696 51.84 ;
    END
  END q[183]
  PIN q[184]
    DIRECTION OUTPUT ;
    USE SIGNAL ;
    PORT
      LAYER M3 ;
        RECT  18.756 51.802 18.774 51.84 ;
    END
  END q[184]
  PIN q[185]
    DIRECTION OUTPUT ;
    USE SIGNAL ;
    PORT
      LAYER M5 ;
        RECT  18.864 51.756 18.888 51.84 ;
    END
  END q[185]
  PIN q[186]
    DIRECTION OUTPUT ;
    USE SIGNAL ;
    PORT
      LAYER M3 ;
        RECT  18.936 51.802 18.954 51.84 ;
    END
  END q[186]
  PIN q[187]
    DIRECTION OUTPUT ;
    USE SIGNAL ;
    PORT
      LAYER M5 ;
        RECT  19.056 51.756 19.08 51.84 ;
    END
  END q[187]
  PIN q[188]
    DIRECTION OUTPUT ;
    USE SIGNAL ;
    PORT
      LAYER M3 ;
        RECT  19.152 51.802 19.17 51.84 ;
    END
  END q[188]
  PIN q[189]
    DIRECTION OUTPUT ;
    USE SIGNAL ;
    PORT
      LAYER M5 ;
        RECT  19.248 51.756 19.272 51.84 ;
    END
  END q[189]
  PIN q[18]
    DIRECTION OUTPUT ;
    USE SIGNAL ;
    PORT
      LAYER M3 ;
        RECT  2.376 51.802 2.394 51.84 ;
    END
  END q[18]
  PIN q[190]
    DIRECTION OUTPUT ;
    USE SIGNAL ;
    PORT
      LAYER M3 ;
        RECT  19.332 51.802 19.35 51.84 ;
    END
  END q[190]
  PIN q[191]
    DIRECTION OUTPUT ;
    USE SIGNAL ;
    PORT
      LAYER M5 ;
        RECT  19.44 51.756 19.464 51.84 ;
    END
  END q[191]
  PIN q[192]
    DIRECTION OUTPUT ;
    USE SIGNAL ;
    PORT
      LAYER M3 ;
        RECT  19.548 51.802 19.566 51.84 ;
    END
  END q[192]
  PIN q[193]
    DIRECTION OUTPUT ;
    USE SIGNAL ;
    PORT
      LAYER M5 ;
        RECT  19.632 51.756 19.656 51.84 ;
    END
  END q[193]
  PIN q[194]
    DIRECTION OUTPUT ;
    USE SIGNAL ;
    PORT
      LAYER M3 ;
        RECT  19.728 51.802 19.746 51.84 ;
    END
  END q[194]
  PIN q[195]
    DIRECTION OUTPUT ;
    USE SIGNAL ;
    PORT
      LAYER M5 ;
        RECT  19.824 51.756 19.848 51.84 ;
    END
  END q[195]
  PIN q[196]
    DIRECTION OUTPUT ;
    USE SIGNAL ;
    PORT
      LAYER M3 ;
        RECT  19.944 51.802 19.962 51.84 ;
    END
  END q[196]
  PIN q[197]
    DIRECTION OUTPUT ;
    USE SIGNAL ;
    PORT
      LAYER M5 ;
        RECT  20.016 51.756 20.04 51.84 ;
    END
  END q[197]
  PIN q[198]
    DIRECTION OUTPUT ;
    USE SIGNAL ;
    PORT
      LAYER M3 ;
        RECT  20.124 51.802 20.142 51.84 ;
    END
  END q[198]
  PIN q[199]
    DIRECTION OUTPUT ;
    USE SIGNAL ;
    PORT
      LAYER M5 ;
        RECT  20.208 51.756 20.232 51.84 ;
    END
  END q[199]
  PIN q[19]
    DIRECTION OUTPUT ;
    USE SIGNAL ;
    PORT
      LAYER M5 ;
        RECT  2.448 51.756 2.472 51.84 ;
    END
  END q[19]
  PIN q[1]
    DIRECTION OUTPUT ;
    USE SIGNAL ;
    PORT
      LAYER M5 ;
        RECT  0.672 51.756 0.696 51.84 ;
    END
  END q[1]
  PIN q[200]
    DIRECTION OUTPUT ;
    USE SIGNAL ;
    PORT
      LAYER M3 ;
        RECT  20.34 51.802 20.358 51.84 ;
    END
  END q[200]
  PIN q[201]
    DIRECTION OUTPUT ;
    USE SIGNAL ;
    PORT
      LAYER M5 ;
        RECT  20.448 51.756 20.472 51.84 ;
    END
  END q[201]
  PIN q[202]
    DIRECTION OUTPUT ;
    USE SIGNAL ;
    PORT
      LAYER M3 ;
        RECT  20.52 51.802 20.538 51.84 ;
    END
  END q[202]
  PIN q[203]
    DIRECTION OUTPUT ;
    USE SIGNAL ;
    PORT
      LAYER M5 ;
        RECT  20.64 51.756 20.664 51.84 ;
    END
  END q[203]
  PIN q[204]
    DIRECTION OUTPUT ;
    USE SIGNAL ;
    PORT
      LAYER M3 ;
        RECT  20.736 51.802 20.754 51.84 ;
    END
  END q[204]
  PIN q[205]
    DIRECTION OUTPUT ;
    USE SIGNAL ;
    PORT
      LAYER M5 ;
        RECT  20.832 51.756 20.856 51.84 ;
    END
  END q[205]
  PIN q[206]
    DIRECTION OUTPUT ;
    USE SIGNAL ;
    PORT
      LAYER M3 ;
        RECT  20.916 51.802 20.934 51.84 ;
    END
  END q[206]
  PIN q[207]
    DIRECTION OUTPUT ;
    USE SIGNAL ;
    PORT
      LAYER M5 ;
        RECT  21.024 51.756 21.048 51.84 ;
    END
  END q[207]
  PIN q[208]
    DIRECTION OUTPUT ;
    USE SIGNAL ;
    PORT
      LAYER M3 ;
        RECT  21.132 51.802 21.15 51.84 ;
    END
  END q[208]
  PIN q[209]
    DIRECTION OUTPUT ;
    USE SIGNAL ;
    PORT
      LAYER M5 ;
        RECT  21.216 51.756 21.24 51.84 ;
    END
  END q[209]
  PIN q[20]
    DIRECTION OUTPUT ;
    USE SIGNAL ;
    PORT
      LAYER M3 ;
        RECT  2.556 51.802 2.574 51.84 ;
    END
  END q[20]
  PIN q[210]
    DIRECTION OUTPUT ;
    USE SIGNAL ;
    PORT
      LAYER M3 ;
        RECT  21.312 51.802 21.33 51.84 ;
    END
  END q[210]
  PIN q[211]
    DIRECTION OUTPUT ;
    USE SIGNAL ;
    PORT
      LAYER M5 ;
        RECT  21.408 51.756 21.432 51.84 ;
    END
  END q[211]
  PIN q[212]
    DIRECTION OUTPUT ;
    USE SIGNAL ;
    PORT
      LAYER M3 ;
        RECT  21.528 51.802 21.546 51.84 ;
    END
  END q[212]
  PIN q[213]
    DIRECTION OUTPUT ;
    USE SIGNAL ;
    PORT
      LAYER M5 ;
        RECT  21.6 51.756 21.624 51.84 ;
    END
  END q[213]
  PIN q[214]
    DIRECTION OUTPUT ;
    USE SIGNAL ;
    PORT
      LAYER M3 ;
        RECT  21.708 51.802 21.726 51.84 ;
    END
  END q[214]
  PIN q[215]
    DIRECTION OUTPUT ;
    USE SIGNAL ;
    PORT
      LAYER M5 ;
        RECT  21.792 51.756 21.816 51.84 ;
    END
  END q[215]
  PIN q[216]
    DIRECTION OUTPUT ;
    USE SIGNAL ;
    PORT
      LAYER M3 ;
        RECT  21.924 51.802 21.942 51.84 ;
    END
  END q[216]
  PIN q[217]
    DIRECTION OUTPUT ;
    USE SIGNAL ;
    PORT
      LAYER M5 ;
        RECT  21.984 51.756 22.008 51.84 ;
    END
  END q[217]
  PIN q[218]
    DIRECTION OUTPUT ;
    USE SIGNAL ;
    PORT
      LAYER M3 ;
        RECT  22.104 51.802 22.122 51.84 ;
    END
  END q[218]
  PIN q[219]
    DIRECTION OUTPUT ;
    USE SIGNAL ;
    PORT
      LAYER M5 ;
        RECT  22.224 51.756 22.248 51.84 ;
    END
  END q[219]
  PIN q[21]
    DIRECTION OUTPUT ;
    USE SIGNAL ;
    PORT
      LAYER M5 ;
        RECT  2.64 51.756 2.664 51.84 ;
    END
  END q[21]
  PIN q[220]
    DIRECTION OUTPUT ;
    USE SIGNAL ;
    PORT
      LAYER M3 ;
        RECT  22.32 51.802 22.338 51.84 ;
    END
  END q[220]
  PIN q[221]
    DIRECTION OUTPUT ;
    USE SIGNAL ;
    PORT
      LAYER M5 ;
        RECT  22.416 51.756 22.44 51.84 ;
    END
  END q[221]
  PIN q[222]
    DIRECTION OUTPUT ;
    USE SIGNAL ;
    PORT
      LAYER M3 ;
        RECT  22.5 51.802 22.518 51.84 ;
    END
  END q[222]
  PIN q[223]
    DIRECTION OUTPUT ;
    USE SIGNAL ;
    PORT
      LAYER M5 ;
        RECT  22.608 51.756 22.632 51.84 ;
    END
  END q[223]
  PIN q[224]
    DIRECTION OUTPUT ;
    USE SIGNAL ;
    PORT
      LAYER M3 ;
        RECT  22.716 51.802 22.734 51.84 ;
    END
  END q[224]
  PIN q[225]
    DIRECTION OUTPUT ;
    USE SIGNAL ;
    PORT
      LAYER M5 ;
        RECT  22.8 51.756 22.824 51.84 ;
    END
  END q[225]
  PIN q[226]
    DIRECTION OUTPUT ;
    USE SIGNAL ;
    PORT
      LAYER M3 ;
        RECT  22.896 51.802 22.914 51.84 ;
    END
  END q[226]
  PIN q[227]
    DIRECTION OUTPUT ;
    USE SIGNAL ;
    PORT
      LAYER M5 ;
        RECT  22.992 51.756 23.016 51.84 ;
    END
  END q[227]
  PIN q[228]
    DIRECTION OUTPUT ;
    USE SIGNAL ;
    PORT
      LAYER M3 ;
        RECT  23.112 51.802 23.13 51.84 ;
    END
  END q[228]
  PIN q[229]
    DIRECTION OUTPUT ;
    USE SIGNAL ;
    PORT
      LAYER M5 ;
        RECT  23.184 51.756 23.208 51.84 ;
    END
  END q[229]
  PIN q[22]
    DIRECTION OUTPUT ;
    USE SIGNAL ;
    PORT
      LAYER M3 ;
        RECT  2.736 51.802 2.754 51.84 ;
    END
  END q[22]
  PIN q[230]
    DIRECTION OUTPUT ;
    USE SIGNAL ;
    PORT
      LAYER M3 ;
        RECT  23.292 51.802 23.31 51.84 ;
    END
  END q[230]
  PIN q[231]
    DIRECTION OUTPUT ;
    USE SIGNAL ;
    PORT
      LAYER M5 ;
        RECT  23.376 51.756 23.4 51.84 ;
    END
  END q[231]
  PIN q[232]
    DIRECTION OUTPUT ;
    USE SIGNAL ;
    PORT
      LAYER M3 ;
        RECT  23.508 51.802 23.526 51.84 ;
    END
  END q[232]
  PIN q[233]
    DIRECTION OUTPUT ;
    USE SIGNAL ;
    PORT
      LAYER M5 ;
        RECT  23.568 51.756 23.592 51.84 ;
    END
  END q[233]
  PIN q[234]
    DIRECTION OUTPUT ;
    USE SIGNAL ;
    PORT
      LAYER M3 ;
        RECT  23.688 51.802 23.706 51.84 ;
    END
  END q[234]
  PIN q[235]
    DIRECTION OUTPUT ;
    USE SIGNAL ;
    PORT
      LAYER M5 ;
        RECT  23.808 51.756 23.832 51.84 ;
    END
  END q[235]
  PIN q[236]
    DIRECTION OUTPUT ;
    USE SIGNAL ;
    PORT
      LAYER M3 ;
        RECT  23.904 51.802 23.922 51.84 ;
    END
  END q[236]
  PIN q[237]
    DIRECTION OUTPUT ;
    USE SIGNAL ;
    PORT
      LAYER M5 ;
        RECT  24 51.756 24.024 51.84 ;
    END
  END q[237]
  PIN q[238]
    DIRECTION OUTPUT ;
    USE SIGNAL ;
    PORT
      LAYER M3 ;
        RECT  24.084 51.802 24.102 51.84 ;
    END
  END q[238]
  PIN q[239]
    DIRECTION OUTPUT ;
    USE SIGNAL ;
    PORT
      LAYER M5 ;
        RECT  24.192 51.756 24.216 51.84 ;
    END
  END q[239]
  PIN q[23]
    DIRECTION OUTPUT ;
    USE SIGNAL ;
    PORT
      LAYER M5 ;
        RECT  2.832 51.756 2.856 51.84 ;
    END
  END q[23]
  PIN q[240]
    DIRECTION OUTPUT ;
    USE SIGNAL ;
    PORT
      LAYER M3 ;
        RECT  24.3 51.802 24.318 51.84 ;
    END
  END q[240]
  PIN q[241]
    DIRECTION OUTPUT ;
    USE SIGNAL ;
    PORT
      LAYER M5 ;
        RECT  24.384 51.756 24.408 51.84 ;
    END
  END q[241]
  PIN q[242]
    DIRECTION OUTPUT ;
    USE SIGNAL ;
    PORT
      LAYER M3 ;
        RECT  24.48 51.802 24.498 51.84 ;
    END
  END q[242]
  PIN q[243]
    DIRECTION OUTPUT ;
    USE SIGNAL ;
    PORT
      LAYER M5 ;
        RECT  24.576 51.756 24.6 51.84 ;
    END
  END q[243]
  PIN q[244]
    DIRECTION OUTPUT ;
    USE SIGNAL ;
    PORT
      LAYER M3 ;
        RECT  24.66 51.802 24.678 51.84 ;
    END
  END q[244]
  PIN q[245]
    DIRECTION OUTPUT ;
    USE SIGNAL ;
    PORT
      LAYER M5 ;
        RECT  24.768 51.756 24.792 51.84 ;
    END
  END q[245]
  PIN q[246]
    DIRECTION OUTPUT ;
    USE SIGNAL ;
    PORT
      LAYER M3 ;
        RECT  24.876 51.802 24.894 51.84 ;
    END
  END q[246]
  PIN q[247]
    DIRECTION OUTPUT ;
    USE SIGNAL ;
    PORT
      LAYER M5 ;
        RECT  24.96 51.756 24.984 51.84 ;
    END
  END q[247]
  PIN q[248]
    DIRECTION OUTPUT ;
    USE SIGNAL ;
    PORT
      LAYER M3 ;
        RECT  25.056 51.802 25.074 51.84 ;
    END
  END q[248]
  PIN q[249]
    DIRECTION OUTPUT ;
    USE SIGNAL ;
    PORT
      LAYER M5 ;
        RECT  25.152 51.756 25.176 51.84 ;
    END
  END q[249]
  PIN q[24]
    DIRECTION OUTPUT ;
    USE SIGNAL ;
    PORT
      LAYER M3 ;
        RECT  2.952 51.802 2.97 51.84 ;
    END
  END q[24]
  PIN q[250]
    DIRECTION OUTPUT ;
    USE SIGNAL ;
    PORT
      LAYER M3 ;
        RECT  25.272 51.802 25.29 51.84 ;
    END
  END q[250]
  PIN q[251]
    DIRECTION OUTPUT ;
    USE SIGNAL ;
    PORT
      LAYER M5 ;
        RECT  25.344 51.756 25.368 51.84 ;
    END
  END q[251]
  PIN q[252]
    DIRECTION OUTPUT ;
    USE SIGNAL ;
    PORT
      LAYER M3 ;
        RECT  25.452 51.802 25.47 51.84 ;
    END
  END q[252]
  PIN q[253]
    DIRECTION OUTPUT ;
    USE SIGNAL ;
    PORT
      LAYER M5 ;
        RECT  25.584 51.756 25.608 51.84 ;
    END
  END q[253]
  PIN q[254]
    DIRECTION OUTPUT ;
    USE SIGNAL ;
    PORT
      LAYER M3 ;
        RECT  25.668 51.802 25.686 51.84 ;
    END
  END q[254]
  PIN q[255]
    DIRECTION OUTPUT ;
    USE SIGNAL ;
    PORT
      LAYER M5 ;
        RECT  25.776 51.756 25.8 51.84 ;
    END
  END q[255]
  PIN q[256]
    DIRECTION OUTPUT ;
    USE SIGNAL ;
    PORT
      LAYER M3 ;
        RECT  25.848 51.802 25.866 51.84 ;
    END
  END q[256]
  PIN q[257]
    DIRECTION OUTPUT ;
    USE SIGNAL ;
    PORT
      LAYER M5 ;
        RECT  25.968 51.756 25.992 51.84 ;
    END
  END q[257]
  PIN q[258]
    DIRECTION OUTPUT ;
    USE SIGNAL ;
    PORT
      LAYER M3 ;
        RECT  26.064 51.802 26.082 51.84 ;
    END
  END q[258]
  PIN q[259]
    DIRECTION OUTPUT ;
    USE SIGNAL ;
    PORT
      LAYER M5 ;
        RECT  26.16 51.756 26.184 51.84 ;
    END
  END q[259]
  PIN q[25]
    DIRECTION OUTPUT ;
    USE SIGNAL ;
    PORT
      LAYER M5 ;
        RECT  3.024 51.756 3.048 51.84 ;
    END
  END q[25]
  PIN q[260]
    DIRECTION OUTPUT ;
    USE SIGNAL ;
    PORT
      LAYER M3 ;
        RECT  26.244 51.802 26.262 51.84 ;
    END
  END q[260]
  PIN q[261]
    DIRECTION OUTPUT ;
    USE SIGNAL ;
    PORT
      LAYER M5 ;
        RECT  26.352 51.756 26.376 51.84 ;
    END
  END q[261]
  PIN q[262]
    DIRECTION OUTPUT ;
    USE SIGNAL ;
    PORT
      LAYER M3 ;
        RECT  26.46 51.802 26.478 51.84 ;
    END
  END q[262]
  PIN q[263]
    DIRECTION OUTPUT ;
    USE SIGNAL ;
    PORT
      LAYER M5 ;
        RECT  26.544 51.756 26.568 51.84 ;
    END
  END q[263]
  PIN q[264]
    DIRECTION OUTPUT ;
    USE SIGNAL ;
    PORT
      LAYER M3 ;
        RECT  26.64 51.802 26.658 51.84 ;
    END
  END q[264]
  PIN q[265]
    DIRECTION OUTPUT ;
    USE SIGNAL ;
    PORT
      LAYER M5 ;
        RECT  26.736 51.756 26.76 51.84 ;
    END
  END q[265]
  PIN q[266]
    DIRECTION OUTPUT ;
    USE SIGNAL ;
    PORT
      LAYER M3 ;
        RECT  26.856 51.802 26.874 51.84 ;
    END
  END q[266]
  PIN q[267]
    DIRECTION OUTPUT ;
    USE SIGNAL ;
    PORT
      LAYER M5 ;
        RECT  26.928 51.756 26.952 51.84 ;
    END
  END q[267]
  PIN q[268]
    DIRECTION OUTPUT ;
    USE SIGNAL ;
    PORT
      LAYER M3 ;
        RECT  27.036 51.802 27.054 51.84 ;
    END
  END q[268]
  PIN q[269]
    DIRECTION OUTPUT ;
    USE SIGNAL ;
    PORT
      LAYER M5 ;
        RECT  27.12 51.756 27.144 51.84 ;
    END
  END q[269]
  PIN q[26]
    DIRECTION OUTPUT ;
    USE SIGNAL ;
    PORT
      LAYER M3 ;
        RECT  3.132 51.802 3.15 51.84 ;
    END
  END q[26]
  PIN q[270]
    DIRECTION OUTPUT ;
    USE SIGNAL ;
    PORT
      LAYER M3 ;
        RECT  27.252 51.802 27.27 51.84 ;
    END
  END q[270]
  PIN q[271]
    DIRECTION OUTPUT ;
    USE SIGNAL ;
    PORT
      LAYER M5 ;
        RECT  27.36 51.756 27.384 51.84 ;
    END
  END q[271]
  PIN q[272]
    DIRECTION OUTPUT ;
    USE SIGNAL ;
    PORT
      LAYER M3 ;
        RECT  27.432 51.802 27.45 51.84 ;
    END
  END q[272]
  PIN q[273]
    DIRECTION OUTPUT ;
    USE SIGNAL ;
    PORT
      LAYER M5 ;
        RECT  27.552 51.756 27.576 51.84 ;
    END
  END q[273]
  PIN q[274]
    DIRECTION OUTPUT ;
    USE SIGNAL ;
    PORT
      LAYER M3 ;
        RECT  27.648 51.802 27.666 51.84 ;
    END
  END q[274]
  PIN q[275]
    DIRECTION OUTPUT ;
    USE SIGNAL ;
    PORT
      LAYER M5 ;
        RECT  27.744 51.756 27.768 51.84 ;
    END
  END q[275]
  PIN q[276]
    DIRECTION OUTPUT ;
    USE SIGNAL ;
    PORT
      LAYER M3 ;
        RECT  27.828 51.802 27.846 51.84 ;
    END
  END q[276]
  PIN q[277]
    DIRECTION OUTPUT ;
    USE SIGNAL ;
    PORT
      LAYER M5 ;
        RECT  27.936 51.756 27.96 51.84 ;
    END
  END q[277]
  PIN q[278]
    DIRECTION OUTPUT ;
    USE SIGNAL ;
    PORT
      LAYER M3 ;
        RECT  28.044 51.802 28.062 51.84 ;
    END
  END q[278]
  PIN q[279]
    DIRECTION OUTPUT ;
    USE SIGNAL ;
    PORT
      LAYER M5 ;
        RECT  28.128 51.756 28.152 51.84 ;
    END
  END q[279]
  PIN q[27]
    DIRECTION OUTPUT ;
    USE SIGNAL ;
    PORT
      LAYER M5 ;
        RECT  3.264 51.756 3.288 51.84 ;
    END
  END q[27]
  PIN q[280]
    DIRECTION OUTPUT ;
    USE SIGNAL ;
    PORT
      LAYER M3 ;
        RECT  28.224 51.802 28.242 51.84 ;
    END
  END q[280]
  PIN q[281]
    DIRECTION OUTPUT ;
    USE SIGNAL ;
    PORT
      LAYER M5 ;
        RECT  28.32 51.756 28.344 51.84 ;
    END
  END q[281]
  PIN q[282]
    DIRECTION OUTPUT ;
    USE SIGNAL ;
    PORT
      LAYER M3 ;
        RECT  28.44 51.802 28.458 51.84 ;
    END
  END q[282]
  PIN q[283]
    DIRECTION OUTPUT ;
    USE SIGNAL ;
    PORT
      LAYER M5 ;
        RECT  28.512 51.756 28.536 51.84 ;
    END
  END q[283]
  PIN q[284]
    DIRECTION OUTPUT ;
    USE SIGNAL ;
    PORT
      LAYER M3 ;
        RECT  28.62 51.802 28.638 51.84 ;
    END
  END q[284]
  PIN q[285]
    DIRECTION OUTPUT ;
    USE SIGNAL ;
    PORT
      LAYER M5 ;
        RECT  28.704 51.756 28.728 51.84 ;
    END
  END q[285]
  PIN q[286]
    DIRECTION OUTPUT ;
    USE SIGNAL ;
    PORT
      LAYER M3 ;
        RECT  28.836 51.802 28.854 51.84 ;
    END
  END q[286]
  PIN q[287]
    DIRECTION OUTPUT ;
    USE SIGNAL ;
    PORT
      LAYER M5 ;
        RECT  28.944 51.756 28.968 51.84 ;
    END
  END q[287]
  PIN q[288]
    DIRECTION OUTPUT ;
    USE SIGNAL ;
    PORT
      LAYER M3 ;
        RECT  29.016 51.802 29.034 51.84 ;
    END
  END q[288]
  PIN q[289]
    DIRECTION OUTPUT ;
    USE SIGNAL ;
    PORT
      LAYER M5 ;
        RECT  29.136 51.756 29.16 51.84 ;
    END
  END q[289]
  PIN q[28]
    DIRECTION OUTPUT ;
    USE SIGNAL ;
    PORT
      LAYER M3 ;
        RECT  3.348 51.802 3.366 51.84 ;
    END
  END q[28]
  PIN q[290]
    DIRECTION OUTPUT ;
    USE SIGNAL ;
    PORT
      LAYER M3 ;
        RECT  29.232 51.802 29.25 51.84 ;
    END
  END q[290]
  PIN q[291]
    DIRECTION OUTPUT ;
    USE SIGNAL ;
    PORT
      LAYER M5 ;
        RECT  29.328 51.756 29.352 51.84 ;
    END
  END q[291]
  PIN q[292]
    DIRECTION OUTPUT ;
    USE SIGNAL ;
    PORT
      LAYER M3 ;
        RECT  29.412 51.802 29.43 51.84 ;
    END
  END q[292]
  PIN q[293]
    DIRECTION OUTPUT ;
    USE SIGNAL ;
    PORT
      LAYER M5 ;
        RECT  29.52 51.756 29.544 51.84 ;
    END
  END q[293]
  PIN q[294]
    DIRECTION OUTPUT ;
    USE SIGNAL ;
    PORT
      LAYER M3 ;
        RECT  29.628 51.802 29.646 51.84 ;
    END
  END q[294]
  PIN q[295]
    DIRECTION OUTPUT ;
    USE SIGNAL ;
    PORT
      LAYER M5 ;
        RECT  29.712 51.756 29.736 51.84 ;
    END
  END q[295]
  PIN q[296]
    DIRECTION OUTPUT ;
    USE SIGNAL ;
    PORT
      LAYER M3 ;
        RECT  29.808 51.802 29.826 51.84 ;
    END
  END q[296]
  PIN q[297]
    DIRECTION OUTPUT ;
    USE SIGNAL ;
    PORT
      LAYER M5 ;
        RECT  29.904 51.756 29.928 51.84 ;
    END
  END q[297]
  PIN q[298]
    DIRECTION OUTPUT ;
    USE SIGNAL ;
    PORT
      LAYER M3 ;
        RECT  30.024 51.802 30.042 51.84 ;
    END
  END q[298]
  PIN q[299]
    DIRECTION OUTPUT ;
    USE SIGNAL ;
    PORT
      LAYER M5 ;
        RECT  30.096 51.756 30.12 51.84 ;
    END
  END q[299]
  PIN q[29]
    DIRECTION OUTPUT ;
    USE SIGNAL ;
    PORT
      LAYER M5 ;
        RECT  3.456 51.756 3.48 51.84 ;
    END
  END q[29]
  PIN q[2]
    DIRECTION OUTPUT ;
    USE SIGNAL ;
    PORT
      LAYER M3 ;
        RECT  0.792 51.802 0.81 51.84 ;
    END
  END q[2]
  PIN q[300]
    DIRECTION OUTPUT ;
    USE SIGNAL ;
    PORT
      LAYER M3 ;
        RECT  30.204 51.802 30.222 51.84 ;
    END
  END q[300]
  PIN q[301]
    DIRECTION OUTPUT ;
    USE SIGNAL ;
    PORT
      LAYER M5 ;
        RECT  30.288 51.756 30.312 51.84 ;
    END
  END q[301]
  PIN q[302]
    DIRECTION OUTPUT ;
    USE SIGNAL ;
    PORT
      LAYER M3 ;
        RECT  30.42 51.802 30.438 51.84 ;
    END
  END q[302]
  PIN q[303]
    DIRECTION OUTPUT ;
    USE SIGNAL ;
    PORT
      LAYER M5 ;
        RECT  30.48 51.756 30.504 51.84 ;
    END
  END q[303]
  PIN q[304]
    DIRECTION OUTPUT ;
    USE SIGNAL ;
    PORT
      LAYER M3 ;
        RECT  30.6 51.802 30.618 51.84 ;
    END
  END q[304]
  PIN q[305]
    DIRECTION OUTPUT ;
    USE SIGNAL ;
    PORT
      LAYER M5 ;
        RECT  30.72 51.756 30.744 51.84 ;
    END
  END q[305]
  PIN q[306]
    DIRECTION OUTPUT ;
    USE SIGNAL ;
    PORT
      LAYER M3 ;
        RECT  30.816 51.802 30.834 51.84 ;
    END
  END q[306]
  PIN q[307]
    DIRECTION OUTPUT ;
    USE SIGNAL ;
    PORT
      LAYER M5 ;
        RECT  30.912 51.756 30.936 51.84 ;
    END
  END q[307]
  PIN q[308]
    DIRECTION OUTPUT ;
    USE SIGNAL ;
    PORT
      LAYER M3 ;
        RECT  30.996 51.802 31.014 51.84 ;
    END
  END q[308]
  PIN q[309]
    DIRECTION OUTPUT ;
    USE SIGNAL ;
    PORT
      LAYER M5 ;
        RECT  31.104 51.756 31.128 51.84 ;
    END
  END q[309]
  PIN q[30]
    DIRECTION OUTPUT ;
    USE SIGNAL ;
    PORT
      LAYER M3 ;
        RECT  3.528 51.802 3.546 51.84 ;
    END
  END q[30]
  PIN q[310]
    DIRECTION OUTPUT ;
    USE SIGNAL ;
    PORT
      LAYER M3 ;
        RECT  31.212 51.802 31.23 51.84 ;
    END
  END q[310]
  PIN q[311]
    DIRECTION OUTPUT ;
    USE SIGNAL ;
    PORT
      LAYER M5 ;
        RECT  31.296 51.756 31.32 51.84 ;
    END
  END q[311]
  PIN q[312]
    DIRECTION OUTPUT ;
    USE SIGNAL ;
    PORT
      LAYER M3 ;
        RECT  31.392 51.802 31.41 51.84 ;
    END
  END q[312]
  PIN q[313]
    DIRECTION OUTPUT ;
    USE SIGNAL ;
    PORT
      LAYER M5 ;
        RECT  31.488 51.756 31.512 51.84 ;
    END
  END q[313]
  PIN q[314]
    DIRECTION OUTPUT ;
    USE SIGNAL ;
    PORT
      LAYER M3 ;
        RECT  31.572 51.802 31.59 51.84 ;
    END
  END q[314]
  PIN q[315]
    DIRECTION OUTPUT ;
    USE SIGNAL ;
    PORT
      LAYER M5 ;
        RECT  31.68 51.756 31.704 51.84 ;
    END
  END q[315]
  PIN q[316]
    DIRECTION OUTPUT ;
    USE SIGNAL ;
    PORT
      LAYER M3 ;
        RECT  31.788 51.802 31.806 51.84 ;
    END
  END q[316]
  PIN q[317]
    DIRECTION OUTPUT ;
    USE SIGNAL ;
    PORT
      LAYER M5 ;
        RECT  31.872 51.756 31.896 51.84 ;
    END
  END q[317]
  PIN q[318]
    DIRECTION OUTPUT ;
    USE SIGNAL ;
    PORT
      LAYER M3 ;
        RECT  31.968 51.802 31.986 51.84 ;
    END
  END q[318]
  PIN q[319]
    DIRECTION OUTPUT ;
    USE SIGNAL ;
    PORT
      LAYER M5 ;
        RECT  32.064 51.756 32.088 51.84 ;
    END
  END q[319]
  PIN q[31]
    DIRECTION OUTPUT ;
    USE SIGNAL ;
    PORT
      LAYER M5 ;
        RECT  3.648 51.756 3.672 51.84 ;
    END
  END q[31]
  PIN q[320]
    DIRECTION OUTPUT ;
    USE SIGNAL ;
    PORT
      LAYER M3 ;
        RECT  32.184 51.802 32.202 51.84 ;
    END
  END q[320]
  PIN q[321]
    DIRECTION OUTPUT ;
    USE SIGNAL ;
    PORT
      LAYER M5 ;
        RECT  32.256 51.756 32.28 51.84 ;
    END
  END q[321]
  PIN q[322]
    DIRECTION OUTPUT ;
    USE SIGNAL ;
    PORT
      LAYER M3 ;
        RECT  32.364 51.802 32.382 51.84 ;
    END
  END q[322]
  PIN q[323]
    DIRECTION OUTPUT ;
    USE SIGNAL ;
    PORT
      LAYER M5 ;
        RECT  32.496 51.756 32.52 51.84 ;
    END
  END q[323]
  PIN q[324]
    DIRECTION OUTPUT ;
    USE SIGNAL ;
    PORT
      LAYER M3 ;
        RECT  32.58 51.802 32.598 51.84 ;
    END
  END q[324]
  PIN q[325]
    DIRECTION OUTPUT ;
    USE SIGNAL ;
    PORT
      LAYER M5 ;
        RECT  32.688 51.756 32.712 51.84 ;
    END
  END q[325]
  PIN q[326]
    DIRECTION OUTPUT ;
    USE SIGNAL ;
    PORT
      LAYER M3 ;
        RECT  32.76 51.802 32.778 51.84 ;
    END
  END q[326]
  PIN q[327]
    DIRECTION OUTPUT ;
    USE SIGNAL ;
    PORT
      LAYER M5 ;
        RECT  32.88 51.756 32.904 51.84 ;
    END
  END q[327]
  PIN q[328]
    DIRECTION OUTPUT ;
    USE SIGNAL ;
    PORT
      LAYER M3 ;
        RECT  32.976 51.802 32.994 51.84 ;
    END
  END q[328]
  PIN q[329]
    DIRECTION OUTPUT ;
    USE SIGNAL ;
    PORT
      LAYER M5 ;
        RECT  33.072 51.756 33.096 51.84 ;
    END
  END q[329]
  PIN q[32]
    DIRECTION OUTPUT ;
    USE SIGNAL ;
    PORT
      LAYER M3 ;
        RECT  3.744 51.802 3.762 51.84 ;
    END
  END q[32]
  PIN q[330]
    DIRECTION OUTPUT ;
    USE SIGNAL ;
    PORT
      LAYER M3 ;
        RECT  33.156 51.802 33.174 51.84 ;
    END
  END q[330]
  PIN q[331]
    DIRECTION OUTPUT ;
    USE SIGNAL ;
    PORT
      LAYER M5 ;
        RECT  33.264 51.756 33.288 51.84 ;
    END
  END q[331]
  PIN q[332]
    DIRECTION OUTPUT ;
    USE SIGNAL ;
    PORT
      LAYER M3 ;
        RECT  33.372 51.802 33.39 51.84 ;
    END
  END q[332]
  PIN q[333]
    DIRECTION OUTPUT ;
    USE SIGNAL ;
    PORT
      LAYER M5 ;
        RECT  33.456 51.756 33.48 51.84 ;
    END
  END q[333]
  PIN q[334]
    DIRECTION OUTPUT ;
    USE SIGNAL ;
    PORT
      LAYER M3 ;
        RECT  33.552 51.802 33.57 51.84 ;
    END
  END q[334]
  PIN q[335]
    DIRECTION OUTPUT ;
    USE SIGNAL ;
    PORT
      LAYER M5 ;
        RECT  33.648 51.756 33.672 51.84 ;
    END
  END q[335]
  PIN q[336]
    DIRECTION OUTPUT ;
    USE SIGNAL ;
    PORT
      LAYER M3 ;
        RECT  33.768 51.802 33.786 51.84 ;
    END
  END q[336]
  PIN q[337]
    DIRECTION OUTPUT ;
    USE SIGNAL ;
    PORT
      LAYER M5 ;
        RECT  33.84 51.756 33.864 51.84 ;
    END
  END q[337]
  PIN q[338]
    DIRECTION OUTPUT ;
    USE SIGNAL ;
    PORT
      LAYER M3 ;
        RECT  33.948 51.802 33.966 51.84 ;
    END
  END q[338]
  PIN q[339]
    DIRECTION OUTPUT ;
    USE SIGNAL ;
    PORT
      LAYER M5 ;
        RECT  34.032 51.756 34.056 51.84 ;
    END
  END q[339]
  PIN q[33]
    DIRECTION OUTPUT ;
    USE SIGNAL ;
    PORT
      LAYER M5 ;
        RECT  3.84 51.756 3.864 51.84 ;
    END
  END q[33]
  PIN q[340]
    DIRECTION OUTPUT ;
    USE SIGNAL ;
    PORT
      LAYER M3 ;
        RECT  34.164 51.802 34.182 51.84 ;
    END
  END q[340]
  PIN q[341]
    DIRECTION OUTPUT ;
    USE SIGNAL ;
    PORT
      LAYER M5 ;
        RECT  34.272 51.756 34.296 51.84 ;
    END
  END q[341]
  PIN q[342]
    DIRECTION OUTPUT ;
    USE SIGNAL ;
    PORT
      LAYER M3 ;
        RECT  34.344 51.802 34.362 51.84 ;
    END
  END q[342]
  PIN q[343]
    DIRECTION OUTPUT ;
    USE SIGNAL ;
    PORT
      LAYER M5 ;
        RECT  34.464 51.756 34.488 51.84 ;
    END
  END q[343]
  PIN q[344]
    DIRECTION OUTPUT ;
    USE SIGNAL ;
    PORT
      LAYER M3 ;
        RECT  34.56 51.802 34.578 51.84 ;
    END
  END q[344]
  PIN q[345]
    DIRECTION OUTPUT ;
    USE SIGNAL ;
    PORT
      LAYER M5 ;
        RECT  34.656 51.756 34.68 51.84 ;
    END
  END q[345]
  PIN q[346]
    DIRECTION OUTPUT ;
    USE SIGNAL ;
    PORT
      LAYER M3 ;
        RECT  34.74 51.802 34.758 51.84 ;
    END
  END q[346]
  PIN q[347]
    DIRECTION OUTPUT ;
    USE SIGNAL ;
    PORT
      LAYER M5 ;
        RECT  34.848 51.756 34.872 51.84 ;
    END
  END q[347]
  PIN q[348]
    DIRECTION OUTPUT ;
    USE SIGNAL ;
    PORT
      LAYER M3 ;
        RECT  34.956 51.802 34.974 51.84 ;
    END
  END q[348]
  PIN q[349]
    DIRECTION OUTPUT ;
    USE SIGNAL ;
    PORT
      LAYER M5 ;
        RECT  35.04 51.756 35.064 51.84 ;
    END
  END q[349]
  PIN q[34]
    DIRECTION OUTPUT ;
    USE SIGNAL ;
    PORT
      LAYER M3 ;
        RECT  3.924 51.802 3.942 51.84 ;
    END
  END q[34]
  PIN q[350]
    DIRECTION OUTPUT ;
    USE SIGNAL ;
    PORT
      LAYER M3 ;
        RECT  35.136 51.802 35.154 51.84 ;
    END
  END q[350]
  PIN q[351]
    DIRECTION OUTPUT ;
    USE SIGNAL ;
    PORT
      LAYER M5 ;
        RECT  35.232 51.756 35.256 51.84 ;
    END
  END q[351]
  PIN q[352]
    DIRECTION OUTPUT ;
    USE SIGNAL ;
    PORT
      LAYER M3 ;
        RECT  35.352 51.802 35.37 51.84 ;
    END
  END q[352]
  PIN q[353]
    DIRECTION OUTPUT ;
    USE SIGNAL ;
    PORT
      LAYER M5 ;
        RECT  35.424 51.756 35.448 51.84 ;
    END
  END q[353]
  PIN q[354]
    DIRECTION OUTPUT ;
    USE SIGNAL ;
    PORT
      LAYER M3 ;
        RECT  35.532 51.802 35.55 51.84 ;
    END
  END q[354]
  PIN q[355]
    DIRECTION OUTPUT ;
    USE SIGNAL ;
    PORT
      LAYER M5 ;
        RECT  35.616 51.756 35.64 51.84 ;
    END
  END q[355]
  PIN q[356]
    DIRECTION OUTPUT ;
    USE SIGNAL ;
    PORT
      LAYER M3 ;
        RECT  35.748 51.802 35.766 51.84 ;
    END
  END q[356]
  PIN q[357]
    DIRECTION OUTPUT ;
    USE SIGNAL ;
    PORT
      LAYER M5 ;
        RECT  35.856 51.756 35.88 51.84 ;
    END
  END q[357]
  PIN q[358]
    DIRECTION OUTPUT ;
    USE SIGNAL ;
    PORT
      LAYER M3 ;
        RECT  35.928 51.802 35.946 51.84 ;
    END
  END q[358]
  PIN q[359]
    DIRECTION OUTPUT ;
    USE SIGNAL ;
    PORT
      LAYER M5 ;
        RECT  36.048 51.756 36.072 51.84 ;
    END
  END q[359]
  PIN q[35]
    DIRECTION OUTPUT ;
    USE SIGNAL ;
    PORT
      LAYER M5 ;
        RECT  4.032 51.756 4.056 51.84 ;
    END
  END q[35]
  PIN q[360]
    DIRECTION OUTPUT ;
    USE SIGNAL ;
    PORT
      LAYER M3 ;
        RECT  36.144 51.802 36.162 51.84 ;
    END
  END q[360]
  PIN q[361]
    DIRECTION OUTPUT ;
    USE SIGNAL ;
    PORT
      LAYER M5 ;
        RECT  36.24 51.756 36.264 51.84 ;
    END
  END q[361]
  PIN q[362]
    DIRECTION OUTPUT ;
    USE SIGNAL ;
    PORT
      LAYER M3 ;
        RECT  36.324 51.802 36.342 51.84 ;
    END
  END q[362]
  PIN q[363]
    DIRECTION OUTPUT ;
    USE SIGNAL ;
    PORT
      LAYER M5 ;
        RECT  36.432 51.756 36.456 51.84 ;
    END
  END q[363]
  PIN q[364]
    DIRECTION OUTPUT ;
    USE SIGNAL ;
    PORT
      LAYER M3 ;
        RECT  36.54 51.802 36.558 51.84 ;
    END
  END q[364]
  PIN q[365]
    DIRECTION OUTPUT ;
    USE SIGNAL ;
    PORT
      LAYER M5 ;
        RECT  36.624 51.756 36.648 51.84 ;
    END
  END q[365]
  PIN q[366]
    DIRECTION OUTPUT ;
    USE SIGNAL ;
    PORT
      LAYER M3 ;
        RECT  36.72 51.802 36.738 51.84 ;
    END
  END q[366]
  PIN q[367]
    DIRECTION OUTPUT ;
    USE SIGNAL ;
    PORT
      LAYER M5 ;
        RECT  36.816 51.756 36.84 51.84 ;
    END
  END q[367]
  PIN q[368]
    DIRECTION OUTPUT ;
    USE SIGNAL ;
    PORT
      LAYER M3 ;
        RECT  36.936 51.802 36.954 51.84 ;
    END
  END q[368]
  PIN q[369]
    DIRECTION OUTPUT ;
    USE SIGNAL ;
    PORT
      LAYER M5 ;
        RECT  37.008 51.756 37.032 51.84 ;
    END
  END q[369]
  PIN q[36]
    DIRECTION OUTPUT ;
    USE SIGNAL ;
    PORT
      LAYER M3 ;
        RECT  4.14 51.802 4.158 51.84 ;
    END
  END q[36]
  PIN q[370]
    DIRECTION OUTPUT ;
    USE SIGNAL ;
    PORT
      LAYER M3 ;
        RECT  37.116 51.802 37.134 51.84 ;
    END
  END q[370]
  PIN q[371]
    DIRECTION OUTPUT ;
    USE SIGNAL ;
    PORT
      LAYER M5 ;
        RECT  37.2 51.756 37.224 51.84 ;
    END
  END q[371]
  PIN q[372]
    DIRECTION OUTPUT ;
    USE SIGNAL ;
    PORT
      LAYER M3 ;
        RECT  37.332 51.802 37.35 51.84 ;
    END
  END q[372]
  PIN q[373]
    DIRECTION OUTPUT ;
    USE SIGNAL ;
    PORT
      LAYER M5 ;
        RECT  37.392 51.756 37.416 51.84 ;
    END
  END q[373]
  PIN q[374]
    DIRECTION OUTPUT ;
    USE SIGNAL ;
    PORT
      LAYER M3 ;
        RECT  37.512 51.802 37.53 51.84 ;
    END
  END q[374]
  PIN q[375]
    DIRECTION OUTPUT ;
    USE SIGNAL ;
    PORT
      LAYER M5 ;
        RECT  37.632 51.756 37.656 51.84 ;
    END
  END q[375]
  PIN q[376]
    DIRECTION OUTPUT ;
    USE SIGNAL ;
    PORT
      LAYER M3 ;
        RECT  37.728 51.802 37.746 51.84 ;
    END
  END q[376]
  PIN q[377]
    DIRECTION OUTPUT ;
    USE SIGNAL ;
    PORT
      LAYER M5 ;
        RECT  37.824 51.756 37.848 51.84 ;
    END
  END q[377]
  PIN q[378]
    DIRECTION OUTPUT ;
    USE SIGNAL ;
    PORT
      LAYER M3 ;
        RECT  37.908 51.802 37.926 51.84 ;
    END
  END q[378]
  PIN q[379]
    DIRECTION OUTPUT ;
    USE SIGNAL ;
    PORT
      LAYER M5 ;
        RECT  38.016 51.756 38.04 51.84 ;
    END
  END q[379]
  PIN q[37]
    DIRECTION OUTPUT ;
    USE SIGNAL ;
    PORT
      LAYER M5 ;
        RECT  4.224 51.756 4.248 51.84 ;
    END
  END q[37]
  PIN q[380]
    DIRECTION OUTPUT ;
    USE SIGNAL ;
    PORT
      LAYER M3 ;
        RECT  38.124 51.802 38.142 51.84 ;
    END
  END q[380]
  PIN q[381]
    DIRECTION OUTPUT ;
    USE SIGNAL ;
    PORT
      LAYER M5 ;
        RECT  38.208 51.756 38.232 51.84 ;
    END
  END q[381]
  PIN q[382]
    DIRECTION OUTPUT ;
    USE SIGNAL ;
    PORT
      LAYER M3 ;
        RECT  38.304 51.802 38.322 51.84 ;
    END
  END q[382]
  PIN q[383]
    DIRECTION OUTPUT ;
    USE SIGNAL ;
    PORT
      LAYER M5 ;
        RECT  38.4 51.756 38.424 51.84 ;
    END
  END q[383]
  PIN q[384]
    DIRECTION OUTPUT ;
    USE SIGNAL ;
    PORT
      LAYER M3 ;
        RECT  38.52 51.802 38.538 51.84 ;
    END
  END q[384]
  PIN q[385]
    DIRECTION OUTPUT ;
    USE SIGNAL ;
    PORT
      LAYER M5 ;
        RECT  38.592 51.756 38.616 51.84 ;
    END
  END q[385]
  PIN q[386]
    DIRECTION OUTPUT ;
    USE SIGNAL ;
    PORT
      LAYER M3 ;
        RECT  38.7 51.802 38.718 51.84 ;
    END
  END q[386]
  PIN q[387]
    DIRECTION OUTPUT ;
    USE SIGNAL ;
    PORT
      LAYER M5 ;
        RECT  38.784 51.756 38.808 51.84 ;
    END
  END q[387]
  PIN q[388]
    DIRECTION OUTPUT ;
    USE SIGNAL ;
    PORT
      LAYER M3 ;
        RECT  38.88 51.802 38.898 51.84 ;
    END
  END q[388]
  PIN q[389]
    DIRECTION OUTPUT ;
    USE SIGNAL ;
    PORT
      LAYER M5 ;
        RECT  38.976 51.756 39 51.84 ;
    END
  END q[389]
  PIN q[38]
    DIRECTION OUTPUT ;
    USE SIGNAL ;
    PORT
      LAYER M3 ;
        RECT  4.32 51.802 4.338 51.84 ;
    END
  END q[38]
  PIN q[390]
    DIRECTION OUTPUT ;
    USE SIGNAL ;
    PORT
      LAYER M3 ;
        RECT  39.096 51.802 39.114 51.84 ;
    END
  END q[390]
  PIN q[391]
    DIRECTION OUTPUT ;
    USE SIGNAL ;
    PORT
      LAYER M5 ;
        RECT  39.168 51.756 39.192 51.84 ;
    END
  END q[391]
  PIN q[392]
    DIRECTION OUTPUT ;
    USE SIGNAL ;
    PORT
      LAYER M3 ;
        RECT  39.276 51.802 39.294 51.84 ;
    END
  END q[392]
  PIN q[393]
    DIRECTION OUTPUT ;
    USE SIGNAL ;
    PORT
      LAYER M5 ;
        RECT  39.408 51.756 39.432 51.84 ;
    END
  END q[393]
  PIN q[394]
    DIRECTION OUTPUT ;
    USE SIGNAL ;
    PORT
      LAYER M3 ;
        RECT  39.492 51.802 39.51 51.84 ;
    END
  END q[394]
  PIN q[395]
    DIRECTION OUTPUT ;
    USE SIGNAL ;
    PORT
      LAYER M5 ;
        RECT  39.6 51.756 39.624 51.84 ;
    END
  END q[395]
  PIN q[396]
    DIRECTION OUTPUT ;
    USE SIGNAL ;
    PORT
      LAYER M3 ;
        RECT  39.672 51.802 39.69 51.84 ;
    END
  END q[396]
  PIN q[397]
    DIRECTION OUTPUT ;
    USE SIGNAL ;
    PORT
      LAYER M5 ;
        RECT  39.792 51.756 39.816 51.84 ;
    END
  END q[397]
  PIN q[398]
    DIRECTION OUTPUT ;
    USE SIGNAL ;
    PORT
      LAYER M3 ;
        RECT  39.888 51.802 39.906 51.84 ;
    END
  END q[398]
  PIN q[399]
    DIRECTION OUTPUT ;
    USE SIGNAL ;
    PORT
      LAYER M5 ;
        RECT  39.984 51.756 40.008 51.84 ;
    END
  END q[399]
  PIN q[39]
    DIRECTION OUTPUT ;
    USE SIGNAL ;
    PORT
      LAYER M5 ;
        RECT  4.416 51.756 4.44 51.84 ;
    END
  END q[39]
  PIN q[3]
    DIRECTION OUTPUT ;
    USE SIGNAL ;
    PORT
      LAYER M5 ;
        RECT  0.864 51.756 0.888 51.84 ;
    END
  END q[3]
  PIN q[400]
    DIRECTION OUTPUT ;
    USE SIGNAL ;
    PORT
      LAYER M3 ;
        RECT  40.068 51.802 40.086 51.84 ;
    END
  END q[400]
  PIN q[401]
    DIRECTION OUTPUT ;
    USE SIGNAL ;
    PORT
      LAYER M5 ;
        RECT  40.176 51.756 40.2 51.84 ;
    END
  END q[401]
  PIN q[402]
    DIRECTION OUTPUT ;
    USE SIGNAL ;
    PORT
      LAYER M3 ;
        RECT  40.284 51.802 40.302 51.84 ;
    END
  END q[402]
  PIN q[403]
    DIRECTION OUTPUT ;
    USE SIGNAL ;
    PORT
      LAYER M5 ;
        RECT  40.368 51.756 40.392 51.84 ;
    END
  END q[403]
  PIN q[404]
    DIRECTION OUTPUT ;
    USE SIGNAL ;
    PORT
      LAYER M3 ;
        RECT  40.464 51.802 40.482 51.84 ;
    END
  END q[404]
  PIN q[405]
    DIRECTION OUTPUT ;
    USE SIGNAL ;
    PORT
      LAYER M5 ;
        RECT  40.56 51.756 40.584 51.84 ;
    END
  END q[405]
  PIN q[406]
    DIRECTION OUTPUT ;
    USE SIGNAL ;
    PORT
      LAYER M3 ;
        RECT  40.68 51.802 40.698 51.84 ;
    END
  END q[406]
  PIN q[407]
    DIRECTION OUTPUT ;
    USE SIGNAL ;
    PORT
      LAYER M5 ;
        RECT  40.752 51.756 40.776 51.84 ;
    END
  END q[407]
  PIN q[408]
    DIRECTION OUTPUT ;
    USE SIGNAL ;
    PORT
      LAYER M3 ;
        RECT  40.86 51.802 40.878 51.84 ;
    END
  END q[408]
  PIN q[409]
    DIRECTION OUTPUT ;
    USE SIGNAL ;
    PORT
      LAYER M5 ;
        RECT  40.992 51.756 41.016 51.84 ;
    END
  END q[409]
  PIN q[40]
    DIRECTION OUTPUT ;
    USE SIGNAL ;
    PORT
      LAYER M3 ;
        RECT  4.536 51.802 4.554 51.84 ;
    END
  END q[40]
  PIN q[410]
    DIRECTION OUTPUT ;
    USE SIGNAL ;
    PORT
      LAYER M3 ;
        RECT  41.076 51.802 41.094 51.84 ;
    END
  END q[410]
  PIN q[411]
    DIRECTION OUTPUT ;
    USE SIGNAL ;
    PORT
      LAYER M5 ;
        RECT  41.184 51.756 41.208 51.84 ;
    END
  END q[411]
  PIN q[412]
    DIRECTION OUTPUT ;
    USE SIGNAL ;
    PORT
      LAYER M3 ;
        RECT  41.256 51.802 41.274 51.84 ;
    END
  END q[412]
  PIN q[413]
    DIRECTION OUTPUT ;
    USE SIGNAL ;
    PORT
      LAYER M5 ;
        RECT  41.376 51.756 41.4 51.84 ;
    END
  END q[413]
  PIN q[414]
    DIRECTION OUTPUT ;
    USE SIGNAL ;
    PORT
      LAYER M3 ;
        RECT  41.472 51.802 41.49 51.84 ;
    END
  END q[414]
  PIN q[415]
    DIRECTION OUTPUT ;
    USE SIGNAL ;
    PORT
      LAYER M5 ;
        RECT  41.568 51.756 41.592 51.84 ;
    END
  END q[415]
  PIN q[416]
    DIRECTION OUTPUT ;
    USE SIGNAL ;
    PORT
      LAYER M3 ;
        RECT  41.652 51.802 41.67 51.84 ;
    END
  END q[416]
  PIN q[417]
    DIRECTION OUTPUT ;
    USE SIGNAL ;
    PORT
      LAYER M5 ;
        RECT  41.76 51.756 41.784 51.84 ;
    END
  END q[417]
  PIN q[418]
    DIRECTION OUTPUT ;
    USE SIGNAL ;
    PORT
      LAYER M3 ;
        RECT  41.868 51.802 41.886 51.84 ;
    END
  END q[418]
  PIN q[419]
    DIRECTION OUTPUT ;
    USE SIGNAL ;
    PORT
      LAYER M5 ;
        RECT  41.952 51.756 41.976 51.84 ;
    END
  END q[419]
  PIN q[41]
    DIRECTION OUTPUT ;
    USE SIGNAL ;
    PORT
      LAYER M5 ;
        RECT  4.608 51.756 4.632 51.84 ;
    END
  END q[41]
  PIN q[420]
    DIRECTION OUTPUT ;
    USE SIGNAL ;
    PORT
      LAYER M3 ;
        RECT  42.048 51.802 42.066 51.84 ;
    END
  END q[420]
  PIN q[421]
    DIRECTION OUTPUT ;
    USE SIGNAL ;
    PORT
      LAYER M5 ;
        RECT  42.144 51.756 42.168 51.84 ;
    END
  END q[421]
  PIN q[422]
    DIRECTION OUTPUT ;
    USE SIGNAL ;
    PORT
      LAYER M3 ;
        RECT  42.264 51.802 42.282 51.84 ;
    END
  END q[422]
  PIN q[423]
    DIRECTION OUTPUT ;
    USE SIGNAL ;
    PORT
      LAYER M5 ;
        RECT  42.336 51.756 42.36 51.84 ;
    END
  END q[423]
  PIN q[424]
    DIRECTION OUTPUT ;
    USE SIGNAL ;
    PORT
      LAYER M3 ;
        RECT  42.444 51.802 42.462 51.84 ;
    END
  END q[424]
  PIN q[425]
    DIRECTION OUTPUT ;
    USE SIGNAL ;
    PORT
      LAYER M5 ;
        RECT  42.528 51.756 42.552 51.84 ;
    END
  END q[425]
  PIN q[426]
    DIRECTION OUTPUT ;
    USE SIGNAL ;
    PORT
      LAYER M3 ;
        RECT  42.66 51.802 42.678 51.84 ;
    END
  END q[426]
  PIN q[427]
    DIRECTION OUTPUT ;
    USE SIGNAL ;
    PORT
      LAYER M5 ;
        RECT  42.768 51.756 42.792 51.84 ;
    END
  END q[427]
  PIN q[428]
    DIRECTION OUTPUT ;
    USE SIGNAL ;
    PORT
      LAYER M3 ;
        RECT  42.84 51.802 42.858 51.84 ;
    END
  END q[428]
  PIN q[429]
    DIRECTION OUTPUT ;
    USE SIGNAL ;
    PORT
      LAYER M5 ;
        RECT  42.96 51.756 42.984 51.84 ;
    END
  END q[429]
  PIN q[42]
    DIRECTION OUTPUT ;
    USE SIGNAL ;
    PORT
      LAYER M3 ;
        RECT  4.716 51.802 4.734 51.84 ;
    END
  END q[42]
  PIN q[430]
    DIRECTION OUTPUT ;
    USE SIGNAL ;
    PORT
      LAYER M3 ;
        RECT  43.056 51.802 43.074 51.84 ;
    END
  END q[430]
  PIN q[431]
    DIRECTION OUTPUT ;
    USE SIGNAL ;
    PORT
      LAYER M5 ;
        RECT  43.152 51.756 43.176 51.84 ;
    END
  END q[431]
  PIN q[432]
    DIRECTION OUTPUT ;
    USE SIGNAL ;
    PORT
      LAYER M3 ;
        RECT  43.236 51.802 43.254 51.84 ;
    END
  END q[432]
  PIN q[433]
    DIRECTION OUTPUT ;
    USE SIGNAL ;
    PORT
      LAYER M5 ;
        RECT  43.344 51.756 43.368 51.84 ;
    END
  END q[433]
  PIN q[434]
    DIRECTION OUTPUT ;
    USE SIGNAL ;
    PORT
      LAYER M3 ;
        RECT  43.452 51.802 43.47 51.84 ;
    END
  END q[434]
  PIN q[435]
    DIRECTION OUTPUT ;
    USE SIGNAL ;
    PORT
      LAYER M5 ;
        RECT  43.536 51.756 43.56 51.84 ;
    END
  END q[435]
  PIN q[436]
    DIRECTION OUTPUT ;
    USE SIGNAL ;
    PORT
      LAYER M3 ;
        RECT  43.632 51.802 43.65 51.84 ;
    END
  END q[436]
  PIN q[437]
    DIRECTION OUTPUT ;
    USE SIGNAL ;
    PORT
      LAYER M5 ;
        RECT  43.728 51.756 43.752 51.84 ;
    END
  END q[437]
  PIN q[438]
    DIRECTION OUTPUT ;
    USE SIGNAL ;
    PORT
      LAYER M3 ;
        RECT  43.848 51.802 43.866 51.84 ;
    END
  END q[438]
  PIN q[439]
    DIRECTION OUTPUT ;
    USE SIGNAL ;
    PORT
      LAYER M5 ;
        RECT  43.92 51.756 43.944 51.84 ;
    END
  END q[439]
  PIN q[43]
    DIRECTION OUTPUT ;
    USE SIGNAL ;
    PORT
      LAYER M5 ;
        RECT  4.848 51.756 4.872 51.84 ;
    END
  END q[43]
  PIN q[440]
    DIRECTION OUTPUT ;
    USE SIGNAL ;
    PORT
      LAYER M3 ;
        RECT  44.028 51.802 44.046 51.84 ;
    END
  END q[440]
  PIN q[441]
    DIRECTION OUTPUT ;
    USE SIGNAL ;
    PORT
      LAYER M5 ;
        RECT  44.112 51.756 44.136 51.84 ;
    END
  END q[441]
  PIN q[442]
    DIRECTION OUTPUT ;
    USE SIGNAL ;
    PORT
      LAYER M3 ;
        RECT  44.244 51.802 44.262 51.84 ;
    END
  END q[442]
  PIN q[443]
    DIRECTION OUTPUT ;
    USE SIGNAL ;
    PORT
      LAYER M5 ;
        RECT  44.304 51.756 44.328 51.84 ;
    END
  END q[443]
  PIN q[444]
    DIRECTION OUTPUT ;
    USE SIGNAL ;
    PORT
      LAYER M3 ;
        RECT  44.424 51.802 44.442 51.84 ;
    END
  END q[444]
  PIN q[445]
    DIRECTION OUTPUT ;
    USE SIGNAL ;
    PORT
      LAYER M5 ;
        RECT  44.544 51.756 44.568 51.84 ;
    END
  END q[445]
  PIN q[446]
    DIRECTION OUTPUT ;
    USE SIGNAL ;
    PORT
      LAYER M3 ;
        RECT  44.64 51.802 44.658 51.84 ;
    END
  END q[446]
  PIN q[447]
    DIRECTION OUTPUT ;
    USE SIGNAL ;
    PORT
      LAYER M5 ;
        RECT  44.736 51.756 44.76 51.84 ;
    END
  END q[447]
  PIN q[448]
    DIRECTION OUTPUT ;
    USE SIGNAL ;
    PORT
      LAYER M3 ;
        RECT  44.82 51.802 44.838 51.84 ;
    END
  END q[448]
  PIN q[449]
    DIRECTION OUTPUT ;
    USE SIGNAL ;
    PORT
      LAYER M5 ;
        RECT  44.928 51.756 44.952 51.84 ;
    END
  END q[449]
  PIN q[44]
    DIRECTION OUTPUT ;
    USE SIGNAL ;
    PORT
      LAYER M3 ;
        RECT  4.932 51.802 4.95 51.84 ;
    END
  END q[44]
  PIN q[450]
    DIRECTION OUTPUT ;
    USE SIGNAL ;
    PORT
      LAYER M3 ;
        RECT  45.036 51.802 45.054 51.84 ;
    END
  END q[450]
  PIN q[451]
    DIRECTION OUTPUT ;
    USE SIGNAL ;
    PORT
      LAYER M5 ;
        RECT  45.12 51.756 45.144 51.84 ;
    END
  END q[451]
  PIN q[452]
    DIRECTION OUTPUT ;
    USE SIGNAL ;
    PORT
      LAYER M3 ;
        RECT  45.216 51.802 45.234 51.84 ;
    END
  END q[452]
  PIN q[453]
    DIRECTION OUTPUT ;
    USE SIGNAL ;
    PORT
      LAYER M5 ;
        RECT  45.312 51.756 45.336 51.84 ;
    END
  END q[453]
  PIN q[454]
    DIRECTION OUTPUT ;
    USE SIGNAL ;
    PORT
      LAYER M3 ;
        RECT  45.432 51.802 45.45 51.84 ;
    END
  END q[454]
  PIN q[455]
    DIRECTION OUTPUT ;
    USE SIGNAL ;
    PORT
      LAYER M5 ;
        RECT  45.504 51.756 45.528 51.84 ;
    END
  END q[455]
  PIN q[456]
    DIRECTION OUTPUT ;
    USE SIGNAL ;
    PORT
      LAYER M3 ;
        RECT  45.612 51.802 45.63 51.84 ;
    END
  END q[456]
  PIN q[457]
    DIRECTION OUTPUT ;
    USE SIGNAL ;
    PORT
      LAYER M5 ;
        RECT  45.696 51.756 45.72 51.84 ;
    END
  END q[457]
  PIN q[458]
    DIRECTION OUTPUT ;
    USE SIGNAL ;
    PORT
      LAYER M3 ;
        RECT  45.828 51.802 45.846 51.84 ;
    END
  END q[458]
  PIN q[459]
    DIRECTION OUTPUT ;
    USE SIGNAL ;
    PORT
      LAYER M5 ;
        RECT  45.888 51.756 45.912 51.84 ;
    END
  END q[459]
  PIN q[45]
    DIRECTION OUTPUT ;
    USE SIGNAL ;
    PORT
      LAYER M5 ;
        RECT  5.04 51.756 5.064 51.84 ;
    END
  END q[45]
  PIN q[460]
    DIRECTION OUTPUT ;
    USE SIGNAL ;
    PORT
      LAYER M3 ;
        RECT  46.008 51.802 46.026 51.84 ;
    END
  END q[460]
  PIN q[461]
    DIRECTION OUTPUT ;
    USE SIGNAL ;
    PORT
      LAYER M5 ;
        RECT  46.08 51.756 46.104 51.84 ;
    END
  END q[461]
  PIN q[462]
    DIRECTION OUTPUT ;
    USE SIGNAL ;
    PORT
      LAYER M3 ;
        RECT  46.188 51.802 46.206 51.84 ;
    END
  END q[462]
  PIN q[463]
    DIRECTION OUTPUT ;
    USE SIGNAL ;
    PORT
      LAYER M5 ;
        RECT  46.32 51.756 46.344 51.84 ;
    END
  END q[463]
  PIN q[464]
    DIRECTION OUTPUT ;
    USE SIGNAL ;
    PORT
      LAYER M3 ;
        RECT  46.404 51.802 46.422 51.84 ;
    END
  END q[464]
  PIN q[465]
    DIRECTION OUTPUT ;
    USE SIGNAL ;
    PORT
      LAYER M5 ;
        RECT  46.512 51.756 46.536 51.84 ;
    END
  END q[465]
  PIN q[466]
    DIRECTION OUTPUT ;
    USE SIGNAL ;
    PORT
      LAYER M3 ;
        RECT  46.584 51.802 46.602 51.84 ;
    END
  END q[466]
  PIN q[467]
    DIRECTION OUTPUT ;
    USE SIGNAL ;
    PORT
      LAYER M5 ;
        RECT  46.704 51.756 46.728 51.84 ;
    END
  END q[467]
  PIN q[468]
    DIRECTION OUTPUT ;
    USE SIGNAL ;
    PORT
      LAYER M3 ;
        RECT  46.8 51.802 46.818 51.84 ;
    END
  END q[468]
  PIN q[469]
    DIRECTION OUTPUT ;
    USE SIGNAL ;
    PORT
      LAYER M5 ;
        RECT  46.896 51.756 46.92 51.84 ;
    END
  END q[469]
  PIN q[46]
    DIRECTION OUTPUT ;
    USE SIGNAL ;
    PORT
      LAYER M3 ;
        RECT  5.112 51.802 5.13 51.84 ;
    END
  END q[46]
  PIN q[470]
    DIRECTION OUTPUT ;
    USE SIGNAL ;
    PORT
      LAYER M3 ;
        RECT  46.98 51.802 46.998 51.84 ;
    END
  END q[470]
  PIN q[471]
    DIRECTION OUTPUT ;
    USE SIGNAL ;
    PORT
      LAYER M5 ;
        RECT  47.088 51.756 47.112 51.84 ;
    END
  END q[471]
  PIN q[472]
    DIRECTION OUTPUT ;
    USE SIGNAL ;
    PORT
      LAYER M3 ;
        RECT  47.196 51.802 47.214 51.84 ;
    END
  END q[472]
  PIN q[473]
    DIRECTION OUTPUT ;
    USE SIGNAL ;
    PORT
      LAYER M5 ;
        RECT  47.28 51.756 47.304 51.84 ;
    END
  END q[473]
  PIN q[474]
    DIRECTION OUTPUT ;
    USE SIGNAL ;
    PORT
      LAYER M3 ;
        RECT  47.376 51.802 47.394 51.84 ;
    END
  END q[474]
  PIN q[475]
    DIRECTION OUTPUT ;
    USE SIGNAL ;
    PORT
      LAYER M5 ;
        RECT  47.472 51.756 47.496 51.84 ;
    END
  END q[475]
  PIN q[476]
    DIRECTION OUTPUT ;
    USE SIGNAL ;
    PORT
      LAYER M3 ;
        RECT  47.592 51.802 47.61 51.84 ;
    END
  END q[476]
  PIN q[477]
    DIRECTION OUTPUT ;
    USE SIGNAL ;
    PORT
      LAYER M5 ;
        RECT  47.664 51.756 47.688 51.84 ;
    END
  END q[477]
  PIN q[478]
    DIRECTION OUTPUT ;
    USE SIGNAL ;
    PORT
      LAYER M3 ;
        RECT  47.772 51.802 47.79 51.84 ;
    END
  END q[478]
  PIN q[479]
    DIRECTION OUTPUT ;
    USE SIGNAL ;
    PORT
      LAYER M5 ;
        RECT  47.904 51.756 47.928 51.84 ;
    END
  END q[479]
  PIN q[47]
    DIRECTION OUTPUT ;
    USE SIGNAL ;
    PORT
      LAYER M5 ;
        RECT  5.232 51.756 5.256 51.84 ;
    END
  END q[47]
  PIN q[480]
    DIRECTION OUTPUT ;
    USE SIGNAL ;
    PORT
      LAYER M3 ;
        RECT  47.988 51.802 48.006 51.84 ;
    END
  END q[480]
  PIN q[481]
    DIRECTION OUTPUT ;
    USE SIGNAL ;
    PORT
      LAYER M5 ;
        RECT  48.096 51.756 48.12 51.84 ;
    END
  END q[481]
  PIN q[482]
    DIRECTION OUTPUT ;
    USE SIGNAL ;
    PORT
      LAYER M3 ;
        RECT  48.168 51.802 48.186 51.84 ;
    END
  END q[482]
  PIN q[483]
    DIRECTION OUTPUT ;
    USE SIGNAL ;
    PORT
      LAYER M5 ;
        RECT  48.288 51.756 48.312 51.84 ;
    END
  END q[483]
  PIN q[484]
    DIRECTION OUTPUT ;
    USE SIGNAL ;
    PORT
      LAYER M3 ;
        RECT  48.384 51.802 48.402 51.84 ;
    END
  END q[484]
  PIN q[485]
    DIRECTION OUTPUT ;
    USE SIGNAL ;
    PORT
      LAYER M5 ;
        RECT  48.48 51.756 48.504 51.84 ;
    END
  END q[485]
  PIN q[486]
    DIRECTION OUTPUT ;
    USE SIGNAL ;
    PORT
      LAYER M3 ;
        RECT  48.564 51.802 48.582 51.84 ;
    END
  END q[486]
  PIN q[487]
    DIRECTION OUTPUT ;
    USE SIGNAL ;
    PORT
      LAYER M5 ;
        RECT  48.672 51.756 48.696 51.84 ;
    END
  END q[487]
  PIN q[488]
    DIRECTION OUTPUT ;
    USE SIGNAL ;
    PORT
      LAYER M3 ;
        RECT  48.78 51.802 48.798 51.84 ;
    END
  END q[488]
  PIN q[489]
    DIRECTION OUTPUT ;
    USE SIGNAL ;
    PORT
      LAYER M5 ;
        RECT  48.864 51.756 48.888 51.84 ;
    END
  END q[489]
  PIN q[48]
    DIRECTION OUTPUT ;
    USE SIGNAL ;
    PORT
      LAYER M3 ;
        RECT  5.328 51.802 5.346 51.84 ;
    END
  END q[48]
  PIN q[490]
    DIRECTION OUTPUT ;
    USE SIGNAL ;
    PORT
      LAYER M3 ;
        RECT  48.96 51.802 48.978 51.84 ;
    END
  END q[490]
  PIN q[491]
    DIRECTION OUTPUT ;
    USE SIGNAL ;
    PORT
      LAYER M5 ;
        RECT  49.056 51.756 49.08 51.84 ;
    END
  END q[491]
  PIN q[492]
    DIRECTION OUTPUT ;
    USE SIGNAL ;
    PORT
      LAYER M3 ;
        RECT  49.176 51.802 49.194 51.84 ;
    END
  END q[492]
  PIN q[493]
    DIRECTION OUTPUT ;
    USE SIGNAL ;
    PORT
      LAYER M5 ;
        RECT  49.248 51.756 49.272 51.84 ;
    END
  END q[493]
  PIN q[494]
    DIRECTION OUTPUT ;
    USE SIGNAL ;
    PORT
      LAYER M3 ;
        RECT  49.356 51.802 49.374 51.84 ;
    END
  END q[494]
  PIN q[495]
    DIRECTION OUTPUT ;
    USE SIGNAL ;
    PORT
      LAYER M5 ;
        RECT  49.44 51.756 49.464 51.84 ;
    END
  END q[495]
  PIN q[496]
    DIRECTION OUTPUT ;
    USE SIGNAL ;
    PORT
      LAYER M3 ;
        RECT  49.572 51.802 49.59 51.84 ;
    END
  END q[496]
  PIN q[497]
    DIRECTION OUTPUT ;
    USE SIGNAL ;
    PORT
      LAYER M5 ;
        RECT  49.68 51.756 49.704 51.84 ;
    END
  END q[497]
  PIN q[498]
    DIRECTION OUTPUT ;
    USE SIGNAL ;
    PORT
      LAYER M3 ;
        RECT  49.752 51.802 49.77 51.84 ;
    END
  END q[498]
  PIN q[499]
    DIRECTION OUTPUT ;
    USE SIGNAL ;
    PORT
      LAYER M5 ;
        RECT  49.872 51.756 49.896 51.84 ;
    END
  END q[499]
  PIN q[49]
    DIRECTION OUTPUT ;
    USE SIGNAL ;
    PORT
      LAYER M5 ;
        RECT  5.424 51.756 5.448 51.84 ;
    END
  END q[49]
  PIN q[4]
    DIRECTION OUTPUT ;
    USE SIGNAL ;
    PORT
      LAYER M3 ;
        RECT  0.972 51.802 0.99 51.84 ;
    END
  END q[4]
  PIN q[500]
    DIRECTION OUTPUT ;
    USE SIGNAL ;
    PORT
      LAYER M3 ;
        RECT  49.968 51.802 49.986 51.84 ;
    END
  END q[500]
  PIN q[501]
    DIRECTION OUTPUT ;
    USE SIGNAL ;
    PORT
      LAYER M5 ;
        RECT  50.064 51.756 50.088 51.84 ;
    END
  END q[501]
  PIN q[502]
    DIRECTION OUTPUT ;
    USE SIGNAL ;
    PORT
      LAYER M3 ;
        RECT  50.148 51.802 50.166 51.84 ;
    END
  END q[502]
  PIN q[503]
    DIRECTION OUTPUT ;
    USE SIGNAL ;
    PORT
      LAYER M5 ;
        RECT  50.256 51.756 50.28 51.84 ;
    END
  END q[503]
  PIN q[504]
    DIRECTION OUTPUT ;
    USE SIGNAL ;
    PORT
      LAYER M3 ;
        RECT  50.364 51.802 50.382 51.84 ;
    END
  END q[504]
  PIN q[505]
    DIRECTION OUTPUT ;
    USE SIGNAL ;
    PORT
      LAYER M5 ;
        RECT  50.448 51.756 50.472 51.84 ;
    END
  END q[505]
  PIN q[506]
    DIRECTION OUTPUT ;
    USE SIGNAL ;
    PORT
      LAYER M3 ;
        RECT  50.544 51.802 50.562 51.84 ;
    END
  END q[506]
  PIN q[507]
    DIRECTION OUTPUT ;
    USE SIGNAL ;
    PORT
      LAYER M5 ;
        RECT  50.64 51.756 50.664 51.84 ;
    END
  END q[507]
  PIN q[508]
    DIRECTION OUTPUT ;
    USE SIGNAL ;
    PORT
      LAYER M3 ;
        RECT  50.76 51.802 50.778 51.84 ;
    END
  END q[508]
  PIN q[509]
    DIRECTION OUTPUT ;
    USE SIGNAL ;
    PORT
      LAYER M5 ;
        RECT  50.832 51.756 50.856 51.84 ;
    END
  END q[509]
  PIN q[50]
    DIRECTION OUTPUT ;
    USE SIGNAL ;
    PORT
      LAYER M3 ;
        RECT  5.508 51.802 5.526 51.84 ;
    END
  END q[50]
  PIN q[510]
    DIRECTION OUTPUT ;
    USE SIGNAL ;
    PORT
      LAYER M3 ;
        RECT  50.94 51.802 50.958 51.84 ;
    END
  END q[510]
  PIN q[511]
    DIRECTION OUTPUT ;
    USE SIGNAL ;
    PORT
      LAYER M5 ;
        RECT  51.024 51.756 51.048 51.84 ;
    END
  END q[511]
  PIN q[512]
    DIRECTION OUTPUT ;
    USE SIGNAL ;
    PORT
      LAYER M3 ;
        RECT  51.156 51.802 51.174 51.84 ;
    END
  END q[512]
  PIN q[513]
    DIRECTION OUTPUT ;
    USE SIGNAL ;
    PORT
      LAYER M5 ;
        RECT  51.216 51.756 51.24 51.84 ;
    END
  END q[513]
  PIN q[51]
    DIRECTION OUTPUT ;
    USE SIGNAL ;
    PORT
      LAYER M5 ;
        RECT  5.616 51.756 5.64 51.84 ;
    END
  END q[51]
  PIN q[52]
    DIRECTION OUTPUT ;
    USE SIGNAL ;
    PORT
      LAYER M3 ;
        RECT  5.724 51.802 5.742 51.84 ;
    END
  END q[52]
  PIN q[53]
    DIRECTION OUTPUT ;
    USE SIGNAL ;
    PORT
      LAYER M5 ;
        RECT  5.808 51.756 5.832 51.84 ;
    END
  END q[53]
  PIN q[54]
    DIRECTION OUTPUT ;
    USE SIGNAL ;
    PORT
      LAYER M3 ;
        RECT  5.904 51.802 5.922 51.84 ;
    END
  END q[54]
  PIN q[55]
    DIRECTION OUTPUT ;
    USE SIGNAL ;
    PORT
      LAYER M5 ;
        RECT  6 51.756 6.024 51.84 ;
    END
  END q[55]
  PIN q[56]
    DIRECTION OUTPUT ;
    USE SIGNAL ;
    PORT
      LAYER M3 ;
        RECT  6.12 51.802 6.138 51.84 ;
    END
  END q[56]
  PIN q[57]
    DIRECTION OUTPUT ;
    USE SIGNAL ;
    PORT
      LAYER M5 ;
        RECT  6.192 51.756 6.216 51.84 ;
    END
  END q[57]
  PIN q[58]
    DIRECTION OUTPUT ;
    USE SIGNAL ;
    PORT
      LAYER M3 ;
        RECT  6.3 51.802 6.318 51.84 ;
    END
  END q[58]
  PIN q[59]
    DIRECTION OUTPUT ;
    USE SIGNAL ;
    PORT
      LAYER M5 ;
        RECT  6.384 51.756 6.408 51.84 ;
    END
  END q[59]
  PIN q[5]
    DIRECTION OUTPUT ;
    USE SIGNAL ;
    PORT
      LAYER M5 ;
        RECT  1.056 51.756 1.08 51.84 ;
    END
  END q[5]
  PIN q[60]
    DIRECTION OUTPUT ;
    USE SIGNAL ;
    PORT
      LAYER M3 ;
        RECT  6.516 51.802 6.534 51.84 ;
    END
  END q[60]
  PIN q[61]
    DIRECTION OUTPUT ;
    USE SIGNAL ;
    PORT
      LAYER M5 ;
        RECT  6.624 51.756 6.648 51.84 ;
    END
  END q[61]
  PIN q[62]
    DIRECTION OUTPUT ;
    USE SIGNAL ;
    PORT
      LAYER M3 ;
        RECT  6.696 51.802 6.714 51.84 ;
    END
  END q[62]
  PIN q[63]
    DIRECTION OUTPUT ;
    USE SIGNAL ;
    PORT
      LAYER M5 ;
        RECT  6.816 51.756 6.84 51.84 ;
    END
  END q[63]
  PIN q[64]
    DIRECTION OUTPUT ;
    USE SIGNAL ;
    PORT
      LAYER M3 ;
        RECT  6.912 51.802 6.93 51.84 ;
    END
  END q[64]
  PIN q[65]
    DIRECTION OUTPUT ;
    USE SIGNAL ;
    PORT
      LAYER M5 ;
        RECT  7.008 51.756 7.032 51.84 ;
    END
  END q[65]
  PIN q[66]
    DIRECTION OUTPUT ;
    USE SIGNAL ;
    PORT
      LAYER M3 ;
        RECT  7.092 51.802 7.11 51.84 ;
    END
  END q[66]
  PIN q[67]
    DIRECTION OUTPUT ;
    USE SIGNAL ;
    PORT
      LAYER M5 ;
        RECT  7.2 51.756 7.224 51.84 ;
    END
  END q[67]
  PIN q[68]
    DIRECTION OUTPUT ;
    USE SIGNAL ;
    PORT
      LAYER M3 ;
        RECT  7.308 51.802 7.326 51.84 ;
    END
  END q[68]
  PIN q[69]
    DIRECTION OUTPUT ;
    USE SIGNAL ;
    PORT
      LAYER M5 ;
        RECT  7.392 51.756 7.416 51.84 ;
    END
  END q[69]
  PIN q[6]
    DIRECTION OUTPUT ;
    USE SIGNAL ;
    PORT
      LAYER M3 ;
        RECT  1.188 51.802 1.206 51.84 ;
    END
  END q[6]
  PIN q[70]
    DIRECTION OUTPUT ;
    USE SIGNAL ;
    PORT
      LAYER M3 ;
        RECT  7.488 51.802 7.506 51.84 ;
    END
  END q[70]
  PIN q[71]
    DIRECTION OUTPUT ;
    USE SIGNAL ;
    PORT
      LAYER M5 ;
        RECT  7.584 51.756 7.608 51.84 ;
    END
  END q[71]
  PIN q[72]
    DIRECTION OUTPUT ;
    USE SIGNAL ;
    PORT
      LAYER M3 ;
        RECT  7.704 51.802 7.722 51.84 ;
    END
  END q[72]
  PIN q[73]
    DIRECTION OUTPUT ;
    USE SIGNAL ;
    PORT
      LAYER M5 ;
        RECT  7.776 51.756 7.8 51.84 ;
    END
  END q[73]
  PIN q[74]
    DIRECTION OUTPUT ;
    USE SIGNAL ;
    PORT
      LAYER M3 ;
        RECT  7.884 51.802 7.902 51.84 ;
    END
  END q[74]
  PIN q[75]
    DIRECTION OUTPUT ;
    USE SIGNAL ;
    PORT
      LAYER M5 ;
        RECT  7.968 51.756 7.992 51.84 ;
    END
  END q[75]
  PIN q[76]
    DIRECTION OUTPUT ;
    USE SIGNAL ;
    PORT
      LAYER M3 ;
        RECT  8.1 51.802 8.118 51.84 ;
    END
  END q[76]
  PIN q[77]
    DIRECTION OUTPUT ;
    USE SIGNAL ;
    PORT
      LAYER M5 ;
        RECT  8.16 51.756 8.184 51.84 ;
    END
  END q[77]
  PIN q[78]
    DIRECTION OUTPUT ;
    USE SIGNAL ;
    PORT
      LAYER M3 ;
        RECT  8.28 51.802 8.298 51.84 ;
    END
  END q[78]
  PIN q[79]
    DIRECTION OUTPUT ;
    USE SIGNAL ;
    PORT
      LAYER M5 ;
        RECT  8.4 51.756 8.424 51.84 ;
    END
  END q[79]
  PIN q[7]
    DIRECTION OUTPUT ;
    USE SIGNAL ;
    PORT
      LAYER M5 ;
        RECT  1.248 51.756 1.272 51.84 ;
    END
  END q[7]
  PIN q[80]
    DIRECTION OUTPUT ;
    USE SIGNAL ;
    PORT
      LAYER M3 ;
        RECT  8.496 51.802 8.514 51.84 ;
    END
  END q[80]
  PIN q[81]
    DIRECTION OUTPUT ;
    USE SIGNAL ;
    PORT
      LAYER M5 ;
        RECT  8.592 51.756 8.616 51.84 ;
    END
  END q[81]
  PIN q[82]
    DIRECTION OUTPUT ;
    USE SIGNAL ;
    PORT
      LAYER M3 ;
        RECT  8.676 51.802 8.694 51.84 ;
    END
  END q[82]
  PIN q[83]
    DIRECTION OUTPUT ;
    USE SIGNAL ;
    PORT
      LAYER M5 ;
        RECT  8.784 51.756 8.808 51.84 ;
    END
  END q[83]
  PIN q[84]
    DIRECTION OUTPUT ;
    USE SIGNAL ;
    PORT
      LAYER M3 ;
        RECT  8.892 51.802 8.91 51.84 ;
    END
  END q[84]
  PIN q[85]
    DIRECTION OUTPUT ;
    USE SIGNAL ;
    PORT
      LAYER M5 ;
        RECT  8.976 51.756 9 51.84 ;
    END
  END q[85]
  PIN q[86]
    DIRECTION OUTPUT ;
    USE SIGNAL ;
    PORT
      LAYER M3 ;
        RECT  9.072 51.802 9.09 51.84 ;
    END
  END q[86]
  PIN q[87]
    DIRECTION OUTPUT ;
    USE SIGNAL ;
    PORT
      LAYER M5 ;
        RECT  9.168 51.756 9.192 51.84 ;
    END
  END q[87]
  PIN q[88]
    DIRECTION OUTPUT ;
    USE SIGNAL ;
    PORT
      LAYER M3 ;
        RECT  9.288 51.802 9.306 51.84 ;
    END
  END q[88]
  PIN q[89]
    DIRECTION OUTPUT ;
    USE SIGNAL ;
    PORT
      LAYER M5 ;
        RECT  9.36 51.756 9.384 51.84 ;
    END
  END q[89]
  PIN q[8]
    DIRECTION OUTPUT ;
    USE SIGNAL ;
    PORT
      LAYER M3 ;
        RECT  1.368 51.802 1.386 51.84 ;
    END
  END q[8]
  PIN q[90]
    DIRECTION OUTPUT ;
    USE SIGNAL ;
    PORT
      LAYER M3 ;
        RECT  9.468 51.802 9.486 51.84 ;
    END
  END q[90]
  PIN q[91]
    DIRECTION OUTPUT ;
    USE SIGNAL ;
    PORT
      LAYER M5 ;
        RECT  9.552 51.756 9.576 51.84 ;
    END
  END q[91]
  PIN q[92]
    DIRECTION OUTPUT ;
    USE SIGNAL ;
    PORT
      LAYER M3 ;
        RECT  9.684 51.802 9.702 51.84 ;
    END
  END q[92]
  PIN q[93]
    DIRECTION OUTPUT ;
    USE SIGNAL ;
    PORT
      LAYER M5 ;
        RECT  9.744 51.756 9.768 51.84 ;
    END
  END q[93]
  PIN q[94]
    DIRECTION OUTPUT ;
    USE SIGNAL ;
    PORT
      LAYER M3 ;
        RECT  9.864 51.802 9.882 51.84 ;
    END
  END q[94]
  PIN q[95]
    DIRECTION OUTPUT ;
    USE SIGNAL ;
    PORT
      LAYER M5 ;
        RECT  9.936 51.756 9.96 51.84 ;
    END
  END q[95]
  PIN q[96]
    DIRECTION OUTPUT ;
    USE SIGNAL ;
    PORT
      LAYER M3 ;
        RECT  10.044 51.802 10.062 51.84 ;
    END
  END q[96]
  PIN q[97]
    DIRECTION OUTPUT ;
    USE SIGNAL ;
    PORT
      LAYER M5 ;
        RECT  10.176 51.756 10.2 51.84 ;
    END
  END q[97]
  PIN q[98]
    DIRECTION OUTPUT ;
    USE SIGNAL ;
    PORT
      LAYER M3 ;
        RECT  10.26 51.802 10.278 51.84 ;
    END
  END q[98]
  PIN q[99]
    DIRECTION OUTPUT ;
    USE SIGNAL ;
    PORT
      LAYER M5 ;
        RECT  10.368 51.756 10.392 51.84 ;
    END
  END q[99]
  PIN q[9]
    DIRECTION OUTPUT ;
    USE SIGNAL ;
    PORT
      LAYER M5 ;
        RECT  1.488 51.756 1.512 51.84 ;
    END
  END q[9]
  PIN VDD
    DIRECTION INOUT ;
    USE POWER ;
    PORT
      LAYER M5 ;
        RECT  45.792 2.151 45.912 49.689 ;
        RECT  40.392 2.151 40.512 49.689 ;
        RECT  34.992 2.151 35.112 49.689 ;
        RECT  29.592 2.151 29.712 49.689 ;
        RECT  24.192 2.151 24.312 49.689 ;
        RECT  18.792 2.151 18.912 49.689 ;
        RECT  13.392 2.151 13.512 49.689 ;
        RECT  7.992 2.151 8.112 49.689 ;
        RECT  2.592 2.151 2.712 49.689 ;
    END
  END VDD
  PIN VSS
    DIRECTION INOUT ;
    USE GROUND ;
    PORT
      LAYER M5 ;
        RECT  45.6 2.137 45.72 49.703 ;
        RECT  40.2 2.137 40.32 49.703 ;
        RECT  34.8 2.137 34.92 49.703 ;
        RECT  29.4 2.137 29.52 49.703 ;
        RECT  24 2.137 24.12 49.703 ;
        RECT  18.6 2.137 18.72 49.703 ;
        RECT  13.2 2.137 13.32 49.703 ;
        RECT  7.8 2.137 7.92 49.703 ;
        RECT  2.4 2.137 2.52 49.703 ;
    END
  END VSS
  # OT_OBS_CLOSED layer=M5 d_um=1.536 added=112
  OBS
    LAYER RVTN ;
     RECT  2.16 2.16 49.68 2.295 ;
     RECT  2.16 2.565 49.68 2.835 ;
     RECT  2.16 3.105 49.68 3.375 ;
     RECT  2.16 3.645 49.68 3.915 ;
     RECT  2.16 4.185 49.68 4.455 ;
     RECT  2.16 4.725 49.68 4.995 ;
     RECT  2.16 5.265 49.68 5.535 ;
     RECT  2.16 5.805 49.68 6.075 ;
     RECT  2.16 6.345 49.68 6.615 ;
     RECT  2.16 6.885 49.68 7.155 ;
     RECT  2.16 7.425 49.68 7.695 ;
     RECT  2.16 7.965 49.68 8.235 ;
     RECT  2.16 8.505 49.68 8.775 ;
     RECT  2.16 9.045 49.68 9.315 ;
     RECT  2.16 9.585 49.68 9.855 ;
     RECT  2.16 10.125 49.68 10.395 ;
     RECT  2.16 10.665 49.68 10.935 ;
     RECT  2.16 11.205 49.68 11.475 ;
     RECT  2.16 11.745 49.68 12.015 ;
     RECT  2.16 12.285 49.68 12.555 ;
     RECT  2.16 12.825 49.68 13.095 ;
     RECT  2.16 13.365 49.68 13.635 ;
     RECT  2.16 13.905 49.68 14.175 ;
     RECT  2.16 14.445 49.68 14.715 ;
     RECT  2.16 14.985 49.68 15.255 ;
     RECT  2.16 15.525 49.68 15.795 ;
     RECT  2.16 16.065 49.68 16.335 ;
     RECT  2.16 16.605 49.68 16.875 ;
     RECT  2.16 17.145 49.68 17.415 ;
     RECT  2.16 17.685 49.68 17.955 ;
     RECT  2.16 18.225 49.68 18.495 ;
     RECT  2.16 18.765 49.68 19.035 ;
     RECT  2.16 19.305 49.68 19.575 ;
     RECT  2.16 19.845 49.68 20.115 ;
     RECT  2.16 20.385 49.68 20.655 ;
     RECT  2.16 20.925 49.68 21.195 ;
     RECT  2.16 21.465 49.68 21.735 ;
     RECT  2.16 22.005 49.68 22.275 ;
     RECT  2.16 22.545 49.68 22.815 ;
     RECT  2.16 23.085 49.68 23.355 ;
     RECT  2.16 23.625 49.68 23.895 ;
     RECT  2.16 24.165 49.68 24.435 ;
     RECT  2.16 24.705 49.68 24.975 ;
     RECT  2.16 25.245 49.68 25.515 ;
     RECT  2.16 25.785 49.68 26.055 ;
     RECT  2.16 26.325 49.68 26.595 ;
     RECT  2.16 26.865 49.68 27.135 ;
     RECT  2.16 27.405 49.68 27.675 ;
     RECT  2.16 27.945 49.68 28.215 ;
     RECT  2.16 28.485 49.68 28.755 ;
     RECT  2.16 29.025 49.68 29.295 ;
     RECT  2.16 29.565 49.68 29.835 ;
     RECT  2.16 30.105 49.68 30.375 ;
     RECT  2.16 30.645 49.68 30.915 ;
     RECT  2.16 31.185 49.68 31.455 ;
     RECT  2.16 31.725 49.68 31.995 ;
     RECT  2.16 32.265 49.68 32.535 ;
     RECT  2.16 32.805 49.68 33.075 ;
     RECT  2.16 33.345 49.68 33.615 ;
     RECT  2.16 33.885 49.68 34.155 ;
     RECT  2.16 34.425 49.68 34.695 ;
     RECT  2.16 34.965 49.68 35.235 ;
     RECT  2.16 35.505 49.68 35.775 ;
     RECT  2.16 36.045 49.68 36.315 ;
     RECT  2.16 36.585 49.68 36.855 ;
     RECT  2.16 37.125 49.68 37.395 ;
     RECT  2.16 37.665 49.68 37.935 ;
     RECT  2.16 38.205 49.68 38.475 ;
     RECT  2.16 38.745 49.68 39.015 ;
     RECT  2.16 39.285 49.68 39.555 ;
     RECT  2.16 39.825 49.68 40.095 ;
     RECT  2.16 40.365 49.68 40.635 ;
     RECT  2.16 40.905 49.68 41.175 ;
     RECT  2.16 41.445 49.68 41.715 ;
     RECT  2.16 41.985 49.68 42.255 ;
     RECT  2.16 42.525 49.68 42.795 ;
     RECT  2.16 43.065 49.68 43.335 ;
     RECT  2.16 43.605 49.68 43.875 ;
     RECT  2.16 44.145 49.68 44.415 ;
     RECT  2.16 44.685 49.68 44.955 ;
     RECT  2.16 45.225 49.68 45.495 ;
     RECT  2.16 45.765 49.68 46.035 ;
     RECT  2.16 46.305 49.68 46.575 ;
     RECT  2.16 46.845 49.68 47.115 ;
     RECT  2.16 47.385 49.68 47.655 ;
     RECT  2.16 47.925 49.68 48.195 ;
     RECT  2.16 48.465 49.68 48.735 ;
     RECT  2.16 49.005 49.68 49.275 ;
     RECT  2.16 49.545 49.68 49.68 ;
    LAYER RVTP ;
     RECT  2.16 2.295 49.68 2.565 ;
     RECT  2.16 2.835 49.68 3.105 ;
     RECT  2.16 3.375 49.68 3.645 ;
     RECT  2.16 3.915 49.68 4.185 ;
     RECT  2.16 4.455 49.68 4.725 ;
     RECT  2.16 4.995 49.68 5.265 ;
     RECT  2.16 5.535 49.68 5.805 ;
     RECT  2.16 6.075 49.68 6.345 ;
     RECT  2.16 6.615 49.68 6.885 ;
     RECT  2.16 7.155 49.68 7.425 ;
     RECT  2.16 7.695 49.68 7.965 ;
     RECT  2.16 8.235 49.68 8.505 ;
     RECT  2.16 8.775 49.68 9.045 ;
     RECT  2.16 9.315 49.68 9.585 ;
     RECT  2.16 9.855 49.68 10.125 ;
     RECT  2.16 10.395 49.68 10.665 ;
     RECT  2.16 10.935 49.68 11.205 ;
     RECT  2.16 11.475 49.68 11.745 ;
     RECT  2.16 12.015 49.68 12.285 ;
     RECT  2.16 12.555 49.68 12.825 ;
     RECT  2.16 13.095 49.68 13.365 ;
     RECT  2.16 13.635 49.68 13.905 ;
     RECT  2.16 14.175 49.68 14.445 ;
     RECT  2.16 14.715 49.68 14.985 ;
     RECT  2.16 15.255 49.68 15.525 ;
     RECT  2.16 15.795 49.68 16.065 ;
     RECT  2.16 16.335 49.68 16.605 ;
     RECT  2.16 16.875 49.68 17.145 ;
     RECT  2.16 17.415 49.68 17.685 ;
     RECT  2.16 17.955 49.68 18.225 ;
     RECT  2.16 18.495 49.68 18.765 ;
     RECT  2.16 19.035 49.68 19.305 ;
     RECT  2.16 19.575 49.68 19.845 ;
     RECT  2.16 20.115 49.68 20.385 ;
     RECT  2.16 20.655 49.68 20.925 ;
     RECT  2.16 21.195 49.68 21.465 ;
     RECT  2.16 21.735 49.68 22.005 ;
     RECT  2.16 22.275 49.68 22.545 ;
     RECT  2.16 22.815 49.68 23.085 ;
     RECT  2.16 23.355 49.68 23.625 ;
     RECT  2.16 23.895 49.68 24.165 ;
     RECT  2.16 24.435 49.68 24.705 ;
     RECT  2.16 24.975 49.68 25.245 ;
     RECT  2.16 25.515 49.68 25.785 ;
     RECT  2.16 26.055 49.68 26.325 ;
     RECT  2.16 26.595 49.68 26.865 ;
     RECT  2.16 27.135 49.68 27.405 ;
     RECT  2.16 27.675 49.68 27.945 ;
     RECT  2.16 28.215 49.68 28.485 ;
     RECT  2.16 28.755 49.68 29.025 ;
     RECT  2.16 29.295 49.68 29.565 ;
     RECT  2.16 29.835 49.68 30.105 ;
     RECT  2.16 30.375 49.68 30.645 ;
     RECT  2.16 30.915 49.68 31.185 ;
     RECT  2.16 31.455 49.68 31.725 ;
     RECT  2.16 31.995 49.68 32.265 ;
     RECT  2.16 32.535 49.68 32.805 ;
     RECT  2.16 33.075 49.68 33.345 ;
     RECT  2.16 33.615 49.68 33.885 ;
     RECT  2.16 34.155 49.68 34.425 ;
     RECT  2.16 34.695 49.68 34.965 ;
     RECT  2.16 35.235 49.68 35.505 ;
     RECT  2.16 35.775 49.68 36.045 ;
     RECT  2.16 36.315 49.68 36.585 ;
     RECT  2.16 36.855 49.68 37.125 ;
     RECT  2.16 37.395 49.68 37.665 ;
     RECT  2.16 37.935 49.68 38.205 ;
     RECT  2.16 38.475 49.68 38.745 ;
     RECT  2.16 39.015 49.68 39.285 ;
     RECT  2.16 39.555 49.68 39.825 ;
     RECT  2.16 40.095 49.68 40.365 ;
     RECT  2.16 40.635 49.68 40.905 ;
     RECT  2.16 41.175 49.68 41.445 ;
     RECT  2.16 41.715 49.68 41.985 ;
     RECT  2.16 42.255 49.68 42.525 ;
     RECT  2.16 42.795 49.68 43.065 ;
     RECT  2.16 43.335 49.68 43.605 ;
     RECT  2.16 43.875 49.68 44.145 ;
     RECT  2.16 44.415 49.68 44.685 ;
     RECT  2.16 44.955 49.68 45.225 ;
     RECT  2.16 45.495 49.68 45.765 ;
     RECT  2.16 46.035 49.68 46.305 ;
     RECT  2.16 46.575 49.68 46.845 ;
     RECT  2.16 47.115 49.68 47.385 ;
     RECT  2.16 47.655 49.68 47.925 ;
     RECT  2.16 48.195 49.68 48.465 ;
     RECT  2.16 48.735 49.68 49.005 ;
     RECT  2.16 49.275 49.68 49.545 ;
    LAYER M1 ;
     RECT  2.16 2.151 49.68 49.689 ;
    LAYER M2 ;
     RECT  0.787 18.972 0.967 18.99 ;
     RECT  0.571 19.854 0.967 19.872 ;
     RECT  0.787 48.78 0.967 48.798 ;
     RECT  0.967 48.096 1.111 48.798 ;
     RECT  0.571 49.554 1.111 49.572 ;
     RECT  0.967 18.972 1.543 19.872 ;
     RECT  1.147 20.862 1.543 20.88 ;
     RECT  1.363 47.286 1.579 47.304 ;
     RECT  1.111 48.096 1.579 49.572 ;
     RECT  1.543 18.972 1.723 20.88 ;
     RECT  1.723 18.81 1.759 21.42 ;
     RECT  1.759 18.702 1.795 21.42 ;
     RECT  1.795 18.702 1.831 21.69 ;
     RECT  1.867 27.072 1.939 27.09 ;
     RECT  1.831 18.702 2.011 22.032 ;
     RECT  1.579 47.286 2.011 49.572 ;
     RECT  2.011 46.89 2.047 49.572 ;
     RECT  1.939 45.306 2.083 45.324 ;
     RECT  1.975 41.256 2.119 41.274 ;
     RECT  1.867 0.036 2.147 0.054 ;
     RECT  2.011 18.702 2.16 22.104 ;
     RECT  1.939 23.832 2.16 23.85 ;
     RECT  1.939 26.406 2.16 27.09 ;
     RECT  2.119 40.536 2.16 41.274 ;
     RECT  1.831 43.002 2.16 43.02 ;
     RECT  2.083 45.306 2.16 45.684 ;
     RECT  2.047 46.476 2.16 49.572 ;
     RECT  2.335 50.706 2.579 50.724 ;
     RECT  2.16 2.151 2.695 49.689 ;
     RECT  2.695 1.728 2.867 49.689 ;
     RECT  2.911 0.036 3.443 0.054 ;
     RECT  3.523 50.706 3.731 50.724 ;
     RECT  4.243 0.072 4.379 0.09 ;
     RECT  4.927 50.706 5.323 50.724 ;
     RECT  5.323 50.634 5.423 50.724 ;
     RECT  4.639 0.036 5.531 0.054 ;
     RECT  5.971 0.531 6.107 0.549 ;
     RECT  5.423 50.706 7.087 50.724 ;
     RECT  7.087 50.67 7.223 50.724 ;
     RECT  2.867 2.151 7.555 49.689 ;
     RECT  7.735 1.116 7.871 1.134 ;
     RECT  7.555 2.151 7.907 49.77 ;
     RECT  6.907 0.036 7.979 0.054 ;
     RECT  7.223 50.706 8.095 50.724 ;
     RECT  8.095 50.634 8.671 50.724 ;
     RECT  8.671 50.598 8.915 50.724 ;
     RECT  8.915 50.634 9.275 50.724 ;
     RECT  7.907 2.151 10.039 49.689 ;
     RECT  10.039 1.656 10.175 49.689 ;
     RECT  9.275 50.706 11.047 50.724 ;
     RECT  11.047 50.67 11.147 50.724 ;
     RECT  10.175 2.151 11.227 49.689 ;
     RECT  11.227 2.151 11.327 49.734 ;
     RECT  11.147 50.706 11.363 50.724 ;
     RECT  9.067 0.036 11.651 0.054 ;
     RECT  11.767 51.786 11.867 51.804 ;
     RECT  11.327 2.151 12.667 49.689 ;
     RECT  12.667 1.728 13.099 49.689 ;
     RECT  13.099 1.728 13.235 49.77 ;
     RECT  13.235 1.728 13.415 49.689 ;
     RECT  12.451 0.036 13.783 0.054 ;
     RECT  13.783 0.036 13.991 0.279 ;
     RECT  13.991 0.036 14.027 0.198 ;
     RECT  14.027 0.036 14.243 0.054 ;
     RECT  13.415 2.151 14.791 49.689 ;
     RECT  12.235 50.706 14.791 50.724 ;
     RECT  14.791 2.151 15.287 50.724 ;
     RECT  15.583 51.786 15.971 51.804 ;
     RECT  15.691 0.036 16.051 0.054 ;
     RECT  15.287 50.706 16.195 50.724 ;
     RECT  16.195 50.634 16.295 50.724 ;
     RECT  16.051 0.036 16.331 0.126 ;
     RECT  16.331 0.036 16.511 0.054 ;
     RECT  16.295 50.67 16.943 50.724 ;
     RECT  16.943 50.706 16.979 50.724 ;
     RECT  15.287 2.151 18.139 49.689 ;
     RECT  17.419 0.036 18.463 0.054 ;
     RECT  18.139 1.728 18.635 49.689 ;
     RECT  18.463 0.036 18.851 0.126 ;
     RECT  18.851 0.036 19.463 0.054 ;
     RECT  20.911 51.786 21.011 51.804 ;
     RECT  21.127 0.036 21.307 0.054 ;
     RECT  21.307 0.036 21.443 0.09 ;
     RECT  21.127 50.706 22.027 50.724 ;
     RECT  18.635 2.151 22.315 49.689 ;
     RECT  22.027 50.634 22.315 50.724 ;
     RECT  22.315 2.151 22.415 50.724 ;
     RECT  21.919 51.786 22.595 51.804 ;
     RECT  21.443 0.036 23.143 0.054 ;
     RECT  23.179 51.678 23.315 51.696 ;
     RECT  23.143 0.036 23.495 0.126 ;
     RECT  22.415 50.706 24.295 50.724 ;
     RECT  24.295 50.67 24.359 50.724 ;
     RECT  23.495 0.036 24.431 0.054 ;
     RECT  24.439 0.108 24.539 0.126 ;
     RECT  24.359 50.706 25.267 50.724 ;
     RECT  25.447 51.786 25.583 51.804 ;
     RECT  25.267 50.67 25.915 50.724 ;
     RECT  25.915 50.634 26.087 50.724 ;
     RECT  26.087 50.706 26.239 50.724 ;
     RECT  26.239 50.706 26.447 50.814 ;
     RECT  25.231 0.036 27.419 0.054 ;
     RECT  27.643 51.786 27.815 51.804 ;
     RECT  26.447 50.706 28.615 50.724 ;
     RECT  28.615 50.634 28.751 50.724 ;
     RECT  28.723 51.786 29.039 51.804 ;
     RECT  28.751 50.706 29.803 50.724 ;
     RECT  29.479 0.036 31.451 0.054 ;
     RECT  29.803 50.634 32.243 50.724 ;
     RECT  32.243 50.706 32.927 50.724 ;
     RECT  33.151 51.714 33.287 51.732 ;
     RECT  32.971 0.036 33.827 0.054 ;
     RECT  33.763 51.786 33.863 51.804 ;
     RECT  34.339 50.706 34.403 50.724 ;
     RECT  22.415 2.151 34.915 49.689 ;
     RECT  34.915 2.07 35.231 49.689 ;
     RECT  35.095 0.036 35.267 0.054 ;
     RECT  35.131 50.706 35.707 50.724 ;
     RECT  35.707 50.634 35.879 50.724 ;
     RECT  36.139 51.786 36.383 51.804 ;
     RECT  35.879 50.706 37.327 50.724 ;
     RECT  37.327 50.706 37.463 50.814 ;
     RECT  38.011 51.786 38.147 51.804 ;
     RECT  37.463 50.706 38.299 50.724 ;
     RECT  38.299 50.634 38.543 50.724 ;
     RECT  36.823 0.036 39.227 0.054 ;
     RECT  38.543 50.706 39.227 50.724 ;
     RECT  39.487 51.786 39.731 51.804 ;
     RECT  35.231 2.151 39.811 49.689 ;
     RECT  39.811 1.728 39.983 49.689 ;
     RECT  40.063 0.108 40.099 0.126 ;
     RECT  40.099 0.036 40.379 0.126 ;
     RECT  40.063 50.706 40.675 50.724 ;
     RECT  40.379 0.036 40.955 0.054 ;
     RECT  40.675 50.634 41.315 50.724 ;
     RECT  41.683 0.036 42.719 0.054 ;
     RECT  42.835 0.531 42.971 0.549 ;
     RECT  41.315 50.706 44.915 50.724 ;
     RECT  43.627 0.036 45.275 0.054 ;
     RECT  39.983 2.151 45.607 49.689 ;
     RECT  45.607 2.151 45.751 49.77 ;
     RECT  45.751 2.034 45.887 49.77 ;
     RECT  45.887 2.151 46.003 49.77 ;
     RECT  46.003 2.151 46.103 49.842 ;
     RECT  46.183 51.678 46.319 51.696 ;
     RECT  46.327 0.306 46.463 0.324 ;
     RECT  46.399 51.786 46.499 51.804 ;
     RECT  46.103 2.151 46.975 49.689 ;
     RECT  46.975 2.151 47.075 50.229 ;
     RECT  47.335 0.036 47.479 0.054 ;
     RECT  47.479 0.036 47.759 0.126 ;
     RECT  47.759 0.036 48.011 0.054 ;
     RECT  47.075 2.151 48.595 49.689 ;
     RECT  48.595 2.151 48.803 50.148 ;
     RECT  49.063 0.036 49.487 0.054 ;
     RECT  48.803 2.151 49.68 49.689 ;
     RECT  49.68 17.928 49.703 18.756 ;
     RECT  49.68 45.846 49.775 45.864 ;
     RECT  49.68 19.548 49.883 19.566 ;
     RECT  49.703 17.928 49.919 18.018 ;
     RECT  49.68 49.284 49.991 49.464 ;
     RECT  49.68 16.92 50.063 16.938 ;
     RECT  49.68 47.286 50.171 48.456 ;
     RECT  49.991 49.446 50.207 49.464 ;
     RECT  49.919 18 50.279 18.018 ;
     RECT  50.171 47.286 50.567 48.384 ;
     RECT  50.567 47.394 50.783 48.384 ;
     RECT  50.783 48.006 50.963 48.384 ;
     RECT  50.963 48.006 51.179 48.024 ;
    LAYER M3 ;
     RECT  0.594 0.012 0.792 0.038 ;
     RECT  0.81 0.012 0.972 0.038 ;
     RECT  0.99 0.012 1.152 0.038 ;
     RECT  1.17 0.012 1.368 0.038 ;
     RECT  1.386 0.012 1.548 0.038 ;
     RECT  1.566 0.012 1.728 0.038 ;
     RECT  1.746 0.012 1.944 0.038 ;
     RECT  1.962 0.012 2.124 0.038 ;
     RECT  2.142 0.012 2.34 0.038 ;
     RECT  2.358 0.012 2.52 0.038 ;
     RECT  2.538 0.012 2.7 0.038 ;
     RECT  2.718 0.012 2.916 0.038 ;
     RECT  2.934 0.012 3.096 0.038 ;
     RECT  3.114 0.012 3.312 0.038 ;
     RECT  3.33 0.012 3.492 0.038 ;
     RECT  3.51 0.012 3.672 0.038 ;
     RECT  3.69 0.012 3.888 0.038 ;
     RECT  3.906 0.012 4.068 0.038 ;
     RECT  4.086 0.012 4.284 0.038 ;
     RECT  4.302 0.012 4.464 0.038 ;
     RECT  4.482 0.012 4.644 0.038 ;
     RECT  4.662 0.012 4.86 0.038 ;
     RECT  4.878 0.012 5.04 0.038 ;
     RECT  5.058 0.012 5.22 0.038 ;
     RECT  5.238 0.012 5.436 0.038 ;
     RECT  5.454 0.012 5.616 0.038 ;
     RECT  5.634 0.012 5.832 0.038 ;
     RECT  5.85 0.012 6.012 0.038 ;
     RECT  6.03 0.012 6.192 0.038 ;
     RECT  6.21 0.012 6.408 0.038 ;
     RECT  6.426 0.012 6.588 0.038 ;
     RECT  6.606 0.012 6.804 0.038 ;
     RECT  6.822 0.012 6.984 0.038 ;
     RECT  7.002 0.012 7.164 0.038 ;
     RECT  7.182 0.012 7.38 0.038 ;
     RECT  7.398 0.012 7.56 0.038 ;
     RECT  7.578 0.012 7.776 0.038 ;
     RECT  7.794 0.012 7.956 0.038 ;
     RECT  7.974 0.012 8.136 0.038 ;
     RECT  8.154 0.012 8.352 0.038 ;
     RECT  8.37 0.012 8.532 0.038 ;
     RECT  8.55 0.012 8.712 0.038 ;
     RECT  8.73 0.012 8.928 0.038 ;
     RECT  8.946 0.012 9.108 0.038 ;
     RECT  9.126 0.012 9.324 0.038 ;
     RECT  9.342 0.012 9.504 0.038 ;
     RECT  9.522 0.012 9.684 0.038 ;
     RECT  9.702 0.012 9.9 0.038 ;
     RECT  9.918 0.012 10.08 0.038 ;
     RECT  10.098 0.012 10.296 0.038 ;
     RECT  10.314 0.012 10.476 0.038 ;
     RECT  10.494 0.012 10.656 0.038 ;
     RECT  10.674 0.012 10.872 0.038 ;
     RECT  10.89 0.012 11.052 0.038 ;
     RECT  11.07 0.012 11.268 0.038 ;
     RECT  11.286 0.012 11.448 0.038 ;
     RECT  11.466 0.012 11.628 0.038 ;
     RECT  11.646 0.012 11.844 0.038 ;
     RECT  11.862 0.012 12.024 0.038 ;
     RECT  12.042 0.012 12.204 0.038 ;
     RECT  12.222 0.012 12.42 0.038 ;
     RECT  12.438 0.012 12.6 0.038 ;
     RECT  12.618 0.012 12.816 0.038 ;
     RECT  12.834 0.012 12.996 0.038 ;
     RECT  13.014 0.012 13.176 0.038 ;
     RECT  13.194 0.012 13.392 0.038 ;
     RECT  13.41 0.012 13.572 0.038 ;
     RECT  13.59 0.012 13.788 0.038 ;
     RECT  13.806 0.012 13.968 0.038 ;
     RECT  13.986 0.012 14.148 0.038 ;
     RECT  14.166 0.012 14.364 0.038 ;
     RECT  14.382 0.012 14.544 0.038 ;
     RECT  14.562 0.012 14.76 0.038 ;
     RECT  14.778 0.012 14.94 0.038 ;
     RECT  14.958 0.012 15.12 0.038 ;
     RECT  15.138 0.012 15.336 0.038 ;
     RECT  15.354 0.012 15.516 0.038 ;
     RECT  15.534 0.012 15.696 0.038 ;
     RECT  15.714 0.012 15.912 0.038 ;
     RECT  15.93 0.012 16.092 0.038 ;
     RECT  16.11 0.012 16.308 0.038 ;
     RECT  16.326 0.012 16.488 0.038 ;
     RECT  16.506 0.012 16.668 0.038 ;
     RECT  16.686 0.012 16.884 0.038 ;
     RECT  16.902 0.012 17.064 0.038 ;
     RECT  17.082 0.012 17.28 0.038 ;
     RECT  17.298 0.012 17.46 0.038 ;
     RECT  17.478 0.012 17.64 0.038 ;
     RECT  17.658 0.012 17.856 0.038 ;
     RECT  17.874 0.012 18.036 0.038 ;
     RECT  18.054 0.012 18.252 0.038 ;
     RECT  18.27 0.012 18.432 0.038 ;
     RECT  18.45 0.012 18.612 0.038 ;
     RECT  18.63 0.012 18.828 0.038 ;
     RECT  18.846 0.012 19.008 0.038 ;
     RECT  19.026 0.012 19.188 0.038 ;
     RECT  19.206 0.012 19.404 0.038 ;
     RECT  19.422 0.012 19.584 0.038 ;
     RECT  19.602 0.012 19.8 0.038 ;
     RECT  19.818 0.012 19.98 0.038 ;
     RECT  19.998 0.012 20.16 0.038 ;
     RECT  20.178 0.012 20.376 0.038 ;
     RECT  20.394 0.012 20.556 0.038 ;
     RECT  20.574 0.012 20.772 0.038 ;
     RECT  20.79 0.012 20.952 0.038 ;
     RECT  20.97 0.012 21.132 0.038 ;
     RECT  21.15 0.012 21.348 0.038 ;
     RECT  21.366 0.012 21.528 0.038 ;
     RECT  21.546 0.012 21.744 0.038 ;
     RECT  21.762 0.012 21.924 0.038 ;
     RECT  21.942 0.012 22.104 0.038 ;
     RECT  22.122 0.012 22.32 0.038 ;
     RECT  22.338 0.012 22.5 0.038 ;
     RECT  22.518 0.012 22.68 0.038 ;
     RECT  22.698 0.012 22.896 0.038 ;
     RECT  22.914 0.012 23.076 0.038 ;
     RECT  23.094 0.012 23.292 0.038 ;
     RECT  23.31 0.012 23.472 0.038 ;
     RECT  23.49 0.012 23.652 0.038 ;
     RECT  23.67 0.012 23.868 0.038 ;
     RECT  23.886 0.012 24.048 0.038 ;
     RECT  24.066 0.012 24.264 0.038 ;
     RECT  24.282 0.012 24.444 0.038 ;
     RECT  24.462 0.012 24.624 0.038 ;
     RECT  24.642 0.012 24.84 0.038 ;
     RECT  24.858 0.012 25.02 0.038 ;
     RECT  25.038 0.012 25.236 0.038 ;
     RECT  25.254 0.012 25.416 0.038 ;
     RECT  25.434 0.012 25.596 0.038 ;
     RECT  25.614 0.012 25.812 0.038 ;
     RECT  25.83 0.012 25.992 0.038 ;
     RECT  26.01 0.012 26.172 0.038 ;
     RECT  26.19 0.012 26.388 0.038 ;
     RECT  26.406 0.012 26.568 0.038 ;
     RECT  26.586 0.012 26.784 0.038 ;
     RECT  26.802 0.012 26.964 0.038 ;
     RECT  26.982 0.012 27.144 0.038 ;
     RECT  27.162 0.012 27.36 0.038 ;
     RECT  27.378 0.012 27.54 0.038 ;
     RECT  27.558 0.012 27.756 0.038 ;
     RECT  27.774 0.012 27.936 0.038 ;
     RECT  27.954 0.012 28.116 0.038 ;
     RECT  28.134 0.012 28.332 0.038 ;
     RECT  28.35 0.012 28.512 0.038 ;
     RECT  28.53 0.012 28.728 0.038 ;
     RECT  28.746 0.012 28.908 0.038 ;
     RECT  28.926 0.012 29.088 0.038 ;
     RECT  29.106 0.012 29.304 0.038 ;
     RECT  29.322 0.012 29.484 0.038 ;
     RECT  29.502 0.012 29.664 0.038 ;
     RECT  29.682 0.012 29.88 0.038 ;
     RECT  29.898 0.012 30.06 0.038 ;
     RECT  30.078 0.012 30.276 0.038 ;
     RECT  30.294 0.012 30.456 0.038 ;
     RECT  30.474 0.012 30.636 0.038 ;
     RECT  30.654 0.012 30.852 0.038 ;
     RECT  30.87 0.012 31.032 0.038 ;
     RECT  31.05 0.012 31.248 0.038 ;
     RECT  31.266 0.012 31.428 0.038 ;
     RECT  31.446 0.012 31.608 0.038 ;
     RECT  31.626 0.012 31.824 0.038 ;
     RECT  31.842 0.012 32.004 0.038 ;
     RECT  32.022 0.012 32.22 0.038 ;
     RECT  32.238 0.012 32.4 0.038 ;
     RECT  32.418 0.012 32.58 0.038 ;
     RECT  32.598 0.012 32.796 0.038 ;
     RECT  32.814 0.012 32.976 0.038 ;
     RECT  32.994 0.012 33.156 0.038 ;
     RECT  33.174 0.012 33.372 0.038 ;
     RECT  33.39 0.012 33.552 0.038 ;
     RECT  33.57 0.012 33.768 0.038 ;
     RECT  33.786 0.012 33.948 0.038 ;
     RECT  33.966 0.012 34.128 0.038 ;
     RECT  34.146 0.012 34.344 0.038 ;
     RECT  34.362 0.012 34.524 0.038 ;
     RECT  34.542 0.012 34.74 0.038 ;
     RECT  34.758 0.012 34.92 0.038 ;
     RECT  34.938 0.012 35.1 0.038 ;
     RECT  35.118 0.012 35.316 0.038 ;
     RECT  35.334 0.012 35.496 0.038 ;
     RECT  35.514 0.012 35.712 0.038 ;
     RECT  35.73 0.012 35.892 0.038 ;
     RECT  35.91 0.012 36.072 0.038 ;
     RECT  36.09 0.012 36.288 0.038 ;
     RECT  36.306 0.012 36.468 0.038 ;
     RECT  36.486 0.012 36.648 0.038 ;
     RECT  36.666 0.012 36.864 0.038 ;
     RECT  36.882 0.012 37.044 0.038 ;
     RECT  37.062 0.012 37.26 0.038 ;
     RECT  37.278 0.012 37.44 0.038 ;
     RECT  37.458 0.012 37.62 0.038 ;
     RECT  37.638 0.012 37.836 0.038 ;
     RECT  37.854 0.012 38.016 0.038 ;
     RECT  38.034 0.012 38.232 0.038 ;
     RECT  38.25 0.012 38.412 0.038 ;
     RECT  38.43 0.012 38.592 0.038 ;
     RECT  38.61 0.012 38.808 0.038 ;
     RECT  38.826 0.012 38.988 0.038 ;
     RECT  39.006 0.012 39.204 0.038 ;
     RECT  39.222 0.012 39.384 0.038 ;
     RECT  39.402 0.012 39.564 0.038 ;
     RECT  39.582 0.012 39.78 0.038 ;
     RECT  39.798 0.012 39.96 0.038 ;
     RECT  39.978 0.012 40.14 0.038 ;
     RECT  40.158 0.012 40.356 0.038 ;
     RECT  40.374 0.012 40.536 0.038 ;
     RECT  40.554 0.012 40.752 0.038 ;
     RECT  40.77 0.012 40.932 0.038 ;
     RECT  40.95 0.012 41.112 0.038 ;
     RECT  41.13 0.012 41.328 0.038 ;
     RECT  41.346 0.012 41.508 0.038 ;
     RECT  41.526 0.012 41.724 0.038 ;
     RECT  41.742 0.012 41.904 0.038 ;
     RECT  41.922 0.012 42.084 0.038 ;
     RECT  42.102 0.012 42.3 0.038 ;
     RECT  42.318 0.012 42.48 0.038 ;
     RECT  42.498 0.012 42.696 0.038 ;
     RECT  42.714 0.012 42.876 0.038 ;
     RECT  42.894 0.012 43.056 0.038 ;
     RECT  43.074 0.012 43.272 0.038 ;
     RECT  43.29 0.012 43.452 0.038 ;
     RECT  43.47 0.012 43.632 0.038 ;
     RECT  43.65 0.012 43.848 0.038 ;
     RECT  43.866 0.012 44.028 0.038 ;
     RECT  44.046 0.012 44.244 0.038 ;
     RECT  44.262 0.012 44.424 0.038 ;
     RECT  44.442 0.012 44.604 0.038 ;
     RECT  44.622 0.012 44.82 0.038 ;
     RECT  44.838 0.012 45 0.038 ;
     RECT  45.018 0.012 45.216 0.038 ;
     RECT  45.234 0.012 45.396 0.038 ;
     RECT  45.414 0.012 45.576 0.038 ;
     RECT  45.594 0.012 45.792 0.038 ;
     RECT  45.81 0.012 45.972 0.038 ;
     RECT  45.99 0.012 46.188 0.038 ;
     RECT  46.206 0.012 46.368 0.038 ;
     RECT  46.386 0.012 46.548 0.038 ;
     RECT  46.566 0.012 46.764 0.038 ;
     RECT  46.782 0.012 46.944 0.038 ;
     RECT  46.962 0.012 47.124 0.038 ;
     RECT  47.142 0.012 47.34 0.038 ;
     RECT  47.358 0.012 47.52 0.038 ;
     RECT  47.538 0.012 47.736 0.038 ;
     RECT  47.754 0.012 47.916 0.038 ;
     RECT  47.934 0.012 48.096 0.038 ;
     RECT  48.114 0.012 48.312 0.038 ;
     RECT  48.33 0.012 48.492 0.038 ;
     RECT  48.51 0.012 48.708 0.038 ;
     RECT  48.726 0.012 48.888 0.038 ;
     RECT  48.906 0.012 49.068 0.038 ;
     RECT  49.086 0.012 49.284 0.038 ;
     RECT  49.302 0.012 49.464 0.038 ;
     RECT  49.482 0.012 49.68 0.038 ;
     RECT  49.698 0.012 49.86 0.038 ;
     RECT  49.878 0.012 50.04 0.038 ;
     RECT  50.058 0.012 50.256 0.038 ;
     RECT  0.576 0.038 50.274 18.023 ;
     RECT  0.576 18.023 49.878 19.571 ;
     RECT  0.576 19.571 49.554 19.877 ;
     RECT  1.152 19.877 49.554 20.885 ;
     RECT  1.728 20.885 49.554 21.425 ;
     RECT  1.8 21.425 49.554 21.695 ;
     RECT  1.836 21.695 49.554 22.109 ;
     RECT  1.836 22.109 49.482 40.981 ;
     RECT  1.836 40.981 49.518 41.791 ;
     RECT  1.836 41.791 49.59 43.025 ;
     RECT  1.944 43.025 49.59 45.329 ;
     RECT  2.016 45.329 49.59 45.841 ;
     RECT  2.016 45.841 49.77 47.281 ;
     RECT  50.544 47.281 50.562 47.389 ;
     RECT  1.368 47.281 49.77 47.659 ;
     RECT  50.544 47.389 50.778 47.659 ;
     RECT  1.368 47.659 50.778 48.001 ;
     RECT  1.368 48.001 51.174 48.091 ;
     RECT  0.972 48.091 51.174 48.775 ;
     RECT  0.792 48.775 51.174 49.549 ;
     RECT  0.576 49.549 51.174 51.802 ;
     RECT  0.594 51.802 0.792 51.821 ;
     RECT  0.81 51.802 0.972 51.821 ;
     RECT  0.99 51.802 1.188 51.821 ;
     RECT  1.206 51.802 1.368 51.821 ;
     RECT  1.386 51.802 1.584 51.821 ;
     RECT  1.602 51.802 1.764 51.821 ;
     RECT  1.782 51.802 1.98 51.821 ;
     RECT  1.998 51.802 2.16 51.821 ;
     RECT  2.178 51.802 2.376 51.821 ;
     RECT  2.394 51.802 2.556 51.821 ;
     RECT  2.574 51.802 2.736 51.821 ;
     RECT  2.754 51.802 2.952 51.821 ;
     RECT  2.97 51.802 3.132 51.821 ;
     RECT  3.15 51.802 3.348 51.821 ;
     RECT  3.366 51.802 3.528 51.821 ;
     RECT  3.546 51.802 3.744 51.821 ;
     RECT  3.762 51.802 3.924 51.821 ;
     RECT  3.942 51.802 4.14 51.821 ;
     RECT  4.158 51.802 4.32 51.821 ;
     RECT  4.338 51.802 4.536 51.821 ;
     RECT  4.554 51.802 4.716 51.821 ;
     RECT  4.734 51.802 4.932 51.821 ;
     RECT  4.95 51.802 5.112 51.821 ;
     RECT  5.13 51.802 5.328 51.821 ;
     RECT  5.346 51.802 5.508 51.821 ;
     RECT  5.526 51.802 5.724 51.821 ;
     RECT  5.742 51.802 5.904 51.821 ;
     RECT  5.922 51.802 6.12 51.821 ;
     RECT  6.138 51.802 6.3 51.821 ;
     RECT  6.318 51.802 6.516 51.821 ;
     RECT  6.534 51.802 6.696 51.821 ;
     RECT  6.714 51.802 6.912 51.821 ;
     RECT  6.93 51.802 7.092 51.821 ;
     RECT  7.11 51.802 7.308 51.821 ;
     RECT  7.326 51.802 7.488 51.821 ;
     RECT  7.506 51.802 7.704 51.821 ;
     RECT  7.722 51.802 7.884 51.821 ;
     RECT  7.902 51.802 8.1 51.821 ;
     RECT  8.118 51.802 8.28 51.821 ;
     RECT  8.298 51.802 8.496 51.821 ;
     RECT  8.514 51.802 8.676 51.821 ;
     RECT  8.694 51.802 8.892 51.821 ;
     RECT  8.91 51.802 9.072 51.821 ;
     RECT  9.09 51.802 9.288 51.821 ;
     RECT  9.306 51.802 9.468 51.821 ;
     RECT  9.486 51.802 9.684 51.821 ;
     RECT  9.702 51.802 9.864 51.821 ;
     RECT  9.882 51.802 10.044 51.821 ;
     RECT  10.062 51.802 10.26 51.821 ;
     RECT  10.278 51.802 10.44 51.821 ;
     RECT  10.458 51.802 10.656 51.821 ;
     RECT  10.674 51.802 10.836 51.821 ;
     RECT  10.854 51.802 11.052 51.821 ;
     RECT  11.07 51.802 11.232 51.821 ;
     RECT  11.25 51.802 11.448 51.821 ;
     RECT  11.466 51.802 11.628 51.821 ;
     RECT  11.646 51.802 11.844 51.821 ;
     RECT  11.862 51.802 12.024 51.821 ;
     RECT  12.042 51.802 12.24 51.821 ;
     RECT  12.258 51.802 12.42 51.821 ;
     RECT  12.438 51.802 12.636 51.821 ;
     RECT  12.654 51.802 12.816 51.821 ;
     RECT  12.834 51.802 13.032 51.821 ;
     RECT  13.05 51.802 13.212 51.821 ;
     RECT  13.23 51.802 13.428 51.821 ;
     RECT  13.446 51.802 13.608 51.821 ;
     RECT  13.626 51.802 13.824 51.821 ;
     RECT  13.842 51.802 14.004 51.821 ;
     RECT  14.022 51.802 14.22 51.821 ;
     RECT  14.238 51.802 14.4 51.821 ;
     RECT  14.418 51.802 14.616 51.821 ;
     RECT  14.634 51.802 14.796 51.821 ;
     RECT  14.814 51.802 15.012 51.821 ;
     RECT  15.03 51.802 15.192 51.821 ;
     RECT  15.21 51.802 15.408 51.821 ;
     RECT  15.426 51.802 15.588 51.821 ;
     RECT  15.606 51.802 15.804 51.821 ;
     RECT  15.822 51.802 15.984 51.821 ;
     RECT  16.002 51.802 16.2 51.821 ;
     RECT  16.218 51.802 16.38 51.821 ;
     RECT  16.398 51.802 16.596 51.821 ;
     RECT  16.614 51.802 16.776 51.821 ;
     RECT  16.794 51.802 16.992 51.821 ;
     RECT  17.01 51.802 17.172 51.821 ;
     RECT  17.19 51.802 17.352 51.821 ;
     RECT  17.37 51.802 17.568 51.821 ;
     RECT  17.586 51.802 17.748 51.821 ;
     RECT  17.766 51.802 17.964 51.821 ;
     RECT  17.982 51.802 18.144 51.821 ;
     RECT  18.162 51.802 18.36 51.821 ;
     RECT  18.378 51.802 18.54 51.821 ;
     RECT  18.558 51.802 18.756 51.821 ;
     RECT  18.774 51.802 18.936 51.821 ;
     RECT  18.954 51.802 19.152 51.821 ;
     RECT  19.17 51.802 19.332 51.821 ;
     RECT  19.35 51.802 19.548 51.821 ;
     RECT  19.566 51.802 19.728 51.821 ;
     RECT  19.746 51.802 19.944 51.821 ;
     RECT  19.962 51.802 20.124 51.821 ;
     RECT  20.142 51.802 20.34 51.821 ;
     RECT  20.358 51.802 20.52 51.821 ;
     RECT  20.538 51.802 20.736 51.821 ;
     RECT  20.754 51.802 20.916 51.821 ;
     RECT  20.934 51.802 21.132 51.821 ;
     RECT  21.15 51.802 21.312 51.821 ;
     RECT  21.33 51.802 21.528 51.821 ;
     RECT  21.546 51.802 21.708 51.821 ;
     RECT  21.726 51.802 21.924 51.821 ;
     RECT  21.942 51.802 22.104 51.821 ;
     RECT  22.122 51.802 22.32 51.821 ;
     RECT  22.338 51.802 22.5 51.821 ;
     RECT  22.518 51.802 22.716 51.821 ;
     RECT  22.734 51.802 22.896 51.821 ;
     RECT  22.914 51.802 23.112 51.821 ;
     RECT  23.13 51.802 23.292 51.821 ;
     RECT  23.31 51.802 23.508 51.821 ;
     RECT  23.526 51.802 23.688 51.821 ;
     RECT  23.706 51.802 23.904 51.821 ;
     RECT  23.922 51.802 24.084 51.821 ;
     RECT  24.102 51.802 24.3 51.821 ;
     RECT  24.318 51.802 24.48 51.821 ;
     RECT  24.498 51.802 24.66 51.821 ;
     RECT  24.678 51.802 24.876 51.821 ;
     RECT  24.894 51.802 25.056 51.821 ;
     RECT  25.074 51.802 25.272 51.821 ;
     RECT  25.29 51.802 25.452 51.821 ;
     RECT  25.47 51.802 25.668 51.821 ;
     RECT  25.686 51.802 25.848 51.821 ;
     RECT  25.866 51.802 26.064 51.821 ;
     RECT  26.082 51.802 26.244 51.821 ;
     RECT  26.262 51.802 26.46 51.821 ;
     RECT  26.478 51.802 26.64 51.821 ;
     RECT  26.658 51.802 26.856 51.821 ;
     RECT  26.874 51.802 27.036 51.821 ;
     RECT  27.054 51.802 27.252 51.821 ;
     RECT  27.27 51.802 27.432 51.821 ;
     RECT  27.45 51.802 27.648 51.821 ;
     RECT  27.666 51.802 27.828 51.821 ;
     RECT  27.846 51.802 28.044 51.821 ;
     RECT  28.062 51.802 28.224 51.821 ;
     RECT  28.242 51.802 28.44 51.821 ;
     RECT  28.458 51.802 28.62 51.821 ;
     RECT  28.638 51.802 28.836 51.821 ;
     RECT  28.854 51.802 29.016 51.821 ;
     RECT  29.034 51.802 29.232 51.821 ;
     RECT  29.25 51.802 29.412 51.821 ;
     RECT  29.43 51.802 29.628 51.821 ;
     RECT  29.646 51.802 29.808 51.821 ;
     RECT  29.826 51.802 30.024 51.821 ;
     RECT  30.042 51.802 30.204 51.821 ;
     RECT  30.222 51.802 30.42 51.821 ;
     RECT  30.438 51.802 30.6 51.821 ;
     RECT  30.618 51.802 30.816 51.821 ;
     RECT  30.834 51.802 30.996 51.821 ;
     RECT  31.014 51.802 31.212 51.821 ;
     RECT  31.23 51.802 31.392 51.821 ;
     RECT  31.41 51.802 31.572 51.821 ;
     RECT  31.59 51.802 31.788 51.821 ;
     RECT  31.806 51.802 31.968 51.821 ;
     RECT  31.986 51.802 32.184 51.821 ;
     RECT  32.202 51.802 32.364 51.821 ;
     RECT  32.382 51.802 32.58 51.821 ;
     RECT  32.598 51.802 32.76 51.821 ;
     RECT  32.778 51.802 32.976 51.821 ;
     RECT  32.994 51.802 33.156 51.821 ;
     RECT  33.174 51.802 33.372 51.821 ;
     RECT  33.39 51.802 33.552 51.821 ;
     RECT  33.57 51.802 33.768 51.821 ;
     RECT  33.786 51.802 33.948 51.821 ;
     RECT  33.966 51.802 34.164 51.821 ;
     RECT  34.182 51.802 34.344 51.821 ;
     RECT  34.362 51.802 34.56 51.821 ;
     RECT  34.578 51.802 34.74 51.821 ;
     RECT  34.758 51.802 34.956 51.821 ;
     RECT  34.974 51.802 35.136 51.821 ;
     RECT  35.154 51.802 35.352 51.821 ;
     RECT  35.37 51.802 35.532 51.821 ;
     RECT  35.55 51.802 35.748 51.821 ;
     RECT  35.766 51.802 35.928 51.821 ;
     RECT  35.946 51.802 36.144 51.821 ;
     RECT  36.162 51.802 36.324 51.821 ;
     RECT  36.342 51.802 36.54 51.821 ;
     RECT  36.558 51.802 36.72 51.821 ;
     RECT  36.738 51.802 36.936 51.821 ;
     RECT  36.954 51.802 37.116 51.821 ;
     RECT  37.134 51.802 37.332 51.821 ;
     RECT  37.35 51.802 37.512 51.821 ;
     RECT  37.53 51.802 37.728 51.821 ;
     RECT  37.746 51.802 37.908 51.821 ;
     RECT  37.926 51.802 38.124 51.821 ;
     RECT  38.142 51.802 38.304 51.821 ;
     RECT  38.322 51.802 38.52 51.821 ;
     RECT  38.538 51.802 38.7 51.821 ;
     RECT  38.718 51.802 38.88 51.821 ;
     RECT  38.898 51.802 39.096 51.821 ;
     RECT  39.114 51.802 39.276 51.821 ;
     RECT  39.294 51.802 39.492 51.821 ;
     RECT  39.51 51.802 39.672 51.821 ;
     RECT  39.69 51.802 39.888 51.821 ;
     RECT  39.906 51.802 40.068 51.821 ;
     RECT  40.086 51.802 40.284 51.821 ;
     RECT  40.302 51.802 40.464 51.821 ;
     RECT  40.482 51.802 40.68 51.821 ;
     RECT  40.698 51.802 40.86 51.821 ;
     RECT  40.878 51.802 41.076 51.821 ;
     RECT  41.094 51.802 41.256 51.821 ;
     RECT  41.274 51.802 41.472 51.821 ;
     RECT  41.49 51.802 41.652 51.821 ;
     RECT  41.67 51.802 41.868 51.821 ;
     RECT  41.886 51.802 42.048 51.821 ;
     RECT  42.066 51.802 42.264 51.821 ;
     RECT  42.282 51.802 42.444 51.821 ;
     RECT  42.462 51.802 42.66 51.821 ;
     RECT  42.678 51.802 42.84 51.821 ;
     RECT  42.858 51.802 43.056 51.821 ;
     RECT  43.074 51.802 43.236 51.821 ;
     RECT  43.254 51.802 43.452 51.821 ;
     RECT  43.47 51.802 43.632 51.821 ;
     RECT  43.65 51.802 43.848 51.821 ;
     RECT  43.866 51.802 44.028 51.821 ;
     RECT  44.046 51.802 44.244 51.821 ;
     RECT  44.262 51.802 44.424 51.821 ;
     RECT  44.442 51.802 44.64 51.821 ;
     RECT  44.658 51.802 44.82 51.821 ;
     RECT  44.838 51.802 45.036 51.821 ;
     RECT  45.054 51.802 45.216 51.821 ;
     RECT  45.234 51.802 45.432 51.821 ;
     RECT  45.45 51.802 45.612 51.821 ;
     RECT  45.63 51.802 45.828 51.821 ;
     RECT  45.846 51.802 46.008 51.821 ;
     RECT  46.026 51.802 46.188 51.821 ;
     RECT  46.206 51.802 46.404 51.821 ;
     RECT  46.422 51.802 46.584 51.821 ;
     RECT  46.602 51.802 46.8 51.821 ;
     RECT  46.818 51.802 46.98 51.821 ;
     RECT  46.998 51.802 47.196 51.821 ;
     RECT  47.214 51.802 47.376 51.821 ;
     RECT  47.394 51.802 47.592 51.821 ;
     RECT  47.61 51.802 47.772 51.821 ;
     RECT  47.79 51.802 47.988 51.821 ;
     RECT  48.006 51.802 48.168 51.821 ;
     RECT  48.186 51.802 48.384 51.821 ;
     RECT  48.402 51.802 48.564 51.821 ;
     RECT  48.582 51.802 48.78 51.821 ;
     RECT  48.798 51.802 48.96 51.821 ;
     RECT  48.978 51.802 49.176 51.821 ;
     RECT  49.194 51.802 49.356 51.821 ;
     RECT  49.374 51.802 49.572 51.821 ;
     RECT  49.59 51.802 49.752 51.821 ;
     RECT  49.77 51.802 49.968 51.821 ;
     RECT  49.986 51.802 50.148 51.821 ;
     RECT  50.166 51.802 50.364 51.821 ;
     RECT  50.382 51.802 50.544 51.821 ;
     RECT  50.562 51.802 50.76 51.821 ;
     RECT  50.778 51.802 50.94 51.821 ;
     RECT  50.958 51.802 51.156 51.821 ;
    LAYER M4 ;
     RECT  0.661 18.24 0.853 18.264 ;
     RECT  0.853 17.664 1.045 18.264 ;
     RECT  0.853 49.296 1.045 49.32 ;
     RECT  0.661 47.904 1.141 47.928 ;
     RECT  1.045 49.008 1.141 49.32 ;
     RECT  1.045 17.664 1.237 18.456 ;
     RECT  1.141 47.904 1.237 49.32 ;
     RECT  1.237 47.904 1.477 50.184 ;
     RECT  1.429 20.592 1.621 20.616 ;
     RECT  1.477 47.904 1.669 50.28 ;
     RECT  1.621 20.544 1.781 20.616 ;
     RECT  1.669 47.856 2.077 50.28 ;
     RECT  1.825 2.016 2.221 2.04 ;
     RECT  2.221 2.016 2.293 2.856 ;
     RECT  1.237 17.664 2.329 19.416 ;
     RECT  1.781 20.544 2.329 21.144 ;
     RECT  2.293 46.08 2.329 46.104 ;
     RECT  2.245 42.768 2.365 42.792 ;
     RECT  2.293 1.968 2.408 2.856 ;
     RECT  2.329 17.664 2.408 21.144 ;
     RECT  2.293 25.728 2.408 25.752 ;
     RECT  2.365 37.44 2.408 37.464 ;
     RECT  2.365 42.768 2.408 43.32 ;
     RECT  2.329 45.984 2.408 46.104 ;
     RECT  2.077 47.28 2.408 50.28 ;
     RECT  2.408 1.968 2.627 50.28 ;
     RECT  2.627 2.304 2.693 50.28 ;
     RECT  2.693 2.304 2.704 50.184 ;
     RECT  2.704 46.08 2.801 48.984 ;
     RECT  2.704 20.064 2.819 20.088 ;
     RECT  2.704 22.8 2.819 25.752 ;
     RECT  2.704 40.992 2.819 41.64 ;
     RECT  2.293 51.648 2.819 51.672 ;
     RECT  2.819 22.8 2.867 25.656 ;
     RECT  2.704 27.12 2.867 27.144 ;
     RECT  2.704 42.768 2.981 44.424 ;
     RECT  2.867 23.328 3.107 24.264 ;
     RECT  2.801 46.224 3.197 48.984 ;
     RECT  2.704 50.16 3.197 50.184 ;
     RECT  2.704 39.888 3.251 39.912 ;
     RECT  3.197 46.224 3.305 48.456 ;
     RECT  2.704 2.304 3.485 2.328 ;
     RECT  2.704 37.44 3.521 37.464 ;
     RECT  2.981 42.768 3.521 44.28 ;
     RECT  3.521 43.824 3.593 44.28 ;
     RECT  3.521 42.768 3.635 42.792 ;
     RECT  3.305 46.224 3.701 47.88 ;
     RECT  3.107 23.376 3.827 24.264 ;
     RECT  3.593 44.256 3.917 44.28 ;
     RECT  3.701 47.856 3.953 47.88 ;
     RECT  3.701 46.224 3.985 46.776 ;
     RECT  3.941 1.152 4.025 1.176 ;
     RECT  3.827 24.24 4.097 24.264 ;
     RECT  4.157 0.096 4.24 0.12 ;
     RECT  2.819 41.616 4.268 41.64 ;
     RECT  4.268 40.992 4.309 41.64 ;
     RECT  4.309 40.992 4.355 42.168 ;
     RECT  4.24 0.048 4.385 0.12 ;
     RECT  4.021 51.696 4.385 51.72 ;
     RECT  4.165 5.088 4.403 5.112 ;
     RECT  4.385 0.096 4.417 0.12 ;
     RECT  4.213 34.224 4.565 34.248 ;
     RECT  4.355 41.616 4.643 42.168 ;
     RECT  4.417 0.096 4.673 0.6 ;
     RECT  3.949 31.68 4.837 31.704 ;
     RECT  4.643 42.144 4.853 42.168 ;
     RECT  3.985 45.936 4.885 46.776 ;
     RECT  4.885 45.936 4.979 47.352 ;
     RECT  4.979 45.936 4.993 46.776 ;
     RECT  5.029 49.104 5.065 49.128 ;
     RECT  4.993 45.552 5.141 46.776 ;
     RECT  5.065 49.008 5.141 49.128 ;
     RECT  2.704 21.648 5.281 21.672 ;
     RECT  4.837 31.68 5.285 31.896 ;
     RECT  5.281 21.312 5.321 21.672 ;
     RECT  5.101 47.856 5.381 47.88 ;
     RECT  5.141 49.008 5.381 49.08 ;
     RECT  4.673 0.096 5.573 0.552 ;
     RECT  4.373 50.112 5.677 50.136 ;
     RECT  5.381 47.856 5.717 49.08 ;
     RECT  5.141 45.552 5.747 46.248 ;
     RECT  5.677 50.112 5.843 50.76 ;
     RECT  2.867 25.632 5.893 25.656 ;
     RECT  5.717 47.856 6.005 49.032 ;
     RECT  6.005 47.856 6.073 48.504 ;
     RECT  5.893 25.632 6.181 26.376 ;
     RECT  6.073 47.328 6.181 48.504 ;
     RECT  6.181 47.28 6.185 48.504 ;
     RECT  6.185 47.28 6.221 47.88 ;
     RECT  5.843 50.112 6.265 50.136 ;
     RECT  5.321 21.312 6.289 21.336 ;
     RECT  5.641 23.28 6.289 23.304 ;
     RECT  5.747 46.224 6.332 46.248 ;
     RECT  6.221 47.28 6.332 47.304 ;
     RECT  6.332 46.224 6.419 47.304 ;
     RECT  6.181 25.152 6.505 26.376 ;
     RECT  6.289 21.312 6.515 21.672 ;
     RECT  6.289 22.752 6.613 23.304 ;
     RECT  6.505 25.152 6.613 27.336 ;
     RECT  6.419 46.224 7.153 46.248 ;
     RECT  5.573 0.528 7.261 0.552 ;
     RECT  6.613 22.752 7.285 23.4 ;
     RECT  6.613 24.72 7.285 27.336 ;
     RECT  6.419 47.28 7.381 47.304 ;
     RECT  7.261 0.528 7.405 1.128 ;
     RECT  7.285 22.752 7.429 27.336 ;
     RECT  6.829 19.392 7.613 19.416 ;
     RECT  7.405 0.48 7.621 1.128 ;
     RECT  6.515 21.312 7.621 21.336 ;
     RECT  7.429 22.752 7.621 27.72 ;
     RECT  7.621 21.312 7.693 27.72 ;
     RECT  7.573 50.688 7.765 50.712 ;
     RECT  6.757 4.512 7.808 4.536 ;
     RECT  7.621 8.496 7.808 8.52 ;
     RECT  7.613 18.912 7.808 19.416 ;
     RECT  7.693 20.976 7.808 27.72 ;
     RECT  6.805 29.04 7.808 29.064 ;
     RECT  7.429 30.672 7.808 30.696 ;
     RECT  5.285 31.68 7.808 31.704 ;
     RECT  7.189 43.872 7.808 43.896 ;
     RECT  7.153 46.176 7.808 46.248 ;
     RECT  7.381 47.28 7.808 48.264 ;
     RECT  7.765 49.824 7.808 50.712 ;
     RECT  7.621 0.144 7.877 1.128 ;
     RECT  7.808 2.148 7.912 50.712 ;
     RECT  7.912 2.418 8.104 50.712 ;
     RECT  8.104 22.032 8.243 22.92 ;
     RECT  8.104 8.496 8.291 8.52 ;
     RECT  8.104 47.472 8.291 47.928 ;
     RECT  7.957 51.696 8.291 51.72 ;
     RECT  8.104 49.536 8.417 50.712 ;
     RECT  8.104 36.432 8.561 36.456 ;
     RECT  8.104 29.04 8.572 30.696 ;
     RECT  8.104 2.832 8.675 2.856 ;
     RECT  8.104 40.992 8.741 41.016 ;
     RECT  7.877 0.144 8.773 0.552 ;
     RECT  8.417 49.536 8.819 50.184 ;
     RECT  8.773 0.096 8.867 0.552 ;
     RECT  8.572 29.04 9.029 29.064 ;
     RECT  8.867 0.096 9.059 0.12 ;
     RECT  8.243 22.8 9.065 22.92 ;
     RECT  9.097 24.72 9.133 24.744 ;
     RECT  8.819 49.536 9.137 50.136 ;
     RECT  9.133 23.952 9.251 24.744 ;
     RECT  8.291 47.472 9.253 47.496 ;
     RECT  9.253 47.472 9.349 48.36 ;
     RECT  9.137 50.112 9.353 50.136 ;
     RECT  9.251 24.432 9.443 24.744 ;
     RECT  8.104 27.696 9.493 27.72 ;
     RECT  9.457 15.408 9.635 15.432 ;
     RECT  9.349 47.472 9.701 48.456 ;
     RECT  9.541 29.616 9.749 29.64 ;
     RECT  9.701 47.472 9.785 49.032 ;
     RECT  9.709 1.104 9.827 1.128 ;
     RECT  9.493 27.696 9.893 28.536 ;
     RECT  8.104 20.976 10.069 21 ;
     RECT  9.601 22.176 10.069 22.2 ;
     RECT  10.069 20.976 10.115 22.2 ;
     RECT  8.572 30.672 10.165 30.696 ;
     RECT  9.997 1.632 10.181 1.704 ;
     RECT  9.853 23.376 10.211 23.4 ;
     RECT  10.165 30.672 10.213 31.32 ;
     RECT  9.893 27.696 10.361 27.912 ;
     RECT  9.781 18.816 10.403 18.84 ;
     RECT  10.213 30.624 10.433 31.32 ;
     RECT  10.181 1.68 10.595 1.704 ;
     RECT  9.785 47.472 10.613 48.456 ;
     RECT  10.115 21.408 10.645 22.2 ;
     RECT  9.443 24.72 10.717 24.744 ;
     RECT  10.105 4.512 10.787 4.536 ;
     RECT  10.501 50.736 10.787 50.76 ;
     RECT  10.717 23.808 10.793 24.744 ;
     RECT  10.069 26.208 10.825 26.232 ;
     RECT  10.433 30.624 10.837 30.648 ;
     RECT  10.837 30 10.883 30.648 ;
     RECT  10.825 25.632 10.909 26.232 ;
     RECT  10.613 47.472 10.933 47.688 ;
     RECT  10.645 21.408 11.077 22.248 ;
     RECT  10.933 49.536 11.116 49.56 ;
     RECT  11.116 49.536 11.117 49.608 ;
     RECT  11.117 49.584 11.261 49.608 ;
     RECT  11.077 21.408 11.363 22.296 ;
     RECT  10.793 23.808 11.555 24.504 ;
     RECT  11.317 32.448 11.653 32.472 ;
     RECT  11.653 32.448 11.657 33.288 ;
     RECT  8.104 46.224 11.749 46.248 ;
     RECT  10.933 47.328 11.749 47.688 ;
     RECT  10.909 26.208 11.765 26.232 ;
     RECT  11.509 51.696 11.9 51.72 ;
     RECT  11.363 21.408 11.939 22.248 ;
     RECT  11.9 50.736 11.987 51.72 ;
     RECT  10.361 27.744 12.089 27.912 ;
     RECT  12.089 27.888 12.133 27.912 ;
     RECT  11.977 3.936 12.179 3.96 ;
     RECT  11.555 23.808 12.661 23.832 ;
     RECT  12.62 31.536 12.661 31.56 ;
     RECT  11.987 51.696 12.773 51.72 ;
     RECT  12.661 31.536 12.908 32.232 ;
     RECT  11.657 33.264 12.908 33.288 ;
     RECT  11.581 18.816 13.052 18.84 ;
     RECT  13.093 51.648 13.129 51.672 ;
     RECT  12.509 4.56 13.208 4.584 ;
     RECT  12.589 6.816 13.208 6.84 ;
     RECT  13.052 18.816 13.208 18.936 ;
     RECT  11.939 21.408 13.208 21.432 ;
     RECT  12.661 23.808 13.208 24.504 ;
     RECT  12.661 26.064 13.208 26.088 ;
     RECT  12.133 27.888 13.208 28.488 ;
     RECT  10.883 30 13.208 30.024 ;
     RECT  12.908 31.536 13.208 33.288 ;
     RECT  13.093 35.424 13.208 35.448 ;
     RECT  13.093 36.528 13.208 36.552 ;
     RECT  13.052 39.36 13.208 39.384 ;
     RECT  11.749 46.224 13.208 47.688 ;
     RECT  12.709 49.536 13.208 49.56 ;
     RECT  13.208 2.148 13.312 49.692 ;
     RECT  13.129 50.736 13.331 51.672 ;
     RECT  13.312 2.418 13.504 49.422 ;
     RECT  13.093 0.144 13.619 0.312 ;
     RECT  13.504 18.816 13.619 18.984 ;
     RECT  13.504 36.528 13.619 36.552 ;
     RECT  13.619 0.144 13.667 0.168 ;
     RECT  13.504 32.208 13.673 33.288 ;
     RECT  13.331 51.552 13.673 51.672 ;
     RECT  13.504 27.312 13.715 28.104 ;
     RECT  13.504 22.8 13.745 23.976 ;
     RECT  13.673 33.264 13.745 33.288 ;
     RECT  13.669 1.152 13.853 1.176 ;
     RECT  13.504 5.088 13.925 5.736 ;
     RECT  13.715 27.312 14.033 27.336 ;
     RECT  13.909 51.696 14.141 51.72 ;
     RECT  13.925 5.088 14.291 5.112 ;
     RECT  13.504 46.224 14.465 48.456 ;
     RECT  14.417 0.096 14.501 0.12 ;
     RECT  13.619 18.816 14.681 18.84 ;
     RECT  13.504 25.68 14.753 26.088 ;
     RECT  13.745 23.136 14.819 23.976 ;
     RECT  14.465 46.224 14.869 47.88 ;
     RECT  14.821 13.056 14.905 13.08 ;
     RECT  14.869 45.552 15.001 47.88 ;
     RECT  15.001 45.024 15.107 47.88 ;
     RECT  15.107 45.552 15.185 47.88 ;
     RECT  14.753 26.064 15.212 26.088 ;
     RECT  13.504 21.648 15.217 21.672 ;
     RECT  15.212 26.064 15.253 26.664 ;
     RECT  15.253 26.064 15.299 27.336 ;
     RECT  14.485 49.008 15.347 49.032 ;
     RECT  15.217 21.648 15.469 22.152 ;
     RECT  15.299 27.312 15.548 27.336 ;
     RECT  15.548 27.312 15.635 28.296 ;
     RECT  15.185 46.224 15.683 47.88 ;
     RECT  15.469 21.648 15.781 22.2 ;
     RECT  15.493 51.696 15.797 51.72 ;
     RECT  15.683 46.752 15.827 47.88 ;
     RECT  15.937 2.832 15.965 2.856 ;
     RECT  14.819 23.376 15.973 23.976 ;
     RECT  15.965 2.832 16.049 3.432 ;
     RECT  13.504 29.616 16.049 30.792 ;
     RECT  15.635 27.312 16.121 27.96 ;
     RECT  15.781 21.264 16.153 22.296 ;
     RECT  15.973 23.376 16.153 24.12 ;
     RECT  16.069 50.112 16.157 50.136 ;
     RECT  16.153 21.264 16.225 24.12 ;
     RECT  15.827 47.328 16.307 47.88 ;
     RECT  13.673 32.208 16.369 32.232 ;
     RECT  16.225 20.592 16.403 24.12 ;
     RECT  16.403 23.328 16.553 24.12 ;
     RECT  16.049 2.832 16.595 2.856 ;
     RECT  16.369 32.208 16.657 32.808 ;
     RECT  15.299 26.064 16.729 26.088 ;
     RECT  16.121 27.312 16.729 27.912 ;
     RECT  16.049 29.616 16.733 29.64 ;
     RECT  16.657 31.872 16.837 32.808 ;
     RECT  16.729 26.064 16.841 27.912 ;
     RECT  16.307 47.808 16.841 47.88 ;
     RECT  16.841 27.312 16.913 27.912 ;
     RECT  16.049 30.768 16.945 30.792 ;
     RECT  16.837 31.872 16.981 33 ;
     RECT  16.403 20.592 17.027 22.2 ;
     RECT  16.981 31.872 17.027 33.048 ;
     RECT  16.885 51.696 17.056 51.72 ;
     RECT  17.056 51.648 17.057 51.72 ;
     RECT  16.945 30.768 17.077 30.84 ;
     RECT  16.841 47.856 17.077 47.88 ;
     RECT  17.077 30.672 17.123 30.84 ;
     RECT  13.504 35.424 17.123 35.448 ;
     RECT  17.132 0.528 17.219 0.552 ;
     RECT  17.077 47.856 17.219 49.08 ;
     RECT  17.057 51.648 17.219 51.672 ;
     RECT  17.027 22.176 17.237 22.2 ;
     RECT  17.197 42.192 17.315 42.216 ;
     RECT  17.219 47.856 17.381 48.456 ;
     RECT  16.913 27.888 17.453 27.912 ;
     RECT  17.027 32.784 17.461 33.048 ;
     RECT  17.077 34.176 17.461 34.2 ;
     RECT  16.553 23.952 17.701 24.12 ;
     RECT  17.593 22.752 17.845 22.776 ;
     RECT  17.701 23.952 17.845 24.504 ;
     RECT  16.841 26.064 18.097 26.232 ;
     RECT  17.953 28.128 18.229 28.824 ;
     RECT  17.461 32.784 18.229 34.2 ;
     RECT  17.804 46.176 18.421 46.2 ;
     RECT  17.381 47.856 18.421 47.88 ;
     RECT  18.421 0.096 18.469 0.12 ;
     RECT  15.781 18.816 18.608 18.84 ;
     RECT  17.027 20.592 18.608 20.712 ;
     RECT  17.845 22.752 18.608 24.504 ;
     RECT  18.097 25.824 18.608 26.232 ;
     RECT  18.229 28.128 18.608 29.496 ;
     RECT  17.123 30.672 18.608 30.696 ;
     RECT  18.229 32.784 18.608 34.776 ;
     RECT  18.421 46.176 18.608 47.928 ;
     RECT  17.653 49.536 18.608 49.56 ;
     RECT  18.277 50.736 18.707 50.76 ;
     RECT  18.608 2.148 18.712 49.692 ;
     RECT  18.469 0.096 18.755 0.216 ;
     RECT  18.712 2.418 18.853 49.692 ;
     RECT  18.853 2.418 18.904 50.136 ;
     RECT  18.904 30.672 18.965 30.696 ;
     RECT  18.904 28.464 19.037 29.352 ;
     RECT  18.904 3.936 19.043 3.96 ;
     RECT  19.045 51.696 19.145 51.72 ;
     RECT  18.904 50.112 19.253 50.136 ;
     RECT  18.904 18.816 19.331 18.888 ;
     RECT  18.904 34.176 19.379 34.2 ;
     RECT  18.904 36.096 19.379 37.08 ;
     RECT  18.904 22.128 19.397 22.776 ;
     RECT  19.397 22.128 19.523 22.248 ;
     RECT  19.037 29.04 19.541 29.352 ;
     RECT  18.904 20.688 19.901 20.712 ;
     RECT  19.541 29.04 19.901 29.064 ;
     RECT  18.755 0.096 19.907 0.12 ;
     RECT  19.523 22.128 19.907 22.152 ;
     RECT  18.904 25.824 19.907 26.28 ;
     RECT  18.904 46.176 19.937 46.728 ;
     RECT  18.904 23.952 19.973 24.504 ;
     RECT  19.937 46.176 20.077 46.2 ;
     RECT  20.077 46.128 20.078 46.2 ;
     RECT  19.379 36.096 20.081 36.12 ;
     RECT  19.753 2.256 20.099 2.28 ;
     RECT  18.904 47.808 20.333 47.88 ;
     RECT  20.396 26.64 20.483 26.664 ;
     RECT  20.078 46.128 20.531 46.152 ;
     RECT  20.437 27.936 20.621 27.96 ;
     RECT  19.973 24.336 20.693 24.504 ;
     RECT  20.629 51.696 20.821 51.72 ;
     RECT  20.821 51.6 20.981 51.72 ;
     RECT  21.121 50.16 21.251 50.184 ;
     RECT  21.205 0.096 21.304 0.12 ;
     RECT  21.304 0.048 21.449 0.12 ;
     RECT  21.013 34.176 21.449 34.2 ;
     RECT  19.331 18.816 21.491 18.84 ;
     RECT  20.509 4.512 21.683 4.536 ;
     RECT  21.397 22.704 21.695 22.728 ;
     RECT  21.695 22.704 21.845 23.352 ;
     RECT  21.449 0.096 21.881 0.12 ;
     RECT  20.333 47.856 21.973 47.88 ;
     RECT  21.845 23.328 21.985 23.352 ;
     RECT  20.693 24.336 21.985 24.36 ;
     RECT  21.049 25.68 22.028 25.704 ;
     RECT  21.517 27.36 22.028 27.384 ;
     RECT  21.985 23.328 22.069 24.36 ;
     RECT  18.904 32.784 22.097 33.048 ;
     RECT  22.028 25.68 22.115 27.384 ;
     RECT  21.085 21.216 22.129 21.24 ;
     RECT  22.069 24.336 22.165 24.36 ;
     RECT  21.973 47.856 22.169 48.456 ;
     RECT  22.165 24.336 22.205 24.552 ;
     RECT  22.129 10.224 22.259 10.248 ;
     RECT  21.581 50.112 22.349 50.136 ;
     RECT  22.129 21.216 22.457 22.2 ;
     RECT  22.381 18.912 22.465 18.936 ;
     RECT  22.457 21.648 22.493 22.2 ;
     RECT  22.069 23.328 22.529 23.352 ;
     RECT  22.273 29.664 22.643 29.688 ;
     RECT  20.509 30.672 22.741 30.696 ;
     RECT  22.741 30.672 22.813 30.792 ;
     RECT  22.381 3.936 22.835 3.96 ;
     RECT  22.789 49.008 22.925 49.032 ;
     RECT  22.169 47.856 22.981 47.88 ;
     RECT  20.981 51.696 23.173 51.72 ;
     RECT  22.813 30.672 23.281 30.888 ;
     RECT  23.173 51.648 23.285 51.72 ;
     RECT  23.065 23.376 23.677 23.4 ;
     RECT  22.205 24.48 23.677 24.552 ;
     RECT  23.749 2.016 23.987 2.04 ;
     RECT  23.285 51.648 23.989 51.672 ;
     RECT  23.345 18.816 24.008 18.84 ;
     RECT  22.493 21.648 24.008 21.672 ;
     RECT  23.677 23.376 24.008 24.552 ;
     RECT  22.115 25.68 24.008 25.704 ;
     RECT  22.115 27.36 24.008 27.384 ;
     RECT  23.641 29.04 24.008 29.064 ;
     RECT  23.281 30.048 24.008 30.888 ;
     RECT  22.097 32.784 24.008 32.808 ;
     RECT  23.797 34.176 24.008 34.2 ;
     RECT  23.365 45.552 24.008 45.576 ;
     RECT  22.981 47.28 24.008 47.88 ;
     RECT  23.497 49.584 24.008 49.608 ;
     RECT  24.008 2.148 24.112 49.692 ;
     RECT  23.965 0.528 24.179 0.552 ;
     RECT  23.989 50.688 24.185 51.672 ;
     RECT  24.112 2.256 24.304 49.608 ;
     RECT  24.304 40.464 24.467 40.488 ;
     RECT  24.185 51.648 24.467 51.672 ;
     RECT  24.304 2.256 24.563 2.904 ;
     RECT  24.304 22.224 24.581 23.928 ;
     RECT  24.304 47.328 24.611 47.736 ;
     RECT  24.581 22.224 24.755 23.16 ;
     RECT  24.304 49.584 24.803 49.608 ;
     RECT  24.755 23.136 25.121 23.16 ;
     RECT  24.611 47.712 25.157 47.736 ;
     RECT  24.304 27.312 25.229 27.336 ;
     RECT  24.563 2.88 25.337 2.904 ;
     RECT  24.304 42.144 25.373 42.168 ;
     RECT  24.304 32.784 25.379 32.808 ;
     RECT  24.304 34.224 25.417 34.248 ;
     RECT  24.304 30.048 25.523 30.84 ;
     RECT  25.513 32.496 25.525 32.52 ;
     RECT  25.523 30.048 25.589 30.744 ;
     RECT  25.525 31.776 25.667 32.52 ;
     RECT  25.628 3.408 25.715 3.432 ;
     RECT  25.573 28.464 25.729 28.488 ;
     RECT  25.729 23.952 25.906 23.976 ;
     RECT  25.333 51.696 26.057 51.72 ;
     RECT  25.589 30.048 26.125 30.648 ;
     RECT  25.906 23.952 26.147 24.024 ;
     RECT  25.765 50.64 26.149 50.664 ;
     RECT  24.325 0.144 26.293 0.168 ;
     RECT  26.293 0.144 26.381 0.264 ;
     RECT  25.667 31.776 26.485 31.8 ;
     RECT  26.485 31.68 26.525 31.8 ;
     RECT  26.017 5.664 26.531 5.688 ;
     RECT  26.149 50.64 26.684 50.712 ;
     RECT  25.837 26.256 26.701 26.28 ;
     RECT  26.684 50.16 26.771 50.712 ;
     RECT  26.125 20.976 26.813 21 ;
     RECT  26.701 25.68 26.957 26.28 ;
     RECT  25.729 27.888 26.957 28.488 ;
     RECT  26.773 50.736 26.963 50.76 ;
     RECT  26.957 27.888 27.025 27.912 ;
     RECT  27.025 27.312 27.065 27.912 ;
     RECT  27.109 49.536 27.317 49.56 ;
     RECT  26.809 23.376 27.493 23.4 ;
     RECT  27.253 17.088 27.533 17.112 ;
     RECT  27.493 23.376 27.565 23.928 ;
     RECT  27.565 28.992 27.673 29.016 ;
     RECT  26.125 30 27.673 30.648 ;
     RECT  27.541 51.696 27.677 51.72 ;
     RECT  26.957 25.68 27.683 26.088 ;
     RECT  26.525 31.68 27.733 31.704 ;
     RECT  27.349 48.432 27.749 48.456 ;
     RECT  27.565 23.376 27.817 24.504 ;
     RECT  27.637 21.312 27.877 21.336 ;
     RECT  27.877 21.312 27.923 22.2 ;
     RECT  27.884 46.176 27.971 46.2 ;
     RECT  27.817 23.328 28.105 24.504 ;
     RECT  27.683 25.68 28.105 25.704 ;
     RECT  27.923 22.176 28.253 22.2 ;
     RECT  27.733 31.68 28.253 31.896 ;
     RECT  28.105 23.328 28.259 25.704 ;
     RECT  26.381 0.144 28.285 0.168 ;
     RECT  28.117 45.552 28.289 45.576 ;
     RECT  28.253 31.872 28.325 31.896 ;
     RECT  28.285 0.144 28.643 0.552 ;
     RECT  28.501 49.536 28.693 49.56 ;
     RECT  27.065 27.312 28.741 27.336 ;
     RECT  28.693 49.536 28.793 50.136 ;
     RECT  28.741 27.312 29.173 27.912 ;
     RECT  27.673 28.992 29.173 30.648 ;
     RECT  28.933 51.696 29.173 51.72 ;
     RECT  28.933 2.256 29.408 2.28 ;
     RECT  24.304 18.816 29.408 18.84 ;
     RECT  28.213 21.072 29.408 21.096 ;
     RECT  28.259 23.328 29.408 25.128 ;
     RECT  29.173 27.312 29.408 30.648 ;
     RECT  29.125 44.976 29.408 45 ;
     RECT  28.309 47.856 29.408 47.88 ;
     RECT  28.793 49.536 29.408 49.8 ;
     RECT  29.408 2.148 29.512 49.8 ;
     RECT  28.643 0.144 29.603 0.36 ;
     RECT  29.512 2.418 29.704 49.8 ;
     RECT  29.704 28.032 29.765 29.256 ;
     RECT  29.717 1.152 29.801 1.176 ;
     RECT  29.173 51.648 29.873 51.72 ;
     RECT  30.085 50.112 30.197 50.136 ;
     RECT  29.873 51.648 30.257 51.672 ;
     RECT  29.704 20.352 30.275 21.672 ;
     RECT  30.257 50.688 30.341 51.672 ;
     RECT  29.704 15.936 30.371 15.96 ;
     RECT  29.704 48.432 30.557 48.456 ;
     RECT  29.765 28.032 30.563 28.056 ;
     RECT  29.765 29.232 30.737 29.256 ;
     RECT  29.603 0.144 30.757 0.168 ;
     RECT  29.704 30.336 30.809 30.648 ;
     RECT  30.341 50.736 30.869 51.672 ;
     RECT  30.275 21.648 30.881 21.672 ;
     RECT  29.704 23.328 30.881 24.648 ;
     RECT  30.757 2.832 30.899 2.952 ;
     RECT  30.769 4.56 30.899 4.584 ;
     RECT  30.869 50.736 30.953 51.72 ;
     RECT  29.704 18.816 31.033 18.84 ;
     RECT  31.021 46.752 31.139 46.776 ;
     RECT  31.021 22.224 31.187 22.248 ;
     RECT  30.809 30.624 31.237 30.648 ;
     RECT  31.196 31.872 31.237 31.896 ;
     RECT  31.237 30.624 31.283 31.896 ;
     RECT  29.704 34.8 31.283 34.824 ;
     RECT  30.757 0.144 31.292 0.264 ;
     RECT  30.953 50.736 31.331 50.76 ;
     RECT  31.292 0.144 31.379 0.552 ;
     RECT  31.417 48.48 31.436 48.504 ;
     RECT  31.436 48.48 31.523 49.032 ;
     RECT  31.093 28.944 31.561 28.968 ;
     RECT  31.379 0.144 31.601 0.264 ;
     RECT  30.881 23.904 31.66 24.648 ;
     RECT  31.523 48.48 31.715 48.504 ;
     RECT  30.275 20.352 31.741 20.376 ;
     RECT  31.283 30.624 31.841 31.272 ;
     RECT  31.345 26.544 31.909 26.568 ;
     RECT  31.909 26.544 31.955 27.24 ;
     RECT  31.841 30.144 31.958 31.272 ;
     RECT  31.909 4.56 31.997 4.584 ;
     RECT  32.053 50.688 32.141 50.712 ;
     RECT  31.921 2.256 32.147 2.28 ;
     RECT  32.173 46.176 32.291 46.2 ;
     RECT  31.561 28.272 32.483 28.968 ;
     RECT  32.453 6.288 32.537 6.312 ;
     RECT  31.955 27.216 32.573 27.24 ;
     RECT  32.629 27.312 32.716 27.384 ;
     RECT  31.66 23.952 32.717 24.648 ;
     RECT  32.533 15.408 32.723 15.432 ;
     RECT  32.605 49.008 32.723 49.032 ;
     RECT  31.958 30.192 32.825 31.272 ;
     RECT  32.825 30.192 32.861 30.792 ;
     RECT  32.828 45.6 32.915 45.624 ;
     RECT  31.741 20.352 32.965 21.144 ;
     RECT  32.197 22.224 32.965 22.248 ;
     RECT  32.861 30.192 32.969 30.6 ;
     RECT  32.483 28.944 33.005 28.968 ;
     RECT  32.965 20.352 33.041 22.248 ;
     RECT  33.041 21.12 33.049 22.248 ;
     RECT  32.717 23.952 33.073 24.12 ;
     RECT  32.716 27.36 33.107 27.384 ;
     RECT  32.029 25.68 33.181 25.704 ;
     RECT  33.253 49.536 33.617 49.56 ;
     RECT  33.181 25.584 33.653 26.232 ;
     RECT  33.596 7.392 33.683 7.416 ;
     RECT  32.485 51.696 33.796 51.72 ;
     RECT  33.796 51.648 34.013 51.72 ;
     RECT  33.901 45.6 34.412 45.624 ;
     RECT  32.969 30.432 34.441 30.6 ;
     RECT  33.073 23.328 34.477 24.12 ;
     RECT  31.601 0.144 34.621 0.168 ;
     RECT  34.013 51.696 34.733 51.72 ;
     RECT  34.172 6.24 34.808 6.264 ;
     RECT  33.109 18.816 34.808 18.84 ;
     RECT  33.649 19.824 34.808 19.944 ;
     RECT  33.049 21.12 34.808 21.144 ;
     RECT  33.049 22.224 34.808 22.248 ;
     RECT  34.477 23.328 34.808 24.504 ;
     RECT  33.653 25.584 34.808 25.608 ;
     RECT  34.153 27.312 34.808 27.336 ;
     RECT  34.441 30.432 34.808 30.792 ;
     RECT  33.901 34.752 34.808 34.776 ;
     RECT  32.029 42.528 34.808 42.552 ;
     RECT  34.412 45.6 34.808 46.2 ;
     RECT  33.404 48.48 34.808 48.504 ;
     RECT  34.621 0.144 34.835 1.128 ;
     RECT  34.808 2.148 34.981 49.692 ;
     RECT  34.837 50.688 35.029 50.712 ;
     RECT  34.981 1.728 35.104 49.692 ;
     RECT  35.104 42.432 35.201 42.552 ;
     RECT  35.104 30.432 35.219 31.944 ;
     RECT  35.104 45.6 35.245 45.624 ;
     RECT  35.219 31.92 35.461 31.944 ;
     RECT  35.104 49.536 35.525 49.692 ;
     RECT  35.104 23.856 35.597 24.12 ;
     RECT  35.029 50.688 35.605 51.672 ;
     RECT  35.104 18.816 35.651 18.84 ;
     RECT  35.104 1.728 35.777 1.752 ;
     RECT  35.605 50.112 35.891 51.672 ;
     RECT  35.104 26.736 35.932 27.048 ;
     RECT  35.104 32.928 35.939 33.672 ;
     RECT  35.104 2.832 36.035 2.856 ;
     RECT  35.104 28.32 36.133 28.344 ;
     RECT  35.104 17.088 36.137 17.112 ;
     RECT  36.188 21.36 36.229 21.384 ;
     RECT  36.229 20.496 36.275 21.384 ;
     RECT  36.133 27.888 36.325 28.344 ;
     RECT  35.597 24.096 36.332 24.12 ;
     RECT  35.104 25.152 36.332 25.176 ;
     RECT  35.891 50.112 36.353 50.136 ;
     RECT  35.219 30.432 36.373 30.6 ;
     RECT  35.939 33.072 36.385 33.672 ;
     RECT  36.373 30.288 36.419 30.6 ;
     RECT  36.385 33.072 36.425 34.2 ;
     RECT  36.425 33.072 36.433 33.096 ;
     RECT  35.104 37.248 36.467 37.272 ;
     RECT  36.037 51.696 36.467 51.72 ;
     RECT  36.425 34.176 36.469 34.2 ;
     RECT  36.332 24.096 36.533 25.176 ;
     RECT  34.835 0.144 36.565 0.168 ;
     RECT  36.533 24.096 36.565 25.08 ;
     RECT  35.932 26.736 36.569 26.76 ;
     RECT  36.613 26.256 36.7 26.28 ;
     RECT  36.275 20.496 36.713 21.096 ;
     RECT  36.565 23.952 36.803 25.08 ;
     RECT  36.613 45.552 36.821 45.576 ;
     RECT  36.745 49.008 36.851 49.032 ;
     RECT  36.565 0.144 36.929 0.264 ;
     RECT  36.803 24 36.995 25.08 ;
     RECT  36.995 24.096 37.037 25.08 ;
     RECT  36.925 47.904 37.043 47.928 ;
     RECT  37.037 24.48 37.073 25.08 ;
     RECT  35.104 22.8 37.379 22.824 ;
     RECT  37.349 46.704 37.433 46.728 ;
     RECT  36.713 21.072 37.475 21.096 ;
     RECT  36.325 27.888 37.621 28.488 ;
     RECT  37.621 27.888 37.667 29.112 ;
     RECT  37.667 28.272 37.757 29.112 ;
     RECT  37.069 4.512 37.763 4.536 ;
     RECT  37.189 50.688 37.793 50.712 ;
     RECT  36.419 30.288 37.825 30.312 ;
     RECT  37.825 30.24 37.955 30.312 ;
     RECT  37.861 49.008 38.051 49.032 ;
     RECT  37.757 28.272 38.147 28.536 ;
     RECT  37.073 24.48 38.293 24.504 ;
     RECT  38.185 3.408 38.339 3.432 ;
     RECT  38.197 48.432 38.369 48.456 ;
     RECT  38.293 23.952 38.437 24.504 ;
     RECT  37.429 22.128 38.509 22.152 ;
     RECT  38.437 23.136 38.509 24.504 ;
     RECT  38.509 22.128 38.531 24.504 ;
     RECT  38.257 32.496 38.725 32.52 ;
     RECT  35.201 42.432 38.761 42.456 ;
     RECT  38.725 31.872 38.771 32.52 ;
     RECT  38.54 49.584 38.773 49.608 ;
     RECT  37.573 20.016 38.78 20.04 ;
     RECT  38.761 42.432 38.801 42.552 ;
     RECT  38.78 19.92 38.821 20.04 ;
     RECT  38.789 21.12 38.821 21.144 ;
     RECT  38.821 19.92 38.867 21.144 ;
     RECT  38.867 20.4 38.873 21.144 ;
     RECT  38.761 3.936 38.915 3.96 ;
     RECT  38.773 49.584 38.981 50.136 ;
     RECT  38.905 45.6 39.011 45.624 ;
     RECT  37.955 30.288 39.013 30.312 ;
     RECT  39.013 30.192 39.097 30.744 ;
     RECT  36.929 0.144 39.157 0.168 ;
     RECT  38.771 31.872 39.161 31.896 ;
     RECT  38.147 28.272 39.337 28.296 ;
     RECT  39.097 30.192 39.349 30.312 ;
     RECT  38.531 22.128 39.493 23.16 ;
     RECT  38.531 24.48 39.493 24.504 ;
     RECT  37.813 51.696 39.521 51.72 ;
     RECT  38.689 26.208 39.877 26.232 ;
     RECT  39.925 48.384 40.069 48.408 ;
     RECT  39.581 49.536 40.069 49.56 ;
     RECT  39.74 50.736 40.069 51.672 ;
     RECT  38.941 18.816 40.208 18.84 ;
     RECT  38.873 20.4 40.208 20.424 ;
     RECT  39.493 22.128 40.208 24.504 ;
     RECT  39.877 26.112 40.208 26.232 ;
     RECT  39.337 28.272 40.208 29.064 ;
     RECT  39.349 30.048 40.208 30.312 ;
     RECT  36.133 40.56 40.208 40.584 ;
     RECT  38.801 42.528 40.208 42.552 ;
     RECT  39.157 45.552 40.208 45.576 ;
     RECT  40.069 48.384 40.208 48.504 ;
     RECT  40.069 49.536 40.208 51.672 ;
     RECT  40.208 2.148 40.312 51.672 ;
     RECT  40.312 50.592 40.403 51.672 ;
     RECT  40.312 2.418 40.504 49.422 ;
     RECT  39.157 0.144 40.673 0.264 ;
     RECT  40.504 42.528 40.739 42.552 ;
     RECT  40.504 47.328 40.739 47.928 ;
     RECT  40.739 47.904 40.787 47.928 ;
     RECT  40.504 18.816 40.817 18.84 ;
     RECT  40.504 29.664 40.883 31.368 ;
     RECT  40.403 50.592 40.961 50.712 ;
     RECT  40.961 50.592 41.033 50.664 ;
     RECT  40.504 6.24 41.075 6.264 ;
     RECT  40.504 26.112 41.123 28.68 ;
     RECT  41.123 26.112 41.293 27.96 ;
     RECT  40.504 49.008 41.365 49.422 ;
     RECT  41.033 50.592 41.393 50.616 ;
     RECT  40.883 30.288 41.429 31.368 ;
     RECT  40.504 23.952 41.533 23.976 ;
     RECT  41.557 33.648 41.644 33.672 ;
     RECT  41.293 26.112 41.645 27.096 ;
     RECT  41.533 23.904 41.651 23.976 ;
     RECT  40.504 21.504 41.825 21.624 ;
     RECT  40.504 22.752 41.825 22.776 ;
     RECT  41.365 49.008 42.041 49.56 ;
     RECT  41.429 30.288 42.185 31.32 ;
     RECT  42.185 30.288 42.217 30.744 ;
     RECT  42.14 3.936 42.227 3.96 ;
     RECT  42.217 30.048 42.289 30.744 ;
     RECT  40.673 0.144 42.397 0.168 ;
     RECT  42.289 29.088 42.419 30.744 ;
     RECT  42.041 49.008 42.581 49.032 ;
     RECT  41.651 23.952 42.611 23.976 ;
     RECT  42.419 30.048 42.617 30.744 ;
     RECT  40.504 45.936 42.757 45.96 ;
     RECT  42.757 45.936 42.797 46.056 ;
     RECT  42.757 47.328 42.841 47.352 ;
     RECT  40.504 20.496 42.905 20.52 ;
     RECT  42.397 0.144 42.977 0.552 ;
     RECT  43.1 48.48 43.187 48.504 ;
     RECT  41.989 18.816 43.201 18.84 ;
     RECT  42.949 51.696 43.292 51.72 ;
     RECT  42.685 23.856 43.301 23.88 ;
     RECT  43.292 2.256 43.379 2.28 ;
     RECT  43.369 19.392 43.571 19.416 ;
     RECT  41.645 26.208 43.589 27.096 ;
     RECT  42.721 25.152 43.657 25.176 ;
     RECT  42.617 30.048 43.909 30.312 ;
     RECT  43.909 30.048 43.981 30.36 ;
     RECT  42.977 0.144 44.005 0.168 ;
     RECT  43.981 30.048 44.005 30.792 ;
     RECT  44.005 29.136 44.012 30.792 ;
     RECT  44.012 28.368 44.051 30.792 ;
     RECT  43.909 15.984 44.057 16.008 ;
     RECT  43.589 26.784 44.06 27.096 ;
     RECT  44.051 28.368 44.092 29.16 ;
     RECT  44.06 26.784 44.101 27.24 ;
     RECT  44.092 28.368 44.101 28.392 ;
     RECT  44.101 26.784 44.147 28.392 ;
     RECT  43.837 22.608 44.149 22.632 ;
     RECT  42.797 46.032 44.149 46.056 ;
     RECT  44.051 30.192 44.161 30.792 ;
     RECT  41.825 21.6 44.195 21.624 ;
     RECT  44.147 27.888 44.195 28.392 ;
     RECT  43.333 20.448 44.197 20.472 ;
     RECT  44.161 30.192 44.237 31.368 ;
     RECT  44.237 30.672 44.245 31.368 ;
     RECT  44.245 30.672 44.339 30.84 ;
     RECT  44.149 22.608 44.588 22.776 ;
     RECT  43.292 50.736 44.597 51.72 ;
     RECT  44.725 19.392 44.773 19.416 ;
     RECT  44.197 20.448 44.773 20.568 ;
     RECT  44.773 19.392 44.917 20.568 ;
     RECT  44.597 50.736 44.917 50.76 ;
     RECT  44.005 0.144 44.953 0.264 ;
     RECT  43.657 24.528 45.013 25.176 ;
     RECT  44.845 26.256 45.013 26.28 ;
     RECT  44.953 0.144 45.155 1.128 ;
     RECT  44.917 19.152 45.169 20.568 ;
     RECT  44.588 22.608 45.385 23.544 ;
     RECT  45.013 24.528 45.385 26.28 ;
     RECT  44.339 30.672 45.493 30.696 ;
     RECT  44.917 50.688 45.493 50.76 ;
     RECT  45.457 1.968 45.529 1.992 ;
     RECT  45.169 19.152 45.565 21.144 ;
     RECT  45.385 22.608 45.565 26.28 ;
     RECT  45.529 1.968 45.608 2.04 ;
     RECT  45.565 19.152 45.608 26.28 ;
     RECT  44.195 27.888 45.608 27.912 ;
     RECT  45.493 29.76 45.608 30.696 ;
     RECT  40.504 40.56 45.608 40.584 ;
     RECT  45.109 44.976 45.608 45 ;
     RECT  44.149 46.032 45.608 46.248 ;
     RECT  43.868 49.008 45.608 49.032 ;
     RECT  45.493 50.16 45.608 50.76 ;
     RECT  45.608 1.968 45.904 50.76 ;
     RECT  45.904 1.968 45.923 1.992 ;
     RECT  45.904 49.584 45.923 50.76 ;
     RECT  45.904 25.728 46.001 26.76 ;
     RECT  45.923 50.688 46.069 50.76 ;
     RECT  45.904 29.616 46.115 29.64 ;
     RECT  45.904 30.624 46.117 31.368 ;
     RECT  45.904 24.528 46.153 24.744 ;
     RECT  45.155 0.144 46.241 0.168 ;
     RECT  46.069 50.688 46.289 51.72 ;
     RECT  46.241 0.144 46.324 0.264 ;
     RECT  46.289 51.648 46.325 51.72 ;
     RECT  46.324 0.144 46.469 0.312 ;
     RECT  45.904 19.392 46.499 20.04 ;
     RECT  45.904 21.696 46.541 23.112 ;
     RECT  46.541 22.752 46.649 23.112 ;
     RECT  46.001 26.208 46.691 26.76 ;
     RECT  46.649 22.8 46.721 23.112 ;
     RECT  45.923 49.584 46.739 49.608 ;
     RECT  46.325 51.696 46.757 51.72 ;
     RECT  46.393 1.68 46.883 1.704 ;
     RECT  45.904 46.032 46.937 46.248 ;
     RECT  46.885 50.112 47.009 50.136 ;
     RECT  46.721 22.8 47.075 22.824 ;
     RECT  46.937 46.128 47.077 46.248 ;
     RECT  45.904 27.888 47.113 28.2 ;
     RECT  46.153 24.72 47.185 24.744 ;
     RECT  46.691 26.208 47.185 26.28 ;
     RECT  47.077 46.128 47.189 46.728 ;
     RECT  47.113 27.36 47.267 28.2 ;
     RECT  46.541 21.696 47.269 21.72 ;
     RECT  46.117 30.624 47.329 30.792 ;
     RECT  47.185 24.72 47.404 26.28 ;
     RECT  47.329 30.24 47.459 30.792 ;
     RECT  47.42 47.904 47.507 47.928 ;
     RECT  47.404 24.72 47.549 25.704 ;
     RECT  47.267 28.176 47.585 28.2 ;
     RECT  47.269 21.648 47.605 21.72 ;
     RECT  47.612 50.16 47.699 50.76 ;
     RECT  47.605 21.12 47.729 21.72 ;
     RECT  47.459 30.768 47.765 30.792 ;
     RECT  47.729 21.648 47.843 21.72 ;
     RECT  47.699 50.16 47.939 50.184 ;
     RECT  46.469 0.144 48.013 0.168 ;
     RECT  47.941 23.376 48.044 23.4 ;
     RECT  47.843 21.696 48.085 21.72 ;
     RECT  48.044 23.376 48.085 23.544 ;
     RECT  48.085 21.696 48.131 23.544 ;
     RECT  46.499 20.016 48.161 20.04 ;
     RECT  47.869 26.784 48.197 26.808 ;
     RECT  48.085 47.856 48.197 47.88 ;
     RECT  48.131 21.696 48.227 22.824 ;
     RECT  48.227 21.696 48.233 22.632 ;
     RECT  47.549 25.68 48.269 25.704 ;
     RECT  47.189 46.128 48.305 46.152 ;
     RECT  48.365 19.968 48.449 19.992 ;
     RECT  48.265 42.96 48.572 42.984 ;
     RECT  45.904 40.56 48.593 40.584 ;
     RECT  48.517 18.816 48.611 18.84 ;
     RECT  48.572 42.144 48.659 42.984 ;
     RECT  48.572 44.016 48.659 44.04 ;
     RECT  48.013 0.144 48.803 0.552 ;
     RECT  48.589 46.704 48.913 46.776 ;
     RECT  48.445 30.24 48.995 30.264 ;
     RECT  48.049 49.584 49.093 50.136 ;
     RECT  48.913 46.704 49.097 47.448 ;
     RECT  49.093 1.68 49.187 1.704 ;
     RECT  49.196 23.712 49.283 23.736 ;
     RECT  49.201 2.208 49.309 2.232 ;
     RECT  49.165 21.072 49.331 21.096 ;
     RECT  49.165 51.648 49.331 51.672 ;
     RECT  49.093 49.44 49.381 50.136 ;
     RECT  49.309 17.088 49.427 17.112 ;
     RECT  49.097 47.424 49.457 47.448 ;
     RECT  49.417 42.048 49.501 42.072 ;
     RECT  49.165 7.392 49.619 7.416 ;
     RECT  49.309 2.208 49.811 2.28 ;
     RECT  48.803 0.144 49.885 0.168 ;
     RECT  49.811 2.208 50.003 2.232 ;
     RECT  49.381 49.44 50.173 50.328 ;
     RECT  49.345 14.208 50.195 14.232 ;
     RECT  50.173 49.056 50.291 50.328 ;
     RECT  49.885 0.144 50.387 1.128 ;
     RECT  50.291 49.488 50.483 50.328 ;
     RECT  50.483 49.488 50.675 50.232 ;
     RECT  50.675 50.064 51.059 50.232 ;
     RECT  50.387 0.144 51.113 0.168 ;
     RECT  51.059 50.064 51.251 50.088 ;
    LAYER M5 ;
     RECT  0.696 0.016 0.864 0.084 ;
     RECT  0.888 0.016 1.056 0.084 ;
     RECT  1.08 0.016 1.248 0.084 ;
     RECT  1.272 0.016 1.44 0.084 ;
     RECT  1.464 0.016 1.632 0.084 ;
     RECT  1.656 0.016 1.824 0.084 ;
     RECT  1.848 0.016 2.016 0.084 ;
     RECT  2.04 0.016 2.208 0.084 ;
     RECT  2.232 0.016 2.4 0.084 ;
     RECT  2.424 0.016 2.592 0.084 ;
     RECT  2.616 0.016 2.832 0.084 ;
     RECT  2.856 0.016 3.024 0.084 ;
     RECT  3.048 0.016 3.216 0.084 ;
     RECT  3.24 0.016 3.408 0.084 ;
     RECT  3.432 0.016 3.6 0.084 ;
     RECT  3.624 0.016 3.792 0.084 ;
     RECT  3.816 0.016 3.984 0.084 ;
     RECT  4.008 0.016 4.176 0.084 ;
     RECT  4.2 0.016 4.368 0.084 ;
     RECT  4.392 0.016 4.56 0.084 ;
     RECT  4.584 0.016 4.752 0.084 ;
     RECT  4.776 0.016 4.944 0.084 ;
     RECT  4.968 0.016 5.136 0.084 ;
     RECT  5.16 0.016 5.328 0.084 ;
     RECT  5.352 0.016 5.52 0.084 ;
     RECT  5.544 0.016 5.712 0.084 ;
     RECT  5.736 0.016 5.904 0.084 ;
     RECT  5.928 0.016 6.096 0.084 ;
     RECT  6.12 0.016 6.288 0.084 ;
     RECT  6.312 0.016 6.48 0.084 ;
     RECT  6.504 0.016 6.672 0.084 ;
     RECT  6.696 0.016 6.864 0.084 ;
     RECT  6.888 0.016 7.056 0.084 ;
     RECT  7.08 0.016 7.248 0.084 ;
     RECT  7.272 0.016 7.488 0.084 ;
     RECT  7.512 0.016 7.68 0.084 ;
     RECT  7.704 0.016 7.872 0.084 ;
     RECT  7.896 0.016 8.064 0.084 ;
     RECT  8.088 0.016 8.256 0.084 ;
     RECT  8.28 0.016 8.448 0.084 ;
     RECT  8.472 0.016 8.64 0.084 ;
     RECT  8.664 0.016 8.832 0.084 ;
     RECT  8.856 0.016 9.024 0.084 ;
     RECT  9.048 0.016 9.216 0.084 ;
     RECT  9.24 0.016 9.408 0.084 ;
     RECT  9.432 0.016 9.6 0.084 ;
     RECT  9.624 0.016 9.792 0.084 ;
     RECT  9.816 0.016 9.984 0.084 ;
     RECT  10.008 0.016 10.176 0.084 ;
     RECT  10.2 0.016 10.368 0.084 ;
     RECT  10.392 0.016 10.56 0.084 ;
     RECT  10.584 0.016 10.752 0.084 ;
     RECT  10.776 0.016 10.944 0.084 ;
     RECT  10.968 0.016 11.136 0.084 ;
     RECT  11.16 0.016 11.328 0.084 ;
     RECT  11.352 0.016 11.52 0.084 ;
     RECT  11.544 0.016 11.712 0.084 ;
     RECT  11.736 0.016 11.904 0.084 ;
     RECT  11.928 0.016 12.144 0.084 ;
     RECT  12.168 0.016 12.336 0.084 ;
     RECT  12.36 0.016 12.528 0.084 ;
     RECT  12.552 0.016 12.72 0.084 ;
     RECT  12.744 0.016 12.912 0.084 ;
     RECT  12.936 0.016 13.104 0.084 ;
     RECT  13.128 0.016 13.296 0.084 ;
     RECT  13.32 0.016 13.488 0.084 ;
     RECT  13.512 0.016 13.68 0.084 ;
     RECT  13.704 0.016 13.872 0.084 ;
     RECT  13.896 0.016 14.064 0.084 ;
     RECT  14.088 0.016 14.256 0.084 ;
     RECT  14.28 0.016 14.448 0.084 ;
     RECT  14.472 0.016 14.64 0.084 ;
     RECT  14.664 0.016 14.832 0.084 ;
     RECT  14.856 0.016 15.024 0.084 ;
     RECT  15.048 0.016 15.216 0.084 ;
     RECT  15.24 0.016 15.408 0.084 ;
     RECT  15.432 0.016 15.6 0.084 ;
     RECT  15.624 0.016 15.792 0.084 ;
     RECT  15.816 0.016 15.984 0.084 ;
     RECT  16.008 0.016 16.176 0.084 ;
     RECT  16.2 0.016 16.368 0.084 ;
     RECT  16.392 0.016 16.56 0.084 ;
     RECT  16.584 0.016 16.8 0.084 ;
     RECT  16.824 0.016 16.992 0.084 ;
     RECT  17.016 0.016 17.184 0.084 ;
     RECT  17.208 0.016 17.376 0.084 ;
     RECT  17.4 0.016 17.568 0.084 ;
     RECT  17.592 0.016 17.76 0.084 ;
     RECT  17.784 0.016 17.952 0.084 ;
     RECT  17.976 0.016 18.144 0.084 ;
     RECT  18.168 0.016 18.336 0.084 ;
     RECT  18.36 0.016 18.528 0.084 ;
     RECT  18.552 0.016 18.72 0.084 ;
     RECT  18.744 0.016 18.912 0.084 ;
     RECT  18.936 0.016 19.104 0.084 ;
     RECT  19.128 0.016 19.296 0.084 ;
     RECT  19.32 0.016 19.488 0.084 ;
     RECT  19.512 0.016 19.68 0.084 ;
     RECT  19.704 0.016 19.872 0.084 ;
     RECT  19.896 0.016 20.064 0.084 ;
     RECT  20.088 0.016 20.256 0.084 ;
     RECT  20.28 0.016 20.448 0.084 ;
     RECT  20.472 0.016 20.64 0.084 ;
     RECT  20.664 0.016 20.832 0.084 ;
     RECT  20.856 0.016 21.024 0.084 ;
     RECT  21.048 0.016 21.216 0.084 ;
     RECT  21.24 0.016 21.456 0.084 ;
     RECT  21.48 0.016 21.648 0.084 ;
     RECT  21.672 0.016 21.84 0.084 ;
     RECT  21.864 0.016 22.032 0.084 ;
     RECT  22.056 0.016 22.224 0.084 ;
     RECT  22.248 0.016 22.416 0.084 ;
     RECT  22.44 0.016 22.608 0.084 ;
     RECT  22.632 0.016 22.8 0.084 ;
     RECT  22.824 0.016 22.992 0.084 ;
     RECT  23.016 0.016 23.184 0.084 ;
     RECT  23.208 0.016 23.376 0.084 ;
     RECT  23.4 0.016 23.568 0.084 ;
     RECT  23.592 0.016 23.76 0.084 ;
     RECT  23.784 0.016 23.952 0.084 ;
     RECT  23.976 0.016 24.144 0.084 ;
     RECT  24.168 0.016 24.336 0.084 ;
     RECT  24.36 0.016 24.528 0.084 ;
     RECT  24.552 0.016 24.72 0.084 ;
     RECT  24.744 0.016 24.912 0.084 ;
     RECT  24.936 0.016 25.104 0.084 ;
     RECT  25.128 0.016 25.296 0.084 ;
     RECT  25.32 0.016 25.488 0.084 ;
     RECT  25.512 0.016 25.68 0.084 ;
     RECT  25.704 0.016 25.872 0.084 ;
     RECT  25.896 0.016 26.112 0.084 ;
     RECT  26.136 0.016 26.304 0.084 ;
     RECT  26.328 0.016 26.496 0.084 ;
     RECT  26.52 0.016 26.688 0.084 ;
     RECT  26.712 0.016 26.88 0.084 ;
     RECT  26.904 0.016 27.072 0.084 ;
     RECT  27.096 0.016 27.264 0.084 ;
     RECT  27.288 0.016 27.456 0.084 ;
     RECT  27.48 0.016 27.648 0.084 ;
     RECT  27.672 0.016 27.84 0.084 ;
     RECT  27.864 0.016 28.032 0.084 ;
     RECT  28.056 0.016 28.224 0.084 ;
     RECT  28.248 0.016 28.416 0.084 ;
     RECT  28.44 0.016 28.608 0.084 ;
     RECT  28.632 0.016 28.8 0.084 ;
     RECT  28.824 0.016 28.992 0.084 ;
     RECT  29.016 0.016 29.184 0.084 ;
     RECT  29.208 0.016 29.376 0.084 ;
     RECT  29.4 0.016 29.568 0.084 ;
     RECT  29.592 0.016 29.76 0.084 ;
     RECT  29.784 0.016 29.952 0.084 ;
     RECT  29.976 0.016 30.144 0.084 ;
     RECT  30.168 0.016 30.336 0.084 ;
     RECT  30.36 0.016 30.528 0.084 ;
     RECT  30.552 0.016 30.768 0.084 ;
     RECT  30.792 0.016 30.96 0.084 ;
     RECT  30.984 0.016 31.152 0.084 ;
     RECT  31.176 0.016 31.344 0.084 ;
     RECT  31.368 0.016 31.536 0.084 ;
     RECT  31.56 0.016 31.728 0.084 ;
     RECT  31.752 0.016 31.92 0.084 ;
     RECT  31.944 0.016 32.112 0.084 ;
     RECT  32.136 0.016 32.304 0.084 ;
     RECT  32.328 0.016 32.496 0.084 ;
     RECT  32.52 0.016 32.688 0.084 ;
     RECT  32.712 0.016 32.88 0.084 ;
     RECT  32.904 0.016 33.072 0.084 ;
     RECT  33.096 0.016 33.264 0.084 ;
     RECT  33.288 0.016 33.456 0.084 ;
     RECT  33.48 0.016 33.648 0.084 ;
     RECT  33.672 0.016 33.84 0.084 ;
     RECT  33.864 0.016 34.032 0.084 ;
     RECT  34.056 0.016 34.224 0.084 ;
     RECT  34.248 0.016 34.416 0.084 ;
     RECT  34.44 0.016 34.608 0.084 ;
     RECT  34.632 0.016 34.8 0.084 ;
     RECT  34.824 0.016 34.992 0.084 ;
     RECT  35.016 0.016 35.184 0.084 ;
     RECT  35.208 0.016 35.424 0.084 ;
     RECT  35.448 0.016 35.616 0.084 ;
     RECT  35.64 0.016 35.808 0.084 ;
     RECT  35.832 0.016 36 0.084 ;
     RECT  36.024 0.016 36.192 0.084 ;
     RECT  36.216 0.016 36.384 0.084 ;
     RECT  36.408 0.016 36.576 0.084 ;
     RECT  36.6 0.016 36.768 0.084 ;
     RECT  36.792 0.016 36.96 0.084 ;
     RECT  36.984 0.016 37.152 0.084 ;
     RECT  37.176 0.016 37.344 0.084 ;
     RECT  37.368 0.016 37.536 0.084 ;
     RECT  37.56 0.016 37.728 0.084 ;
     RECT  37.752 0.016 37.92 0.084 ;
     RECT  37.944 0.016 38.112 0.084 ;
     RECT  38.136 0.016 38.304 0.084 ;
     RECT  38.328 0.016 38.496 0.084 ;
     RECT  38.52 0.016 38.688 0.084 ;
     RECT  38.712 0.016 38.88 0.084 ;
     RECT  38.904 0.016 39.072 0.084 ;
     RECT  39.096 0.016 39.264 0.084 ;
     RECT  39.288 0.016 39.456 0.084 ;
     RECT  39.48 0.016 39.648 0.084 ;
     RECT  39.672 0.016 39.84 0.084 ;
     RECT  39.864 0.016 40.08 0.084 ;
     RECT  40.104 0.016 40.272 0.084 ;
     RECT  40.296 0.016 40.464 0.084 ;
     RECT  40.488 0.016 40.656 0.084 ;
     RECT  40.68 0.016 40.848 0.084 ;
     RECT  40.872 0.016 41.04 0.084 ;
     RECT  41.064 0.016 41.232 0.084 ;
     RECT  41.256 0.016 41.424 0.084 ;
     RECT  41.448 0.016 41.616 0.084 ;
     RECT  41.64 0.016 41.808 0.084 ;
     RECT  41.832 0.016 42 0.084 ;
     RECT  42.024 0.016 42.192 0.084 ;
     RECT  42.216 0.016 42.384 0.084 ;
     RECT  42.408 0.016 42.576 0.084 ;
     RECT  42.6 0.016 42.768 0.084 ;
     RECT  42.792 0.016 42.96 0.084 ;
     RECT  42.984 0.016 43.152 0.084 ;
     RECT  43.176 0.016 43.344 0.084 ;
     RECT  43.368 0.016 43.536 0.084 ;
     RECT  43.56 0.016 43.728 0.084 ;
     RECT  43.752 0.016 43.92 0.084 ;
     RECT  43.944 0.016 44.112 0.084 ;
     RECT  44.136 0.016 44.304 0.084 ;
     RECT  44.328 0.016 44.496 0.084 ;
     RECT  44.52 0.016 44.736 0.084 ;
     RECT  44.76 0.016 44.928 0.084 ;
     RECT  44.952 0.016 45.12 0.084 ;
     RECT  45.144 0.016 45.312 0.084 ;
     RECT  45.336 0.016 45.504 0.084 ;
     RECT  45.528 0.016 45.696 0.084 ;
     RECT  45.72 0.016 45.888 0.084 ;
     RECT  45.912 0.016 46.08 0.084 ;
     RECT  46.104 0.016 46.272 0.084 ;
     RECT  46.296 0.016 46.464 0.084 ;
     RECT  46.488 0.016 46.656 0.084 ;
     RECT  46.68 0.016 46.848 0.084 ;
     RECT  46.872 0.016 47.04 0.084 ;
     RECT  47.064 0.016 47.232 0.084 ;
     RECT  47.256 0.016 47.424 0.084 ;
     RECT  47.448 0.016 47.616 0.084 ;
     RECT  47.64 0.016 47.808 0.084 ;
     RECT  47.832 0.016 48 0.084 ;
     RECT  48.024 0.016 48.192 0.084 ;
     RECT  48.216 0.016 48.384 0.084 ;
     RECT  48.408 0.016 48.576 0.084 ;
     RECT  48.6 0.016 48.768 0.084 ;
     RECT  48.792 0.016 48.96 0.084 ;
     RECT  48.984 0.016 49.152 0.084 ;
     RECT  49.176 0.016 49.392 0.084 ;
     RECT  49.416 0.016 49.584 0.084 ;
     RECT  49.608 0.016 49.776 0.084 ;
     RECT  49.8 0.016 49.968 0.084 ;
     RECT  49.992 0.016 50.16 0.084 ;
     RECT  50.184 0.016 50.352 0.084 ;
     RECT  0.672 0.084 50.376 1.139 ;
     RECT  0.672 1.139 50.184 5.123 ;
     RECT  4.944 5.123 50.184 8.531 ;
     RECT  9.216 8.531 50.184 14.243 ;
     RECT  9.216 14.243 49.416 17.123 ;
     RECT  0.672 5.123 3.816 18.275 ;
     RECT  1.056 18.275 3.816 18.467 ;
     RECT  9.216 17.123 48.984 18.851 ;
     RECT  12.912 18.851 13.608 18.995 ;
     RECT  1.248 18.467 3.816 19.427 ;
     RECT  22.032 18.851 48.984 20.579 ;
     RECT  1.44 19.427 3.816 20.627 ;
     RECT  45.312 20.579 48.984 21.061 ;
     RECT  1.824 20.627 3.816 21.155 ;
     RECT  22.032 20.579 44.328 21.155 ;
     RECT  45.312 21.061 49.32 21.155 ;
     RECT  15.024 18.851 20.472 21.539 ;
     RECT  4.944 8.531 8.232 22.067 ;
     RECT  9.216 18.851 11.928 22.259 ;
     RECT  22.032 21.155 33.48 22.259 ;
     RECT  34.608 21.155 44.328 22.597 ;
     RECT  45.504 21.155 49.32 22.597 ;
     RECT  17.376 21.539 20.472 22.693 ;
     RECT  22.032 22.259 30.744 22.693 ;
     RECT  34.608 22.597 49.32 22.835 ;
     RECT  15.024 21.539 16.392 23.125 ;
     RECT  14.784 23.125 16.392 23.317 ;
     RECT  17.376 22.693 30.744 23.317 ;
     RECT  2.256 21.155 3.816 23.411 ;
     RECT  4.944 22.067 8.112 23.411 ;
     RECT  9.216 22.259 11.544 23.411 ;
     RECT  14.784 23.317 30.744 23.411 ;
     RECT  39.504 22.835 49.32 23.555 ;
     RECT  27.648 23.411 30.744 23.893 ;
     RECT  31.728 22.259 33.48 23.893 ;
     RECT  9.216 23.411 9.432 23.987 ;
     RECT  14.784 23.411 21.432 23.987 ;
     RECT  27.648 23.893 33.48 23.987 ;
     RECT  34.608 22.835 38.52 23.987 ;
     RECT  39.504 23.555 44.328 23.987 ;
     RECT  45.504 23.555 47.448 23.987 ;
     RECT  22.608 23.411 26.136 24.035 ;
     RECT  34.608 23.987 38.136 24.035 ;
     RECT  9.408 23.987 9.432 24.467 ;
     RECT  12.912 18.995 13.512 24.469 ;
     RECT  10.944 23.411 11.544 24.515 ;
     RECT  17.76 23.987 21.432 24.515 ;
     RECT  22.608 24.035 25.512 24.515 ;
     RECT  34.608 24.035 36.408 24.515 ;
     RECT  37.536 24.035 38.136 24.515 ;
     RECT  39.504 23.987 41.256 24.515 ;
     RECT  27.648 23.987 31.608 24.659 ;
     RECT  4.944 23.411 6.12 24.709 ;
     RECT  7.248 23.411 8.112 24.709 ;
     RECT  42.384 23.987 44.328 25.139 ;
     RECT  10.944 24.515 10.968 25.621 ;
     RECT  18.6 24.515 21.432 25.669 ;
     RECT  22.608 24.515 22.632 25.669 ;
     RECT  27.648 24.659 30.744 25.715 ;
     RECT  44.016 25.139 44.328 25.717 ;
     RECT  45.6 23.987 47.448 25.717 ;
     RECT  18.6 25.669 22.632 25.859 ;
     RECT  27.648 25.715 27.672 26.099 ;
     RECT  10.848 25.621 10.968 26.243 ;
     RECT  36.624 25.045 36.648 26.291 ;
     RECT  44.016 25.717 47.448 26.291 ;
     RECT  20.448 25.859 22.632 26.531 ;
     RECT  32.64 23.987 33.096 26.533 ;
     RECT  20.448 26.531 21.432 26.675 ;
     RECT  34.8 24.515 35.448 26.725 ;
     RECT  45.6 26.291 47.448 26.771 ;
     RECT  42.384 25.139 42.984 26.773 ;
     RECT  44.016 26.291 44.328 26.773 ;
     RECT  42.384 26.773 44.328 26.819 ;
     RECT  34.8 26.725 35.88 27.059 ;
     RECT  31.92 26.533 33.096 27.251 ;
     RECT  12.672 24.469 13.512 27.301 ;
     RECT  32.448 27.251 33.096 27.395 ;
     RECT  47.232 26.771 47.448 27.395 ;
     RECT  37.92 24.515 38.136 27.877 ;
     RECT  45.6 26.771 45.912 27.877 ;
     RECT  21.408 26.675 21.432 27.925 ;
     RECT  40.08 24.515 41.256 27.971 ;
     RECT  28.752 25.715 30.744 28.067 ;
     RECT  18.6 25.859 18.912 28.117 ;
     RECT  45.6 27.877 46.152 28.211 ;
     RECT  32.448 27.395 32.664 28.307 ;
     RECT  12.672 27.301 13.704 28.453 ;
     RECT  23.76 24.515 25.512 28.453 ;
     RECT  34.8 27.059 35.448 28.453 ;
     RECT  37.632 27.877 38.136 28.547 ;
     RECT  40.08 27.971 41.112 28.691 ;
     RECT  4.944 24.709 8.112 29.029 ;
     RECT  18.24 28.117 18.912 29.029 ;
     RECT  20.448 27.925 21.432 29.029 ;
     RECT  40.08 28.691 40.872 29.029 ;
     RECT  37.632 28.547 37.944 29.123 ;
     RECT  42.384 26.819 42.408 29.123 ;
     RECT  12.144 28.453 13.704 29.605 ;
     RECT  45.6 28.211 45.912 29.605 ;
     RECT  22.608 26.531 22.632 29.699 ;
     RECT  39.36 29.029 40.872 29.699 ;
     RECT  4.944 29.029 8.52 29.747 ;
     RECT  45.6 29.605 46.104 29.749 ;
     RECT  10.944 26.243 10.968 29.989 ;
     RECT  28.752 28.067 29.712 30.083 ;
     RECT  32.64 28.307 32.664 30.133 ;
     RECT  12.144 29.605 14.088 30.181 ;
     RECT  15.216 23.987 16.488 30.181 ;
     RECT  43.92 26.819 44.328 30.181 ;
     RECT  39.36 29.699 40.512 30.227 ;
     RECT  12.144 30.181 16.488 30.275 ;
     RECT  23.76 28.453 26.568 30.275 ;
     RECT  37.92 29.123 37.944 30.275 ;
     RECT  47.28 27.395 47.448 30.275 ;
     RECT  48.96 23.555 49.32 30.275 ;
     RECT  34.8 28.453 36.36 30.277 ;
     RECT  31.872 30.133 32.664 30.611 ;
     RECT  45.504 29.749 46.104 30.613 ;
     RECT  14.688 30.275 16.488 30.661 ;
     RECT  45.504 30.613 46.296 30.661 ;
     RECT  47.28 30.275 47.304 30.661 ;
     RECT  18.24 29.029 21.432 30.707 ;
     RECT  40.08 30.227 40.512 30.709 ;
     RECT  22.752 30.661 22.776 30.803 ;
     RECT  45.504 30.661 47.304 30.803 ;
     RECT  14.688 30.661 17.112 30.851 ;
     RECT  43.728 30.181 44.328 30.851 ;
     RECT  30.72 28.067 30.744 31.237 ;
     RECT  31.872 30.611 31.896 31.237 ;
     RECT  9.552 29.605 9.576 31.285 ;
     RECT  10.848 29.989 10.968 31.285 ;
     RECT  40.08 30.709 41.4 31.285 ;
     RECT  40.08 31.285 42.168 31.379 ;
     RECT  43.728 30.851 44.232 31.379 ;
     RECT  45.504 30.803 46.104 31.379 ;
     RECT  4.944 29.747 8.112 31.861 ;
     RECT  14.688 30.851 16.488 31.861 ;
     RECT  39.024 30.709 39.048 31.861 ;
     RECT  38.736 31.861 39.048 31.907 ;
     RECT  34.8 30.277 36.408 31.955 ;
     RECT  9.552 31.285 10.968 32.437 ;
     RECT  12.144 30.275 13.512 32.437 ;
     RECT  38.736 31.907 38.76 32.531 ;
     RECT  34.8 31.955 35.256 32.917 ;
     RECT  36.336 31.955 36.408 32.917 ;
     RECT  14.688 31.861 17.016 33.013 ;
     RECT  34.8 32.917 36.408 33.107 ;
     RECT  14.688 33.013 17.112 33.637 ;
     RECT  18.336 30.707 21.432 33.637 ;
     RECT  42.144 31.379 42.168 33.637 ;
     RECT  34.8 33.107 36.36 33.683 ;
     RECT  24 30.275 26.568 34.165 ;
     RECT  36.336 33.683 36.36 34.165 ;
     RECT  2.256 23.411 3.624 34.213 ;
     RECT  4.848 31.861 8.112 34.213 ;
     RECT  30.72 31.237 31.896 34.835 ;
     RECT  14.688 33.637 21.432 35.459 ;
     RECT  2.256 34.213 8.112 36.421 ;
     RECT  9.552 32.437 13.512 36.517 ;
     RECT  34.8 33.683 35.256 37.237 ;
     RECT  36.336 34.165 36.456 37.237 ;
     RECT  34.8 37.237 36.456 37.283 ;
     RECT  34.8 37.283 36.36 40.595 ;
     RECT  2.256 36.421 8.424 40.981 ;
     RECT  9.552 36.517 13.608 40.981 ;
     RECT  49.248 30.275 49.32 42.037 ;
     RECT  49.248 42.037 49.464 42.133 ;
     RECT  14.688 35.459 16.488 42.181 ;
     RECT  17.472 35.459 21.432 42.181 ;
     RECT  40.08 31.379 40.512 42.517 ;
     RECT  41.568 33.637 42.168 42.517 ;
     RECT  2.256 40.981 13.608 42.803 ;
     RECT  48.624 42.133 49.464 44.051 ;
     RECT  29.184 30.083 29.712 44.965 ;
     RECT  43.728 31.379 44.184 44.965 ;
     RECT  45.504 31.379 45.912 44.965 ;
     RECT  23.808 34.165 26.568 45.541 ;
     RECT  27.744 31.861 27.768 45.541 ;
     RECT  36.336 40.595 36.36 45.541 ;
     RECT  40.08 42.517 42.168 45.541 ;
     RECT  2.4 42.803 13.608 45.587 ;
     RECT  34.8 40.595 35.256 45.589 ;
     RECT  39.168 45.541 42.168 45.589 ;
     RECT  2.4 45.587 5.112 46.069 ;
     RECT  31.872 34.835 31.896 46.165 ;
     RECT  32.88 45.589 32.904 46.165 ;
     RECT  43.728 44.965 45.912 46.259 ;
     RECT  36.336 45.541 36.648 46.693 ;
     RECT  47.28 30.803 47.304 46.693 ;
     RECT  49.248 44.051 49.464 46.693 ;
     RECT  6.096 45.587 13.608 46.741 ;
     RECT  14.688 42.181 21.432 46.741 ;
     RECT  30.72 34.835 30.744 46.741 ;
     RECT  31.872 46.165 32.904 46.741 ;
     RECT  2.304 46.069 5.112 46.787 ;
     RECT  23.376 45.541 26.568 47.269 ;
     RECT  38.976 45.589 42.168 47.317 ;
     RECT  43.728 46.259 43.752 47.317 ;
     RECT  2.304 46.787 4.968 47.363 ;
     RECT  6.096 46.741 21.432 47.363 ;
     RECT  2.304 47.363 4.872 47.845 ;
     RECT  27.744 45.541 28.152 47.845 ;
     RECT  29.136 44.965 29.712 47.845 ;
     RECT  47.088 46.693 47.304 47.845 ;
     RECT  48.864 46.693 49.464 47.845 ;
     RECT  1.68 47.845 4.872 48.421 ;
     RECT  6.384 47.363 10.2 48.421 ;
     RECT  11.328 47.363 21.432 48.421 ;
     RECT  22.992 47.269 26.568 48.421 ;
     RECT  27.744 47.845 29.712 48.421 ;
     RECT  30.72 46.741 32.904 48.421 ;
     RECT  36.336 46.693 37.416 48.421 ;
     RECT  38.976 47.317 43.752 48.421 ;
     RECT  22.992 48.421 32.904 48.469 ;
     RECT  34.032 45.589 35.256 48.469 ;
     RECT  0.672 47.893 0.696 48.997 ;
     RECT  1.68 48.421 22.008 48.997 ;
     RECT  22.992 48.469 35.256 48.997 ;
     RECT  36.336 48.421 43.752 48.997 ;
     RECT  45.12 46.259 45.912 48.997 ;
     RECT  47.088 47.845 49.464 49.045 ;
     RECT  47.088 49.045 50.28 49.477 ;
     RECT  0.672 48.997 35.256 49.525 ;
     RECT  36.336 48.997 45.912 49.525 ;
     RECT  0.672 49.525 45.912 49.573 ;
     RECT  47.088 49.477 50.664 49.573 ;
     RECT  0.672 49.573 50.664 50.053 ;
     RECT  0.672 50.053 51.24 51.756 ;
     RECT  0.696 51.756 0.864 51.792 ;
     RECT  0.888 51.756 1.056 51.792 ;
     RECT  1.08 51.756 1.248 51.792 ;
     RECT  1.272 51.756 1.488 51.792 ;
     RECT  1.512 51.756 1.68 51.792 ;
     RECT  1.704 51.756 1.872 51.792 ;
     RECT  1.896 51.756 2.064 51.792 ;
     RECT  2.088 51.756 2.256 51.792 ;
     RECT  2.28 51.756 2.448 51.792 ;
     RECT  2.472 51.756 2.64 51.792 ;
     RECT  2.664 51.756 2.832 51.792 ;
     RECT  2.856 51.756 3.024 51.792 ;
     RECT  3.048 51.756 3.264 51.792 ;
     RECT  3.288 51.756 3.456 51.792 ;
     RECT  3.48 51.756 3.648 51.792 ;
     RECT  3.672 51.756 3.84 51.792 ;
     RECT  3.864 51.756 4.032 51.792 ;
     RECT  4.056 51.756 4.224 51.792 ;
     RECT  4.248 51.756 4.416 51.792 ;
     RECT  4.44 51.756 4.608 51.792 ;
     RECT  4.632 51.756 4.848 51.792 ;
     RECT  4.872 51.756 5.04 51.792 ;
     RECT  5.064 51.756 5.232 51.792 ;
     RECT  5.256 51.756 5.424 51.792 ;
     RECT  5.448 51.756 5.616 51.792 ;
     RECT  5.64 51.756 5.808 51.792 ;
     RECT  5.832 51.756 6 51.792 ;
     RECT  6.024 51.756 6.192 51.792 ;
     RECT  6.216 51.756 6.384 51.792 ;
     RECT  6.408 51.756 6.624 51.792 ;
     RECT  6.648 51.756 6.816 51.792 ;
     RECT  6.84 51.756 7.008 51.792 ;
     RECT  7.032 51.756 7.2 51.792 ;
     RECT  7.224 51.756 7.392 51.792 ;
     RECT  7.416 51.756 7.584 51.792 ;
     RECT  7.608 51.756 7.776 51.792 ;
     RECT  7.8 51.756 7.968 51.792 ;
     RECT  7.992 51.756 8.16 51.792 ;
     RECT  8.184 51.756 8.4 51.792 ;
     RECT  8.424 51.756 8.592 51.792 ;
     RECT  8.616 51.756 8.784 51.792 ;
     RECT  8.808 51.756 8.976 51.792 ;
     RECT  9 51.756 9.168 51.792 ;
     RECT  9.192 51.756 9.36 51.792 ;
     RECT  9.384 51.756 9.552 51.792 ;
     RECT  9.576 51.756 9.744 51.792 ;
     RECT  9.768 51.756 9.936 51.792 ;
     RECT  9.96 51.756 10.176 51.792 ;
     RECT  10.2 51.756 10.368 51.792 ;
     RECT  10.392 51.756 10.56 51.792 ;
     RECT  10.584 51.756 10.752 51.792 ;
     RECT  10.776 51.756 10.944 51.792 ;
     RECT  10.968 51.756 11.136 51.792 ;
     RECT  11.16 51.756 11.328 51.792 ;
     RECT  11.352 51.756 11.52 51.792 ;
     RECT  11.544 51.756 11.76 51.792 ;
     RECT  11.784 51.756 11.952 51.792 ;
     RECT  11.976 51.756 12.144 51.792 ;
     RECT  12.168 51.756 12.336 51.792 ;
     RECT  12.36 51.756 12.528 51.792 ;
     RECT  12.552 51.756 12.72 51.792 ;
     RECT  12.744 51.756 12.912 51.792 ;
     RECT  12.936 51.756 13.104 51.792 ;
     RECT  13.128 51.756 13.296 51.792 ;
     RECT  13.32 51.756 13.536 51.792 ;
     RECT  13.56 51.756 13.728 51.792 ;
     RECT  13.752 51.756 13.92 51.792 ;
     RECT  13.944 51.756 14.112 51.792 ;
     RECT  14.136 51.756 14.304 51.792 ;
     RECT  14.328 51.756 14.496 51.792 ;
     RECT  14.52 51.756 14.688 51.792 ;
     RECT  14.712 51.756 14.88 51.792 ;
     RECT  14.904 51.756 15.072 51.792 ;
     RECT  15.096 51.756 15.312 51.792 ;
     RECT  15.336 51.756 15.504 51.792 ;
     RECT  15.528 51.756 15.696 51.792 ;
     RECT  15.72 51.756 15.888 51.792 ;
     RECT  15.912 51.756 16.08 51.792 ;
     RECT  16.104 51.756 16.272 51.792 ;
     RECT  16.296 51.756 16.464 51.792 ;
     RECT  16.488 51.756 16.656 51.792 ;
     RECT  16.68 51.756 16.896 51.792 ;
     RECT  16.92 51.756 17.088 51.792 ;
     RECT  17.112 51.756 17.28 51.792 ;
     RECT  17.304 51.756 17.472 51.792 ;
     RECT  17.496 51.756 17.664 51.792 ;
     RECT  17.688 51.756 17.856 51.792 ;
     RECT  17.88 51.756 18.048 51.792 ;
     RECT  18.072 51.756 18.24 51.792 ;
     RECT  18.264 51.756 18.432 51.792 ;
     RECT  18.456 51.756 18.672 51.792 ;
     RECT  18.696 51.756 18.864 51.792 ;
     RECT  18.888 51.756 19.056 51.792 ;
     RECT  19.08 51.756 19.248 51.792 ;
     RECT  19.272 51.756 19.44 51.792 ;
     RECT  19.464 51.756 19.632 51.792 ;
     RECT  19.656 51.756 19.824 51.792 ;
     RECT  19.848 51.756 20.016 51.792 ;
     RECT  20.04 51.756 20.208 51.792 ;
     RECT  20.232 51.756 20.448 51.792 ;
     RECT  20.472 51.756 20.64 51.792 ;
     RECT  20.664 51.756 20.832 51.792 ;
     RECT  20.856 51.756 21.024 51.792 ;
     RECT  21.048 51.756 21.216 51.792 ;
     RECT  21.24 51.756 21.408 51.792 ;
     RECT  21.432 51.756 21.6 51.792 ;
     RECT  21.624 51.756 21.792 51.792 ;
     RECT  21.816 51.756 21.984 51.792 ;
     RECT  22.008 51.756 22.224 51.792 ;
     RECT  22.248 51.756 22.416 51.792 ;
     RECT  22.44 51.756 22.608 51.792 ;
     RECT  22.632 51.756 22.8 51.792 ;
     RECT  22.824 51.756 22.992 51.792 ;
     RECT  23.016 51.756 23.184 51.792 ;
     RECT  23.208 51.756 23.376 51.792 ;
     RECT  23.4 51.756 23.568 51.792 ;
     RECT  23.592 51.756 23.808 51.792 ;
     RECT  23.832 51.756 24 51.792 ;
     RECT  24.024 51.756 24.192 51.792 ;
     RECT  24.216 51.756 24.384 51.792 ;
     RECT  24.408 51.756 24.576 51.792 ;
     RECT  24.6 51.756 24.768 51.792 ;
     RECT  24.792 51.756 24.96 51.792 ;
     RECT  24.984 51.756 25.152 51.792 ;
     RECT  25.176 51.756 25.344 51.792 ;
     RECT  25.368 51.756 25.584 51.792 ;
     RECT  25.608 51.756 25.776 51.792 ;
     RECT  25.8 51.756 25.968 51.792 ;
     RECT  25.992 51.756 26.16 51.792 ;
     RECT  26.184 51.756 26.352 51.792 ;
     RECT  26.376 51.756 26.544 51.792 ;
     RECT  26.568 51.756 26.736 51.792 ;
     RECT  26.76 51.756 26.928 51.792 ;
     RECT  26.952 51.756 27.12 51.792 ;
     RECT  27.144 51.756 27.36 51.792 ;
     RECT  27.384 51.756 27.552 51.792 ;
     RECT  27.576 51.756 27.744 51.792 ;
     RECT  27.768 51.756 27.936 51.792 ;
     RECT  27.96 51.756 28.128 51.792 ;
     RECT  28.152 51.756 28.32 51.792 ;
     RECT  28.344 51.756 28.512 51.792 ;
     RECT  28.536 51.756 28.704 51.792 ;
     RECT  28.728 51.756 28.944 51.792 ;
     RECT  28.968 51.756 29.136 51.792 ;
     RECT  29.16 51.756 29.328 51.792 ;
     RECT  29.352 51.756 29.52 51.792 ;
     RECT  29.544 51.756 29.712 51.792 ;
     RECT  29.736 51.756 29.904 51.792 ;
     RECT  29.928 51.756 30.096 51.792 ;
     RECT  30.12 51.756 30.288 51.792 ;
     RECT  30.312 51.756 30.48 51.792 ;
     RECT  30.504 51.756 30.72 51.792 ;
     RECT  30.744 51.756 30.912 51.792 ;
     RECT  30.936 51.756 31.104 51.792 ;
     RECT  31.128 51.756 31.296 51.792 ;
     RECT  31.32 51.756 31.488 51.792 ;
     RECT  31.512 51.756 31.68 51.792 ;
     RECT  31.704 51.756 31.872 51.792 ;
     RECT  31.896 51.756 32.064 51.792 ;
     RECT  32.088 51.756 32.256 51.792 ;
     RECT  32.28 51.756 32.496 51.792 ;
     RECT  32.52 51.756 32.688 51.792 ;
     RECT  32.712 51.756 32.88 51.792 ;
     RECT  32.904 51.756 33.072 51.792 ;
     RECT  33.096 51.756 33.264 51.792 ;
     RECT  33.288 51.756 33.456 51.792 ;
     RECT  33.48 51.756 33.648 51.792 ;
     RECT  33.672 51.756 33.84 51.792 ;
     RECT  33.864 51.756 34.032 51.792 ;
     RECT  34.056 51.756 34.272 51.792 ;
     RECT  34.296 51.756 34.464 51.792 ;
     RECT  34.488 51.756 34.656 51.792 ;
     RECT  34.68 51.756 34.848 51.792 ;
     RECT  34.872 51.756 35.04 51.792 ;
     RECT  35.064 51.756 35.232 51.792 ;
     RECT  35.256 51.756 35.424 51.792 ;
     RECT  35.448 51.756 35.616 51.792 ;
     RECT  35.64 51.756 35.856 51.792 ;
     RECT  35.88 51.756 36.048 51.792 ;
     RECT  36.072 51.756 36.24 51.792 ;
     RECT  36.264 51.756 36.432 51.792 ;
     RECT  36.456 51.756 36.624 51.792 ;
     RECT  36.648 51.756 36.816 51.792 ;
     RECT  36.84 51.756 37.008 51.792 ;
     RECT  37.032 51.756 37.2 51.792 ;
     RECT  37.224 51.756 37.392 51.792 ;
     RECT  37.416 51.756 37.632 51.792 ;
     RECT  37.656 51.756 37.824 51.792 ;
     RECT  37.848 51.756 38.016 51.792 ;
     RECT  38.04 51.756 38.208 51.792 ;
     RECT  38.232 51.756 38.4 51.792 ;
     RECT  38.424 51.756 38.592 51.792 ;
     RECT  38.616 51.756 38.784 51.792 ;
     RECT  38.808 51.756 38.976 51.792 ;
     RECT  39 51.756 39.168 51.792 ;
     RECT  39.192 51.756 39.408 51.792 ;
     RECT  39.432 51.756 39.6 51.792 ;
     RECT  39.624 51.756 39.792 51.792 ;
     RECT  39.816 51.756 39.984 51.792 ;
     RECT  40.008 51.756 40.176 51.792 ;
     RECT  40.2 51.756 40.368 51.792 ;
     RECT  40.392 51.756 40.56 51.792 ;
     RECT  40.584 51.756 40.752 51.792 ;
     RECT  40.776 51.756 40.992 51.792 ;
     RECT  41.016 51.756 41.184 51.792 ;
     RECT  41.208 51.756 41.376 51.792 ;
     RECT  41.4 51.756 41.568 51.792 ;
     RECT  41.592 51.756 41.76 51.792 ;
     RECT  41.784 51.756 41.952 51.792 ;
     RECT  41.976 51.756 42.144 51.792 ;
     RECT  42.168 51.756 42.336 51.792 ;
     RECT  42.36 51.756 42.528 51.792 ;
     RECT  42.552 51.756 42.768 51.792 ;
     RECT  42.792 51.756 42.96 51.792 ;
     RECT  42.984 51.756 43.152 51.792 ;
     RECT  43.176 51.756 43.344 51.792 ;
     RECT  43.368 51.756 43.536 51.792 ;
     RECT  43.56 51.756 43.728 51.792 ;
     RECT  43.752 51.756 43.92 51.792 ;
     RECT  43.944 51.756 44.112 51.792 ;
     RECT  44.136 51.756 44.304 51.792 ;
     RECT  44.328 51.756 44.544 51.792 ;
     RECT  44.568 51.756 44.736 51.792 ;
     RECT  44.76 51.756 44.928 51.792 ;
     RECT  44.952 51.756 45.12 51.792 ;
     RECT  45.144 51.756 45.312 51.792 ;
     RECT  45.336 51.756 45.504 51.792 ;
     RECT  45.528 51.756 45.696 51.792 ;
     RECT  45.72 51.756 45.888 51.792 ;
     RECT  45.912 51.756 46.08 51.792 ;
     RECT  46.104 51.756 46.32 51.792 ;
     RECT  46.344 51.756 46.512 51.792 ;
     RECT  46.536 51.756 46.704 51.792 ;
     RECT  46.728 51.756 46.896 51.792 ;
     RECT  46.92 51.756 47.088 51.792 ;
     RECT  47.112 51.756 47.28 51.792 ;
     RECT  47.304 51.756 47.472 51.792 ;
     RECT  47.496 51.756 47.664 51.792 ;
     RECT  47.688 51.756 47.904 51.792 ;
     RECT  47.928 51.756 48.096 51.792 ;
     RECT  48.12 51.756 48.288 51.792 ;
     RECT  48.312 51.756 48.48 51.792 ;
     RECT  48.504 51.756 48.672 51.792 ;
     RECT  48.696 51.756 48.864 51.792 ;
     RECT  48.888 51.756 49.056 51.792 ;
     RECT  49.08 51.756 49.248 51.792 ;
     RECT  49.272 51.756 49.44 51.792 ;
     RECT  49.464 51.756 49.68 51.792 ;
     RECT  49.704 51.756 49.872 51.792 ;
     RECT  49.896 51.756 50.064 51.792 ;
     RECT  50.088 51.756 50.256 51.792 ;
     RECT  50.28 51.756 50.448 51.792 ;
     RECT  50.472 51.756 50.64 51.792 ;
     RECT  50.664 51.756 50.832 51.792 ;
     RECT  50.856 51.756 51.024 51.792 ;
     RECT  51.048 51.756 51.216 51.792 ;
     RECT  3.816 5.123 4.944 23.411 ;
     RECT  8.232 8.531 9.216 22.067 ;
     RECT  11.928 18.851 12.912 22.259 ;
     RECT  13.608 18.851 15.024 18.995 ;
     RECT  13.512 18.995 15.024 23.125 ;
     RECT  44.328 20.579 45.312 21.155 ;
     RECT  33.48 21.155 34.608 23.987 ;
     RECT  44.328 21.155 45.504 22.597 ;
     RECT  16.392 21.539 17.376 23.317 ;
     RECT  8.112 22.067 9.216 23.987 ;
     RECT  11.544 22.259 12.912 24.469 ;
     RECT  30.744 22.259 31.728 23.893 ;
     RECT  38.52 22.835 39.504 23.987 ;
     RECT  13.512 23.125 14.784 23.987 ;
     RECT  3.624 23.411 4.944 31.861 ;
     RECT  6.12 23.411 7.248 24.709 ;
     RECT  9.432 23.411 10.944 24.467 ;
     RECT  21.432 23.411 22.608 25.669 ;
     RECT  26.136 23.411 27.648 24.035 ;
     RECT  44.328 23.555 45.504 23.987 ;
     RECT  47.448 23.555 48.96 30.275 ;
     RECT  8.112 23.987 9.408 24.467 ;
     RECT  16.488 23.987 17.76 24.515 ;
     RECT  31.608 23.987 32.64 24.659 ;
     RECT  33.096 23.987 34.608 24.515 ;
     RECT  38.136 23.987 39.504 24.515 ;
     RECT  41.256 23.987 42.384 27.971 ;
     RECT  44.328 23.987 45.6 25.717 ;
     RECT  36.408 24.035 37.536 24.515 ;
     RECT  10.848 24.467 10.944 25.621 ;
     RECT  11.544 24.469 12.672 24.515 ;
     RECT  22.632 24.515 23.76 29.699 ;
     RECT  35.448 24.515 37.92 25.045 ;
     RECT  35.448 25.045 36.624 26.291 ;
     RECT  36.648 25.045 37.92 26.291 ;
     RECT  42.984 25.139 44.016 26.773 ;
     RECT  27.672 25.715 28.752 26.099 ;
     RECT  35.448 26.291 35.88 26.725 ;
     RECT  44.328 26.291 45.6 29.749 ;
     RECT  21.432 26.531 22.608 29.699 ;
     RECT  30.744 26.533 31.92 27.251 ;
     RECT  20.448 26.675 21.408 27.925 ;
     RECT  45.912 26.771 47.232 27.395 ;
     RECT  42.408 26.819 43.92 29.123 ;
     RECT  35.448 27.059 35.88 28.453 ;
     RECT  13.704 27.301 15.216 29.605 ;
     RECT  45.912 27.395 47.28 27.877 ;
     RECT  46.152 27.877 47.28 28.211 ;
     RECT  41.112 27.971 42.384 28.691 ;
     RECT  29.712 28.067 30.72 48.421 ;
     RECT  45.912 28.211 47.28 29.605 ;
     RECT  10.968 28.453 12.144 32.437 ;
     RECT  36.36 28.453 37.632 29.123 ;
     RECT  37.944 28.547 38.136 29.029 ;
     RECT  40.872 28.691 42.384 29.123 ;
     RECT  37.944 29.029 39.36 30.227 ;
     RECT  36.36 29.123 37.92 30.275 ;
     RECT  43.728 29.123 43.92 30.181 ;
     RECT  8.52 29.605 9.552 29.747 ;
     RECT  9.576 29.605 10.944 29.989 ;
     RECT  14.088 29.605 15.216 30.181 ;
     RECT  46.104 29.605 47.28 30.613 ;
     RECT  21.432 29.699 23.76 30.275 ;
     RECT  40.512 29.699 40.872 30.709 ;
     RECT  8.112 29.747 9.552 36.421 ;
     RECT  44.328 29.749 45.504 30.851 ;
     RECT  9.576 29.989 10.848 31.285 ;
     RECT  30.744 30.133 31.872 31.237 ;
     RECT  37.944 30.227 40.08 30.275 ;
     RECT  13.512 30.275 14.688 36.517 ;
     RECT  21.432 30.275 24 30.661 ;
     RECT  36.36 30.275 36.408 30.277 ;
     RECT  39.024 30.275 40.08 30.709 ;
     RECT  46.296 30.613 47.28 30.661 ;
     RECT  17.112 30.661 18.24 30.707 ;
     RECT  21.432 30.661 22.752 30.803 ;
     RECT  22.776 30.661 24 30.803 ;
     RECT  17.112 30.707 18.336 30.851 ;
     RECT  39.048 30.709 40.08 31.907 ;
     RECT  46.104 30.803 47.28 31.379 ;
     RECT  16.488 30.851 18.336 31.861 ;
     RECT  44.232 30.851 45.504 31.379 ;
     RECT  44.184 31.379 45.504 44.965 ;
     RECT  45.912 31.379 47.28 46.693 ;
     RECT  3.624 31.861 4.848 34.213 ;
     RECT  17.016 31.861 18.336 33.013 ;
     RECT  26.568 31.861 27.744 48.421 ;
     RECT  27.768 31.861 29.184 44.965 ;
     RECT  38.76 31.907 40.08 32.531 ;
     RECT  35.256 31.955 36.336 32.917 ;
     RECT  17.112 33.013 18.336 33.637 ;
     RECT  36.36 33.107 36.408 34.165 ;
     RECT  40.512 33.637 41.568 42.517 ;
     RECT  35.256 33.683 36.336 37.237 ;
     RECT  30.744 34.835 31.872 46.741 ;
     RECT  16.488 35.459 17.472 42.181 ;
     RECT  8.424 36.421 9.552 40.981 ;
     RECT  13.608 36.517 14.688 46.741 ;
     RECT  35.256 40.595 36.336 49.525 ;
     RECT  47.304 42.133 48.624 44.051 ;
     RECT  27.768 44.965 29.136 45.541 ;
     RECT  28.152 45.541 29.136 47.845 ;
     RECT  5.112 45.587 6.096 46.787 ;
     RECT  31.896 45.589 32.88 46.165 ;
     RECT  32.904 45.589 34.032 48.469 ;
     RECT  43.752 46.259 45.12 48.997 ;
     RECT  45.912 46.693 47.088 49.573 ;
     RECT  4.968 46.787 6.096 47.363 ;
     RECT  4.872 47.363 6.384 48.421 ;
     RECT  10.2 47.363 11.328 48.421 ;
     RECT  0.696 47.893 1.68 48.997 ;
     RECT  22.008 48.421 22.992 48.997 ;
  END
END qfd_c_stn514
END LIBRARY
